VERSION 5.8 ;
BUSBITCHARS "[]" ;
DIVIDERCHAR "/" ;
UNITS
    DATABASE MICRONS 1000 ;
END UNITS

VIA ino_decode_predict_via1_2_1000_440_1_2_410_410
  VIARULE via1Array ;
  CUTSIZE 0.19 0.19 ;
  LAYERS Metal1 Via1 Metal2 ;
  CUTSPACING 0.22 0.22 ;
  ENCLOSURE 0.05 0.125 0.005 0.05 ;
  ROWCOL 1 2 ;
END ino_decode_predict_via1_2_1000_440_1_2_410_410

VIA ino_decode_predict_via2_3_1000_440_1_2_410_410
  VIARULE via2Array ;
  CUTSIZE 0.19 0.19 ;
  LAYERS Metal2 Via2 Metal3 ;
  CUTSPACING 0.22 0.22 ;
  ENCLOSURE 0.005 0.05 0.05 0.005 ;
  ROWCOL 1 2 ;
END ino_decode_predict_via2_3_1000_440_1_2_410_410

VIA ino_decode_predict_via3_4_1000_440_1_2_410_410
  VIARULE via3Array ;
  CUTSIZE 0.19 0.19 ;
  LAYERS Metal3 Via3 Metal4 ;
  CUTSPACING 0.22 0.22 ;
  ENCLOSURE 0.05 0.005 0.2 0.05 ;
  ROWCOL 1 2 ;
END ino_decode_predict_via3_4_1000_440_1_2_410_410

VIA ino_decode_predict_via4_5_1000_2000_1_1_840_840
  VIARULE viaTop1Array ;
  CUTSIZE 0.42 0.42 ;
  LAYERS Metal4 TopVia1 TopMetal1 ;
  CUTSPACING 0.42 0.42 ;
  ENCLOSURE 0.29 0.1 0.42 0.79 ;
END ino_decode_predict_via4_5_1000_2000_1_1_840_840

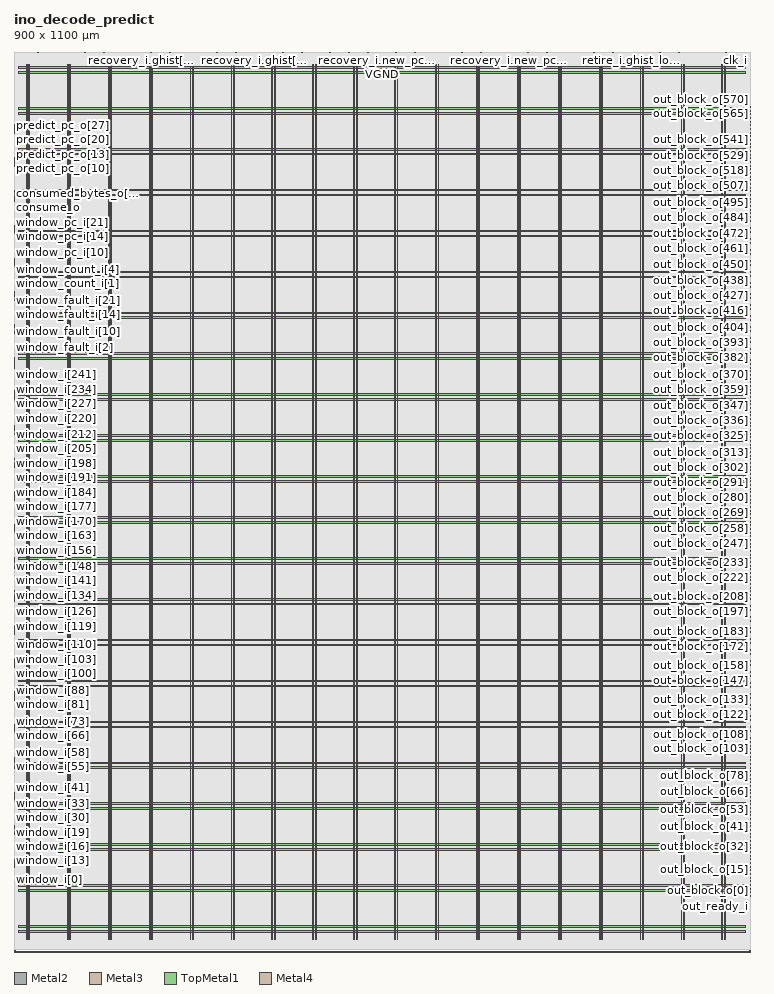
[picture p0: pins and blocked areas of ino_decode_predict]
MACRO ino_decode_predict
  FOREIGN ino_decode_predict 0 0 ;
  CLASS BLOCK ;
  SIZE 900 BY 1100 ;
  PIN clk_i
    DIRECTION INPUT ;
    USE SIGNAL ;
    PORT
      LAYER Metal2 ;
        RECT  881.56 1099.6 881.96 1100 ;
    END
  END clk_i
  PIN consume_o
    DIRECTION OUTPUT ;
    USE SIGNAL ;
    PORT
      LAYER Metal3 ;
        RECT  0 909.94 0.4 910.34 ;
    END
  END consume_o
  PIN consumed_bytes_o[0]
    DIRECTION OUTPUT ;
    USE SIGNAL ;
    PORT
      LAYER Metal3 ;
        RECT  0 912.46 0.4 912.86 ;
    END
  END consumed_bytes_o[0]
  PIN consumed_bytes_o[1]
    DIRECTION OUTPUT ;
    USE SIGNAL ;
    PORT
      LAYER Metal3 ;
        RECT  0 914.98 0.4 915.38 ;
    END
  END consumed_bytes_o[1]
  PIN consumed_bytes_o[2]
    DIRECTION OUTPUT ;
    USE SIGNAL ;
    PORT
      LAYER Metal3 ;
        RECT  0 917.5 0.4 917.9 ;
    END
  END consumed_bytes_o[2]
  PIN consumed_bytes_o[3]
    DIRECTION OUTPUT ;
    USE SIGNAL ;
    PORT
      LAYER Metal3 ;
        RECT  0 920.02 0.4 920.42 ;
    END
  END consumed_bytes_o[3]
  PIN consumed_bytes_o[4]
    DIRECTION OUTPUT ;
    USE SIGNAL ;
    PORT
      LAYER Metal3 ;
        RECT  0 922.54 0.4 922.94 ;
    END
  END consumed_bytes_o[4]
  PIN consumed_bytes_o[5]
    DIRECTION OUTPUT ;
    USE SIGNAL ;
    PORT
      LAYER Metal3 ;
        RECT  0 925.06 0.4 925.46 ;
    END
  END consumed_bytes_o[5]
  PIN out_block_o[0]
    DIRECTION OUTPUT ;
    USE SIGNAL ;
    PORT
      LAYER Metal3 ;
        RECT  899.6 74.98 900 75.38 ;
    END
  END out_block_o[0]
  PIN out_block_o[100]
    DIRECTION OUTPUT ;
    USE SIGNAL ;
    PORT
      LAYER Metal3 ;
        RECT  899.6 242.98 900 243.38 ;
    END
  END out_block_o[100]
  PIN out_block_o[101]
    DIRECTION OUTPUT ;
    USE SIGNAL ;
    PORT
      LAYER Metal3 ;
        RECT  899.6 244.66 900 245.06 ;
    END
  END out_block_o[101]
  PIN out_block_o[102]
    DIRECTION OUTPUT ;
    USE SIGNAL ;
    PORT
      LAYER Metal3 ;
        RECT  899.6 246.34 900 246.74 ;
    END
  END out_block_o[102]
  PIN out_block_o[103]
    DIRECTION OUTPUT ;
    USE SIGNAL ;
    PORT
      LAYER Metal3 ;
        RECT  899.6 248.02 900 248.42 ;
    END
  END out_block_o[103]
  PIN out_block_o[104]
    DIRECTION OUTPUT ;
    USE SIGNAL ;
    PORT
      LAYER Metal3 ;
        RECT  899.6 249.7 900 250.1 ;
    END
  END out_block_o[104]
  PIN out_block_o[105]
    DIRECTION OUTPUT ;
    USE SIGNAL ;
    PORT
      LAYER Metal3 ;
        RECT  899.6 251.38 900 251.78 ;
    END
  END out_block_o[105]
  PIN out_block_o[106]
    DIRECTION OUTPUT ;
    USE SIGNAL ;
    PORT
      LAYER Metal3 ;
        RECT  899.6 253.06 900 253.46 ;
    END
  END out_block_o[106]
  PIN out_block_o[107]
    DIRECTION OUTPUT ;
    USE SIGNAL ;
    PORT
      LAYER Metal3 ;
        RECT  899.6 254.74 900 255.14 ;
    END
  END out_block_o[107]
  PIN out_block_o[108]
    DIRECTION OUTPUT ;
    USE SIGNAL ;
    PORT
      LAYER Metal3 ;
        RECT  899.6 256.42 900 256.82 ;
    END
  END out_block_o[108]
  PIN out_block_o[109]
    DIRECTION OUTPUT ;
    USE SIGNAL ;
    PORT
      LAYER Metal3 ;
        RECT  899.6 258.1 900 258.5 ;
    END
  END out_block_o[109]
  PIN out_block_o[10]
    DIRECTION OUTPUT ;
    USE SIGNAL ;
    PORT
      LAYER Metal3 ;
        RECT  899.6 91.78 900 92.18 ;
    END
  END out_block_o[10]
  PIN out_block_o[110]
    DIRECTION OUTPUT ;
    USE SIGNAL ;
    PORT
      LAYER Metal3 ;
        RECT  899.6 259.78 900 260.18 ;
    END
  END out_block_o[110]
  PIN out_block_o[111]
    DIRECTION OUTPUT ;
    USE SIGNAL ;
    PORT
      LAYER Metal3 ;
        RECT  899.6 261.46 900 261.86 ;
    END
  END out_block_o[111]
  PIN out_block_o[112]
    DIRECTION OUTPUT ;
    USE SIGNAL ;
    PORT
      LAYER Metal3 ;
        RECT  899.6 263.14 900 263.54 ;
    END
  END out_block_o[112]
  PIN out_block_o[113]
    DIRECTION OUTPUT ;
    USE SIGNAL ;
    PORT
      LAYER Metal3 ;
        RECT  899.6 264.82 900 265.22 ;
    END
  END out_block_o[113]
  PIN out_block_o[114]
    DIRECTION OUTPUT ;
    USE SIGNAL ;
    PORT
      LAYER Metal3 ;
        RECT  899.6 266.5 900 266.9 ;
    END
  END out_block_o[114]
  PIN out_block_o[115]
    DIRECTION OUTPUT ;
    USE SIGNAL ;
    PORT
      LAYER Metal3 ;
        RECT  899.6 268.18 900 268.58 ;
    END
  END out_block_o[115]
  PIN out_block_o[116]
    DIRECTION OUTPUT ;
    USE SIGNAL ;
    PORT
      LAYER Metal3 ;
        RECT  899.6 269.86 900 270.26 ;
    END
  END out_block_o[116]
  PIN out_block_o[117]
    DIRECTION OUTPUT ;
    USE SIGNAL ;
    PORT
      LAYER Metal3 ;
        RECT  899.6 271.54 900 271.94 ;
    END
  END out_block_o[117]
  PIN out_block_o[118]
    DIRECTION OUTPUT ;
    USE SIGNAL ;
    PORT
      LAYER Metal3 ;
        RECT  899.6 273.22 900 273.62 ;
    END
  END out_block_o[118]
  PIN out_block_o[119]
    DIRECTION OUTPUT ;
    USE SIGNAL ;
    PORT
      LAYER Metal3 ;
        RECT  899.6 274.9 900 275.3 ;
    END
  END out_block_o[119]
  PIN out_block_o[11]
    DIRECTION OUTPUT ;
    USE SIGNAL ;
    PORT
      LAYER Metal3 ;
        RECT  899.6 93.46 900 93.86 ;
    END
  END out_block_o[11]
  PIN out_block_o[120]
    DIRECTION OUTPUT ;
    USE SIGNAL ;
    PORT
      LAYER Metal3 ;
        RECT  899.6 276.58 900 276.98 ;
    END
  END out_block_o[120]
  PIN out_block_o[121]
    DIRECTION OUTPUT ;
    USE SIGNAL ;
    PORT
      LAYER Metal3 ;
        RECT  899.6 278.26 900 278.66 ;
    END
  END out_block_o[121]
  PIN out_block_o[122]
    DIRECTION OUTPUT ;
    USE SIGNAL ;
    PORT
      LAYER Metal3 ;
        RECT  899.6 279.94 900 280.34 ;
    END
  END out_block_o[122]
  PIN out_block_o[123]
    DIRECTION OUTPUT ;
    USE SIGNAL ;
    PORT
      LAYER Metal3 ;
        RECT  899.6 281.62 900 282.02 ;
    END
  END out_block_o[123]
  PIN out_block_o[124]
    DIRECTION OUTPUT ;
    USE SIGNAL ;
    PORT
      LAYER Metal3 ;
        RECT  899.6 283.3 900 283.7 ;
    END
  END out_block_o[124]
  PIN out_block_o[125]
    DIRECTION OUTPUT ;
    USE SIGNAL ;
    PORT
      LAYER Metal3 ;
        RECT  899.6 284.98 900 285.38 ;
    END
  END out_block_o[125]
  PIN out_block_o[126]
    DIRECTION OUTPUT ;
    USE SIGNAL ;
    PORT
      LAYER Metal3 ;
        RECT  899.6 286.66 900 287.06 ;
    END
  END out_block_o[126]
  PIN out_block_o[127]
    DIRECTION OUTPUT ;
    USE SIGNAL ;
    PORT
      LAYER Metal3 ;
        RECT  899.6 288.34 900 288.74 ;
    END
  END out_block_o[127]
  PIN out_block_o[128]
    DIRECTION OUTPUT ;
    USE SIGNAL ;
    PORT
      LAYER Metal3 ;
        RECT  899.6 290.02 900 290.42 ;
    END
  END out_block_o[128]
  PIN out_block_o[129]
    DIRECTION OUTPUT ;
    USE SIGNAL ;
    PORT
      LAYER Metal3 ;
        RECT  899.6 291.7 900 292.1 ;
    END
  END out_block_o[129]
  PIN out_block_o[12]
    DIRECTION OUTPUT ;
    USE SIGNAL ;
    PORT
      LAYER Metal3 ;
        RECT  899.6 95.14 900 95.54 ;
    END
  END out_block_o[12]
  PIN out_block_o[130]
    DIRECTION OUTPUT ;
    USE SIGNAL ;
    PORT
      LAYER Metal3 ;
        RECT  899.6 293.38 900 293.78 ;
    END
  END out_block_o[130]
  PIN out_block_o[131]
    DIRECTION OUTPUT ;
    USE SIGNAL ;
    PORT
      LAYER Metal3 ;
        RECT  899.6 295.06 900 295.46 ;
    END
  END out_block_o[131]
  PIN out_block_o[132]
    DIRECTION OUTPUT ;
    USE SIGNAL ;
    PORT
      LAYER Metal3 ;
        RECT  899.6 296.74 900 297.14 ;
    END
  END out_block_o[132]
  PIN out_block_o[133]
    DIRECTION OUTPUT ;
    USE SIGNAL ;
    PORT
      LAYER Metal3 ;
        RECT  899.6 298.42 900 298.82 ;
    END
  END out_block_o[133]
  PIN out_block_o[134]
    DIRECTION OUTPUT ;
    USE SIGNAL ;
    PORT
      LAYER Metal3 ;
        RECT  899.6 300.1 900 300.5 ;
    END
  END out_block_o[134]
  PIN out_block_o[135]
    DIRECTION OUTPUT ;
    USE SIGNAL ;
    PORT
      LAYER Metal3 ;
        RECT  899.6 301.78 900 302.18 ;
    END
  END out_block_o[135]
  PIN out_block_o[136]
    DIRECTION OUTPUT ;
    USE SIGNAL ;
    PORT
      LAYER Metal3 ;
        RECT  899.6 303.46 900 303.86 ;
    END
  END out_block_o[136]
  PIN out_block_o[137]
    DIRECTION OUTPUT ;
    USE SIGNAL ;
    PORT
      LAYER Metal3 ;
        RECT  899.6 305.14 900 305.54 ;
    END
  END out_block_o[137]
  PIN out_block_o[138]
    DIRECTION OUTPUT ;
    USE SIGNAL ;
    PORT
      LAYER Metal3 ;
        RECT  899.6 306.82 900 307.22 ;
    END
  END out_block_o[138]
  PIN out_block_o[139]
    DIRECTION OUTPUT ;
    USE SIGNAL ;
    PORT
      LAYER Metal3 ;
        RECT  899.6 308.5 900 308.9 ;
    END
  END out_block_o[139]
  PIN out_block_o[13]
    DIRECTION OUTPUT ;
    USE SIGNAL ;
    PORT
      LAYER Metal3 ;
        RECT  899.6 96.82 900 97.22 ;
    END
  END out_block_o[13]
  PIN out_block_o[140]
    DIRECTION OUTPUT ;
    USE SIGNAL ;
    PORT
      LAYER Metal3 ;
        RECT  899.6 310.18 900 310.58 ;
    END
  END out_block_o[140]
  PIN out_block_o[141]
    DIRECTION OUTPUT ;
    USE SIGNAL ;
    PORT
      LAYER Metal3 ;
        RECT  899.6 311.86 900 312.26 ;
    END
  END out_block_o[141]
  PIN out_block_o[142]
    DIRECTION OUTPUT ;
    USE SIGNAL ;
    PORT
      LAYER Metal3 ;
        RECT  899.6 313.54 900 313.94 ;
    END
  END out_block_o[142]
  PIN out_block_o[143]
    DIRECTION OUTPUT ;
    USE SIGNAL ;
    PORT
      LAYER Metal3 ;
        RECT  899.6 315.22 900 315.62 ;
    END
  END out_block_o[143]
  PIN out_block_o[144]
    DIRECTION OUTPUT ;
    USE SIGNAL ;
    PORT
      LAYER Metal3 ;
        RECT  899.6 316.9 900 317.3 ;
    END
  END out_block_o[144]
  PIN out_block_o[145]
    DIRECTION OUTPUT ;
    USE SIGNAL ;
    PORT
      LAYER Metal3 ;
        RECT  899.6 318.58 900 318.98 ;
    END
  END out_block_o[145]
  PIN out_block_o[146]
    DIRECTION OUTPUT ;
    USE SIGNAL ;
    PORT
      LAYER Metal3 ;
        RECT  899.6 320.26 900 320.66 ;
    END
  END out_block_o[146]
  PIN out_block_o[147]
    DIRECTION OUTPUT ;
    USE SIGNAL ;
    PORT
      LAYER Metal3 ;
        RECT  899.6 321.94 900 322.34 ;
    END
  END out_block_o[147]
  PIN out_block_o[148]
    DIRECTION OUTPUT ;
    USE SIGNAL ;
    PORT
      LAYER Metal3 ;
        RECT  899.6 323.62 900 324.02 ;
    END
  END out_block_o[148]
  PIN out_block_o[149]
    DIRECTION OUTPUT ;
    USE SIGNAL ;
    PORT
      LAYER Metal3 ;
        RECT  899.6 325.3 900 325.7 ;
    END
  END out_block_o[149]
  PIN out_block_o[14]
    DIRECTION OUTPUT ;
    USE SIGNAL ;
    PORT
      LAYER Metal3 ;
        RECT  899.6 98.5 900 98.9 ;
    END
  END out_block_o[14]
  PIN out_block_o[150]
    DIRECTION OUTPUT ;
    USE SIGNAL ;
    PORT
      LAYER Metal3 ;
        RECT  899.6 326.98 900 327.38 ;
    END
  END out_block_o[150]
  PIN out_block_o[151]
    DIRECTION OUTPUT ;
    USE SIGNAL ;
    PORT
      LAYER Metal3 ;
        RECT  899.6 328.66 900 329.06 ;
    END
  END out_block_o[151]
  PIN out_block_o[152]
    DIRECTION OUTPUT ;
    USE SIGNAL ;
    PORT
      LAYER Metal3 ;
        RECT  899.6 330.34 900 330.74 ;
    END
  END out_block_o[152]
  PIN out_block_o[153]
    DIRECTION OUTPUT ;
    USE SIGNAL ;
    PORT
      LAYER Metal3 ;
        RECT  899.6 332.02 900 332.42 ;
    END
  END out_block_o[153]
  PIN out_block_o[154]
    DIRECTION OUTPUT ;
    USE SIGNAL ;
    PORT
      LAYER Metal3 ;
        RECT  899.6 333.7 900 334.1 ;
    END
  END out_block_o[154]
  PIN out_block_o[155]
    DIRECTION OUTPUT ;
    USE SIGNAL ;
    PORT
      LAYER Metal3 ;
        RECT  899.6 335.38 900 335.78 ;
    END
  END out_block_o[155]
  PIN out_block_o[156]
    DIRECTION OUTPUT ;
    USE SIGNAL ;
    PORT
      LAYER Metal3 ;
        RECT  899.6 337.06 900 337.46 ;
    END
  END out_block_o[156]
  PIN out_block_o[157]
    DIRECTION OUTPUT ;
    USE SIGNAL ;
    PORT
      LAYER Metal3 ;
        RECT  899.6 338.74 900 339.14 ;
    END
  END out_block_o[157]
  PIN out_block_o[158]
    DIRECTION OUTPUT ;
    USE SIGNAL ;
    PORT
      LAYER Metal3 ;
        RECT  899.6 340.42 900 340.82 ;
    END
  END out_block_o[158]
  PIN out_block_o[159]
    DIRECTION OUTPUT ;
    USE SIGNAL ;
    PORT
      LAYER Metal3 ;
        RECT  899.6 342.1 900 342.5 ;
    END
  END out_block_o[159]
  PIN out_block_o[15]
    DIRECTION OUTPUT ;
    USE SIGNAL ;
    PORT
      LAYER Metal3 ;
        RECT  899.6 100.18 900 100.58 ;
    END
  END out_block_o[15]
  PIN out_block_o[160]
    DIRECTION OUTPUT ;
    USE SIGNAL ;
    PORT
      LAYER Metal3 ;
        RECT  899.6 343.78 900 344.18 ;
    END
  END out_block_o[160]
  PIN out_block_o[161]
    DIRECTION OUTPUT ;
    USE SIGNAL ;
    PORT
      LAYER Metal3 ;
        RECT  899.6 345.46 900 345.86 ;
    END
  END out_block_o[161]
  PIN out_block_o[162]
    DIRECTION OUTPUT ;
    USE SIGNAL ;
    PORT
      LAYER Metal3 ;
        RECT  899.6 347.14 900 347.54 ;
    END
  END out_block_o[162]
  PIN out_block_o[163]
    DIRECTION OUTPUT ;
    USE SIGNAL ;
    PORT
      LAYER Metal3 ;
        RECT  899.6 348.82 900 349.22 ;
    END
  END out_block_o[163]
  PIN out_block_o[164]
    DIRECTION OUTPUT ;
    USE SIGNAL ;
    PORT
      LAYER Metal3 ;
        RECT  899.6 350.5 900 350.9 ;
    END
  END out_block_o[164]
  PIN out_block_o[165]
    DIRECTION OUTPUT ;
    USE SIGNAL ;
    PORT
      LAYER Metal3 ;
        RECT  899.6 352.18 900 352.58 ;
    END
  END out_block_o[165]
  PIN out_block_o[166]
    DIRECTION OUTPUT ;
    USE SIGNAL ;
    PORT
      LAYER Metal3 ;
        RECT  899.6 353.86 900 354.26 ;
    END
  END out_block_o[166]
  PIN out_block_o[167]
    DIRECTION OUTPUT ;
    USE SIGNAL ;
    PORT
      LAYER Metal3 ;
        RECT  899.6 355.54 900 355.94 ;
    END
  END out_block_o[167]
  PIN out_block_o[168]
    DIRECTION OUTPUT ;
    USE SIGNAL ;
    PORT
      LAYER Metal3 ;
        RECT  899.6 357.22 900 357.62 ;
    END
  END out_block_o[168]
  PIN out_block_o[169]
    DIRECTION OUTPUT ;
    USE SIGNAL ;
    PORT
      LAYER Metal3 ;
        RECT  899.6 358.9 900 359.3 ;
    END
  END out_block_o[169]
  PIN out_block_o[16]
    DIRECTION OUTPUT ;
    USE SIGNAL ;
    PORT
      LAYER Metal3 ;
        RECT  899.6 101.86 900 102.26 ;
    END
  END out_block_o[16]
  PIN out_block_o[170]
    DIRECTION OUTPUT ;
    USE SIGNAL ;
    PORT
      LAYER Metal3 ;
        RECT  899.6 360.58 900 360.98 ;
    END
  END out_block_o[170]
  PIN out_block_o[171]
    DIRECTION OUTPUT ;
    USE SIGNAL ;
    PORT
      LAYER Metal3 ;
        RECT  899.6 362.26 900 362.66 ;
    END
  END out_block_o[171]
  PIN out_block_o[172]
    DIRECTION OUTPUT ;
    USE SIGNAL ;
    PORT
      LAYER Metal3 ;
        RECT  899.6 363.94 900 364.34 ;
    END
  END out_block_o[172]
  PIN out_block_o[173]
    DIRECTION OUTPUT ;
    USE SIGNAL ;
    PORT
      LAYER Metal3 ;
        RECT  899.6 365.62 900 366.02 ;
    END
  END out_block_o[173]
  PIN out_block_o[174]
    DIRECTION OUTPUT ;
    USE SIGNAL ;
    PORT
      LAYER Metal3 ;
        RECT  899.6 367.3 900 367.7 ;
    END
  END out_block_o[174]
  PIN out_block_o[175]
    DIRECTION OUTPUT ;
    USE SIGNAL ;
    PORT
      LAYER Metal3 ;
        RECT  899.6 368.98 900 369.38 ;
    END
  END out_block_o[175]
  PIN out_block_o[176]
    DIRECTION OUTPUT ;
    USE SIGNAL ;
    PORT
      LAYER Metal3 ;
        RECT  899.6 370.66 900 371.06 ;
    END
  END out_block_o[176]
  PIN out_block_o[177]
    DIRECTION OUTPUT ;
    USE SIGNAL ;
    PORT
      LAYER Metal3 ;
        RECT  899.6 372.34 900 372.74 ;
    END
  END out_block_o[177]
  PIN out_block_o[178]
    DIRECTION OUTPUT ;
    USE SIGNAL ;
    PORT
      LAYER Metal3 ;
        RECT  899.6 374.02 900 374.42 ;
    END
  END out_block_o[178]
  PIN out_block_o[179]
    DIRECTION OUTPUT ;
    USE SIGNAL ;
    PORT
      LAYER Metal3 ;
        RECT  899.6 375.7 900 376.1 ;
    END
  END out_block_o[179]
  PIN out_block_o[17]
    DIRECTION OUTPUT ;
    USE SIGNAL ;
    PORT
      LAYER Metal3 ;
        RECT  899.6 103.54 900 103.94 ;
    END
  END out_block_o[17]
  PIN out_block_o[180]
    DIRECTION OUTPUT ;
    USE SIGNAL ;
    PORT
      LAYER Metal3 ;
        RECT  899.6 377.38 900 377.78 ;
    END
  END out_block_o[180]
  PIN out_block_o[181]
    DIRECTION OUTPUT ;
    USE SIGNAL ;
    PORT
      LAYER Metal3 ;
        RECT  899.6 379.06 900 379.46 ;
    END
  END out_block_o[181]
  PIN out_block_o[182]
    DIRECTION OUTPUT ;
    USE SIGNAL ;
    PORT
      LAYER Metal3 ;
        RECT  899.6 380.74 900 381.14 ;
    END
  END out_block_o[182]
  PIN out_block_o[183]
    DIRECTION OUTPUT ;
    USE SIGNAL ;
    PORT
      LAYER Metal3 ;
        RECT  899.6 382.42 900 382.82 ;
    END
  END out_block_o[183]
  PIN out_block_o[184]
    DIRECTION OUTPUT ;
    USE SIGNAL ;
    PORT
      LAYER Metal3 ;
        RECT  899.6 384.1 900 384.5 ;
    END
  END out_block_o[184]
  PIN out_block_o[185]
    DIRECTION OUTPUT ;
    USE SIGNAL ;
    PORT
      LAYER Metal3 ;
        RECT  899.6 385.78 900 386.18 ;
    END
  END out_block_o[185]
  PIN out_block_o[186]
    DIRECTION OUTPUT ;
    USE SIGNAL ;
    PORT
      LAYER Metal3 ;
        RECT  899.6 387.46 900 387.86 ;
    END
  END out_block_o[186]
  PIN out_block_o[187]
    DIRECTION OUTPUT ;
    USE SIGNAL ;
    PORT
      LAYER Metal3 ;
        RECT  899.6 389.14 900 389.54 ;
    END
  END out_block_o[187]
  PIN out_block_o[188]
    DIRECTION OUTPUT ;
    USE SIGNAL ;
    PORT
      LAYER Metal3 ;
        RECT  899.6 390.82 900 391.22 ;
    END
  END out_block_o[188]
  PIN out_block_o[189]
    DIRECTION OUTPUT ;
    USE SIGNAL ;
    PORT
      LAYER Metal3 ;
        RECT  899.6 392.5 900 392.9 ;
    END
  END out_block_o[189]
  PIN out_block_o[18]
    DIRECTION OUTPUT ;
    USE SIGNAL ;
    PORT
      LAYER Metal3 ;
        RECT  899.6 105.22 900 105.62 ;
    END
  END out_block_o[18]
  PIN out_block_o[190]
    DIRECTION OUTPUT ;
    USE SIGNAL ;
    PORT
      LAYER Metal3 ;
        RECT  899.6 394.18 900 394.58 ;
    END
  END out_block_o[190]
  PIN out_block_o[191]
    DIRECTION OUTPUT ;
    USE SIGNAL ;
    PORT
      LAYER Metal3 ;
        RECT  899.6 395.86 900 396.26 ;
    END
  END out_block_o[191]
  PIN out_block_o[192]
    DIRECTION OUTPUT ;
    USE SIGNAL ;
    PORT
      LAYER Metal3 ;
        RECT  899.6 397.54 900 397.94 ;
    END
  END out_block_o[192]
  PIN out_block_o[193]
    DIRECTION OUTPUT ;
    USE SIGNAL ;
    PORT
      LAYER Metal3 ;
        RECT  899.6 399.22 900 399.62 ;
    END
  END out_block_o[193]
  PIN out_block_o[194]
    DIRECTION OUTPUT ;
    USE SIGNAL ;
    PORT
      LAYER Metal3 ;
        RECT  899.6 400.9 900 401.3 ;
    END
  END out_block_o[194]
  PIN out_block_o[195]
    DIRECTION OUTPUT ;
    USE SIGNAL ;
    PORT
      LAYER Metal3 ;
        RECT  899.6 402.58 900 402.98 ;
    END
  END out_block_o[195]
  PIN out_block_o[196]
    DIRECTION OUTPUT ;
    USE SIGNAL ;
    PORT
      LAYER Metal3 ;
        RECT  899.6 404.26 900 404.66 ;
    END
  END out_block_o[196]
  PIN out_block_o[197]
    DIRECTION OUTPUT ;
    USE SIGNAL ;
    PORT
      LAYER Metal3 ;
        RECT  899.6 405.94 900 406.34 ;
    END
  END out_block_o[197]
  PIN out_block_o[198]
    DIRECTION OUTPUT ;
    USE SIGNAL ;
    PORT
      LAYER Metal3 ;
        RECT  899.6 407.62 900 408.02 ;
    END
  END out_block_o[198]
  PIN out_block_o[199]
    DIRECTION OUTPUT ;
    USE SIGNAL ;
    PORT
      LAYER Metal3 ;
        RECT  899.6 409.3 900 409.7 ;
    END
  END out_block_o[199]
  PIN out_block_o[19]
    DIRECTION OUTPUT ;
    USE SIGNAL ;
    PORT
      LAYER Metal3 ;
        RECT  899.6 106.9 900 107.3 ;
    END
  END out_block_o[19]
  PIN out_block_o[1]
    DIRECTION OUTPUT ;
    USE SIGNAL ;
    PORT
      LAYER Metal3 ;
        RECT  899.6 76.66 900 77.06 ;
    END
  END out_block_o[1]
  PIN out_block_o[200]
    DIRECTION OUTPUT ;
    USE SIGNAL ;
    PORT
      LAYER Metal3 ;
        RECT  899.6 410.98 900 411.38 ;
    END
  END out_block_o[200]
  PIN out_block_o[201]
    DIRECTION OUTPUT ;
    USE SIGNAL ;
    PORT
      LAYER Metal3 ;
        RECT  899.6 412.66 900 413.06 ;
    END
  END out_block_o[201]
  PIN out_block_o[202]
    DIRECTION OUTPUT ;
    USE SIGNAL ;
    PORT
      LAYER Metal3 ;
        RECT  899.6 414.34 900 414.74 ;
    END
  END out_block_o[202]
  PIN out_block_o[203]
    DIRECTION OUTPUT ;
    USE SIGNAL ;
    PORT
      LAYER Metal3 ;
        RECT  899.6 416.02 900 416.42 ;
    END
  END out_block_o[203]
  PIN out_block_o[204]
    DIRECTION OUTPUT ;
    USE SIGNAL ;
    PORT
      LAYER Metal3 ;
        RECT  899.6 417.7 900 418.1 ;
    END
  END out_block_o[204]
  PIN out_block_o[205]
    DIRECTION OUTPUT ;
    USE SIGNAL ;
    PORT
      LAYER Metal3 ;
        RECT  899.6 419.38 900 419.78 ;
    END
  END out_block_o[205]
  PIN out_block_o[206]
    DIRECTION OUTPUT ;
    USE SIGNAL ;
    PORT
      LAYER Metal3 ;
        RECT  899.6 421.06 900 421.46 ;
    END
  END out_block_o[206]
  PIN out_block_o[207]
    DIRECTION OUTPUT ;
    USE SIGNAL ;
    PORT
      LAYER Metal3 ;
        RECT  899.6 422.74 900 423.14 ;
    END
  END out_block_o[207]
  PIN out_block_o[208]
    DIRECTION OUTPUT ;
    USE SIGNAL ;
    PORT
      LAYER Metal3 ;
        RECT  899.6 424.42 900 424.82 ;
    END
  END out_block_o[208]
  PIN out_block_o[209]
    DIRECTION OUTPUT ;
    USE SIGNAL ;
    PORT
      LAYER Metal3 ;
        RECT  899.6 426.1 900 426.5 ;
    END
  END out_block_o[209]
  PIN out_block_o[20]
    DIRECTION OUTPUT ;
    USE SIGNAL ;
    PORT
      LAYER Metal3 ;
        RECT  899.6 108.58 900 108.98 ;
    END
  END out_block_o[20]
  PIN out_block_o[210]
    DIRECTION OUTPUT ;
    USE SIGNAL ;
    PORT
      LAYER Metal3 ;
        RECT  899.6 427.78 900 428.18 ;
    END
  END out_block_o[210]
  PIN out_block_o[211]
    DIRECTION OUTPUT ;
    USE SIGNAL ;
    PORT
      LAYER Metal3 ;
        RECT  899.6 429.46 900 429.86 ;
    END
  END out_block_o[211]
  PIN out_block_o[212]
    DIRECTION OUTPUT ;
    USE SIGNAL ;
    PORT
      LAYER Metal3 ;
        RECT  899.6 431.14 900 431.54 ;
    END
  END out_block_o[212]
  PIN out_block_o[213]
    DIRECTION OUTPUT ;
    USE SIGNAL ;
    PORT
      LAYER Metal3 ;
        RECT  899.6 432.82 900 433.22 ;
    END
  END out_block_o[213]
  PIN out_block_o[214]
    DIRECTION OUTPUT ;
    USE SIGNAL ;
    PORT
      LAYER Metal3 ;
        RECT  899.6 434.5 900 434.9 ;
    END
  END out_block_o[214]
  PIN out_block_o[215]
    DIRECTION OUTPUT ;
    USE SIGNAL ;
    PORT
      LAYER Metal3 ;
        RECT  899.6 436.18 900 436.58 ;
    END
  END out_block_o[215]
  PIN out_block_o[216]
    DIRECTION OUTPUT ;
    USE SIGNAL ;
    PORT
      LAYER Metal3 ;
        RECT  899.6 437.86 900 438.26 ;
    END
  END out_block_o[216]
  PIN out_block_o[217]
    DIRECTION OUTPUT ;
    USE SIGNAL ;
    PORT
      LAYER Metal3 ;
        RECT  899.6 439.54 900 439.94 ;
    END
  END out_block_o[217]
  PIN out_block_o[218]
    DIRECTION OUTPUT ;
    USE SIGNAL ;
    PORT
      LAYER Metal3 ;
        RECT  899.6 441.22 900 441.62 ;
    END
  END out_block_o[218]
  PIN out_block_o[219]
    DIRECTION OUTPUT ;
    USE SIGNAL ;
    PORT
      LAYER Metal3 ;
        RECT  899.6 442.9 900 443.3 ;
    END
  END out_block_o[219]
  PIN out_block_o[21]
    DIRECTION OUTPUT ;
    USE SIGNAL ;
    PORT
      LAYER Metal3 ;
        RECT  899.6 110.26 900 110.66 ;
    END
  END out_block_o[21]
  PIN out_block_o[220]
    DIRECTION OUTPUT ;
    USE SIGNAL ;
    PORT
      LAYER Metal3 ;
        RECT  899.6 444.58 900 444.98 ;
    END
  END out_block_o[220]
  PIN out_block_o[221]
    DIRECTION OUTPUT ;
    USE SIGNAL ;
    PORT
      LAYER Metal3 ;
        RECT  899.6 446.26 900 446.66 ;
    END
  END out_block_o[221]
  PIN out_block_o[222]
    DIRECTION OUTPUT ;
    USE SIGNAL ;
    PORT
      LAYER Metal3 ;
        RECT  899.6 447.94 900 448.34 ;
    END
  END out_block_o[222]
  PIN out_block_o[223]
    DIRECTION OUTPUT ;
    USE SIGNAL ;
    PORT
      LAYER Metal3 ;
        RECT  899.6 449.62 900 450.02 ;
    END
  END out_block_o[223]
  PIN out_block_o[224]
    DIRECTION OUTPUT ;
    USE SIGNAL ;
    PORT
      LAYER Metal3 ;
        RECT  899.6 451.3 900 451.7 ;
    END
  END out_block_o[224]
  PIN out_block_o[225]
    DIRECTION OUTPUT ;
    USE SIGNAL ;
    PORT
      LAYER Metal3 ;
        RECT  899.6 452.98 900 453.38 ;
    END
  END out_block_o[225]
  PIN out_block_o[226]
    DIRECTION OUTPUT ;
    USE SIGNAL ;
    PORT
      LAYER Metal3 ;
        RECT  899.6 454.66 900 455.06 ;
    END
  END out_block_o[226]
  PIN out_block_o[227]
    DIRECTION OUTPUT ;
    USE SIGNAL ;
    PORT
      LAYER Metal3 ;
        RECT  899.6 456.34 900 456.74 ;
    END
  END out_block_o[227]
  PIN out_block_o[228]
    DIRECTION OUTPUT ;
    USE SIGNAL ;
    PORT
      LAYER Metal3 ;
        RECT  899.6 458.02 900 458.42 ;
    END
  END out_block_o[228]
  PIN out_block_o[229]
    DIRECTION OUTPUT ;
    USE SIGNAL ;
    PORT
      LAYER Metal3 ;
        RECT  899.6 459.7 900 460.1 ;
    END
  END out_block_o[229]
  PIN out_block_o[22]
    DIRECTION OUTPUT ;
    USE SIGNAL ;
    PORT
      LAYER Metal3 ;
        RECT  899.6 111.94 900 112.34 ;
    END
  END out_block_o[22]
  PIN out_block_o[230]
    DIRECTION OUTPUT ;
    USE SIGNAL ;
    PORT
      LAYER Metal3 ;
        RECT  899.6 461.38 900 461.78 ;
    END
  END out_block_o[230]
  PIN out_block_o[231]
    DIRECTION OUTPUT ;
    USE SIGNAL ;
    PORT
      LAYER Metal3 ;
        RECT  899.6 463.06 900 463.46 ;
    END
  END out_block_o[231]
  PIN out_block_o[232]
    DIRECTION OUTPUT ;
    USE SIGNAL ;
    PORT
      LAYER Metal3 ;
        RECT  899.6 464.74 900 465.14 ;
    END
  END out_block_o[232]
  PIN out_block_o[233]
    DIRECTION OUTPUT ;
    USE SIGNAL ;
    PORT
      LAYER Metal3 ;
        RECT  899.6 466.42 900 466.82 ;
    END
  END out_block_o[233]
  PIN out_block_o[234]
    DIRECTION OUTPUT ;
    USE SIGNAL ;
    PORT
      LAYER Metal3 ;
        RECT  899.6 468.1 900 468.5 ;
    END
  END out_block_o[234]
  PIN out_block_o[235]
    DIRECTION OUTPUT ;
    USE SIGNAL ;
    PORT
      LAYER Metal3 ;
        RECT  899.6 469.78 900 470.18 ;
    END
  END out_block_o[235]
  PIN out_block_o[236]
    DIRECTION OUTPUT ;
    USE SIGNAL ;
    PORT
      LAYER Metal3 ;
        RECT  899.6 471.46 900 471.86 ;
    END
  END out_block_o[236]
  PIN out_block_o[237]
    DIRECTION OUTPUT ;
    USE SIGNAL ;
    PORT
      LAYER Metal3 ;
        RECT  899.6 473.14 900 473.54 ;
    END
  END out_block_o[237]
  PIN out_block_o[238]
    DIRECTION OUTPUT ;
    USE SIGNAL ;
    PORT
      LAYER Metal3 ;
        RECT  899.6 474.82 900 475.22 ;
    END
  END out_block_o[238]
  PIN out_block_o[239]
    DIRECTION OUTPUT ;
    USE SIGNAL ;
    PORT
      LAYER Metal3 ;
        RECT  899.6 476.5 900 476.9 ;
    END
  END out_block_o[239]
  PIN out_block_o[23]
    DIRECTION OUTPUT ;
    USE SIGNAL ;
    PORT
      LAYER Metal3 ;
        RECT  899.6 113.62 900 114.02 ;
    END
  END out_block_o[23]
  PIN out_block_o[240]
    DIRECTION OUTPUT ;
    USE SIGNAL ;
    PORT
      LAYER Metal3 ;
        RECT  899.6 478.18 900 478.58 ;
    END
  END out_block_o[240]
  PIN out_block_o[241]
    DIRECTION OUTPUT ;
    USE SIGNAL ;
    PORT
      LAYER Metal3 ;
        RECT  899.6 479.86 900 480.26 ;
    END
  END out_block_o[241]
  PIN out_block_o[242]
    DIRECTION OUTPUT ;
    USE SIGNAL ;
    PORT
      LAYER Metal3 ;
        RECT  899.6 481.54 900 481.94 ;
    END
  END out_block_o[242]
  PIN out_block_o[243]
    DIRECTION OUTPUT ;
    USE SIGNAL ;
    PORT
      LAYER Metal3 ;
        RECT  899.6 483.22 900 483.62 ;
    END
  END out_block_o[243]
  PIN out_block_o[244]
    DIRECTION OUTPUT ;
    USE SIGNAL ;
    PORT
      LAYER Metal3 ;
        RECT  899.6 484.9 900 485.3 ;
    END
  END out_block_o[244]
  PIN out_block_o[245]
    DIRECTION OUTPUT ;
    USE SIGNAL ;
    PORT
      LAYER Metal3 ;
        RECT  899.6 486.58 900 486.98 ;
    END
  END out_block_o[245]
  PIN out_block_o[246]
    DIRECTION OUTPUT ;
    USE SIGNAL ;
    PORT
      LAYER Metal3 ;
        RECT  899.6 488.26 900 488.66 ;
    END
  END out_block_o[246]
  PIN out_block_o[247]
    DIRECTION OUTPUT ;
    USE SIGNAL ;
    PORT
      LAYER Metal3 ;
        RECT  899.6 489.94 900 490.34 ;
    END
  END out_block_o[247]
  PIN out_block_o[248]
    DIRECTION OUTPUT ;
    USE SIGNAL ;
    PORT
      LAYER Metal3 ;
        RECT  899.6 491.62 900 492.02 ;
    END
  END out_block_o[248]
  PIN out_block_o[249]
    DIRECTION OUTPUT ;
    USE SIGNAL ;
    PORT
      LAYER Metal3 ;
        RECT  899.6 493.3 900 493.7 ;
    END
  END out_block_o[249]
  PIN out_block_o[24]
    DIRECTION OUTPUT ;
    USE SIGNAL ;
    PORT
      LAYER Metal3 ;
        RECT  899.6 115.3 900 115.7 ;
    END
  END out_block_o[24]
  PIN out_block_o[250]
    DIRECTION OUTPUT ;
    USE SIGNAL ;
    PORT
      LAYER Metal3 ;
        RECT  899.6 494.98 900 495.38 ;
    END
  END out_block_o[250]
  PIN out_block_o[251]
    DIRECTION OUTPUT ;
    USE SIGNAL ;
    PORT
      LAYER Metal3 ;
        RECT  899.6 496.66 900 497.06 ;
    END
  END out_block_o[251]
  PIN out_block_o[252]
    DIRECTION OUTPUT ;
    USE SIGNAL ;
    PORT
      LAYER Metal3 ;
        RECT  899.6 498.34 900 498.74 ;
    END
  END out_block_o[252]
  PIN out_block_o[253]
    DIRECTION OUTPUT ;
    USE SIGNAL ;
    PORT
      LAYER Metal3 ;
        RECT  899.6 500.02 900 500.42 ;
    END
  END out_block_o[253]
  PIN out_block_o[254]
    DIRECTION OUTPUT ;
    USE SIGNAL ;
    PORT
      LAYER Metal3 ;
        RECT  899.6 501.7 900 502.1 ;
    END
  END out_block_o[254]
  PIN out_block_o[255]
    DIRECTION OUTPUT ;
    USE SIGNAL ;
    PORT
      LAYER Metal3 ;
        RECT  899.6 503.38 900 503.78 ;
    END
  END out_block_o[255]
  PIN out_block_o[256]
    DIRECTION OUTPUT ;
    USE SIGNAL ;
    PORT
      LAYER Metal3 ;
        RECT  899.6 505.06 900 505.46 ;
    END
  END out_block_o[256]
  PIN out_block_o[257]
    DIRECTION OUTPUT ;
    USE SIGNAL ;
    PORT
      LAYER Metal3 ;
        RECT  899.6 506.74 900 507.14 ;
    END
  END out_block_o[257]
  PIN out_block_o[258]
    DIRECTION OUTPUT ;
    USE SIGNAL ;
    PORT
      LAYER Metal3 ;
        RECT  899.6 508.42 900 508.82 ;
    END
  END out_block_o[258]
  PIN out_block_o[259]
    DIRECTION OUTPUT ;
    USE SIGNAL ;
    PORT
      LAYER Metal3 ;
        RECT  899.6 510.1 900 510.5 ;
    END
  END out_block_o[259]
  PIN out_block_o[25]
    DIRECTION OUTPUT ;
    USE SIGNAL ;
    PORT
      LAYER Metal3 ;
        RECT  899.6 116.98 900 117.38 ;
    END
  END out_block_o[25]
  PIN out_block_o[260]
    DIRECTION OUTPUT ;
    USE SIGNAL ;
    PORT
      LAYER Metal3 ;
        RECT  899.6 511.78 900 512.18 ;
    END
  END out_block_o[260]
  PIN out_block_o[261]
    DIRECTION OUTPUT ;
    USE SIGNAL ;
    PORT
      LAYER Metal3 ;
        RECT  899.6 513.46 900 513.86 ;
    END
  END out_block_o[261]
  PIN out_block_o[262]
    DIRECTION OUTPUT ;
    USE SIGNAL ;
    PORT
      LAYER Metal3 ;
        RECT  899.6 515.14 900 515.54 ;
    END
  END out_block_o[262]
  PIN out_block_o[263]
    DIRECTION OUTPUT ;
    USE SIGNAL ;
    PORT
      LAYER Metal3 ;
        RECT  899.6 516.82 900 517.22 ;
    END
  END out_block_o[263]
  PIN out_block_o[264]
    DIRECTION OUTPUT ;
    USE SIGNAL ;
    PORT
      LAYER Metal3 ;
        RECT  899.6 518.5 900 518.9 ;
    END
  END out_block_o[264]
  PIN out_block_o[265]
    DIRECTION OUTPUT ;
    USE SIGNAL ;
    PORT
      LAYER Metal3 ;
        RECT  899.6 520.18 900 520.58 ;
    END
  END out_block_o[265]
  PIN out_block_o[266]
    DIRECTION OUTPUT ;
    USE SIGNAL ;
    PORT
      LAYER Metal3 ;
        RECT  899.6 521.86 900 522.26 ;
    END
  END out_block_o[266]
  PIN out_block_o[267]
    DIRECTION OUTPUT ;
    USE SIGNAL ;
    PORT
      LAYER Metal3 ;
        RECT  899.6 523.54 900 523.94 ;
    END
  END out_block_o[267]
  PIN out_block_o[268]
    DIRECTION OUTPUT ;
    USE SIGNAL ;
    PORT
      LAYER Metal3 ;
        RECT  899.6 525.22 900 525.62 ;
    END
  END out_block_o[268]
  PIN out_block_o[269]
    DIRECTION OUTPUT ;
    USE SIGNAL ;
    PORT
      LAYER Metal3 ;
        RECT  899.6 526.9 900 527.3 ;
    END
  END out_block_o[269]
  PIN out_block_o[26]
    DIRECTION OUTPUT ;
    USE SIGNAL ;
    PORT
      LAYER Metal3 ;
        RECT  899.6 118.66 900 119.06 ;
    END
  END out_block_o[26]
  PIN out_block_o[270]
    DIRECTION OUTPUT ;
    USE SIGNAL ;
    PORT
      LAYER Metal3 ;
        RECT  899.6 528.58 900 528.98 ;
    END
  END out_block_o[270]
  PIN out_block_o[271]
    DIRECTION OUTPUT ;
    USE SIGNAL ;
    PORT
      LAYER Metal3 ;
        RECT  899.6 530.26 900 530.66 ;
    END
  END out_block_o[271]
  PIN out_block_o[272]
    DIRECTION OUTPUT ;
    USE SIGNAL ;
    PORT
      LAYER Metal3 ;
        RECT  899.6 531.94 900 532.34 ;
    END
  END out_block_o[272]
  PIN out_block_o[273]
    DIRECTION OUTPUT ;
    USE SIGNAL ;
    PORT
      LAYER Metal3 ;
        RECT  899.6 533.62 900 534.02 ;
    END
  END out_block_o[273]
  PIN out_block_o[274]
    DIRECTION OUTPUT ;
    USE SIGNAL ;
    PORT
      LAYER Metal3 ;
        RECT  899.6 535.3 900 535.7 ;
    END
  END out_block_o[274]
  PIN out_block_o[275]
    DIRECTION OUTPUT ;
    USE SIGNAL ;
    PORT
      LAYER Metal3 ;
        RECT  899.6 536.98 900 537.38 ;
    END
  END out_block_o[275]
  PIN out_block_o[276]
    DIRECTION OUTPUT ;
    USE SIGNAL ;
    PORT
      LAYER Metal3 ;
        RECT  899.6 538.66 900 539.06 ;
    END
  END out_block_o[276]
  PIN out_block_o[277]
    DIRECTION OUTPUT ;
    USE SIGNAL ;
    PORT
      LAYER Metal3 ;
        RECT  899.6 540.34 900 540.74 ;
    END
  END out_block_o[277]
  PIN out_block_o[278]
    DIRECTION OUTPUT ;
    USE SIGNAL ;
    PORT
      LAYER Metal3 ;
        RECT  899.6 542.02 900 542.42 ;
    END
  END out_block_o[278]
  PIN out_block_o[279]
    DIRECTION OUTPUT ;
    USE SIGNAL ;
    PORT
      LAYER Metal3 ;
        RECT  899.6 543.7 900 544.1 ;
    END
  END out_block_o[279]
  PIN out_block_o[27]
    DIRECTION OUTPUT ;
    USE SIGNAL ;
    PORT
      LAYER Metal3 ;
        RECT  899.6 120.34 900 120.74 ;
    END
  END out_block_o[27]
  PIN out_block_o[280]
    DIRECTION OUTPUT ;
    USE SIGNAL ;
    PORT
      LAYER Metal3 ;
        RECT  899.6 545.38 900 545.78 ;
    END
  END out_block_o[280]
  PIN out_block_o[281]
    DIRECTION OUTPUT ;
    USE SIGNAL ;
    PORT
      LAYER Metal3 ;
        RECT  899.6 547.06 900 547.46 ;
    END
  END out_block_o[281]
  PIN out_block_o[282]
    DIRECTION OUTPUT ;
    USE SIGNAL ;
    PORT
      LAYER Metal3 ;
        RECT  899.6 548.74 900 549.14 ;
    END
  END out_block_o[282]
  PIN out_block_o[283]
    DIRECTION OUTPUT ;
    USE SIGNAL ;
    PORT
      LAYER Metal3 ;
        RECT  899.6 550.42 900 550.82 ;
    END
  END out_block_o[283]
  PIN out_block_o[284]
    DIRECTION OUTPUT ;
    USE SIGNAL ;
    PORT
      LAYER Metal3 ;
        RECT  899.6 552.1 900 552.5 ;
    END
  END out_block_o[284]
  PIN out_block_o[285]
    DIRECTION OUTPUT ;
    USE SIGNAL ;
    PORT
      LAYER Metal3 ;
        RECT  899.6 553.78 900 554.18 ;
    END
  END out_block_o[285]
  PIN out_block_o[286]
    DIRECTION OUTPUT ;
    USE SIGNAL ;
    PORT
      LAYER Metal3 ;
        RECT  899.6 555.46 900 555.86 ;
    END
  END out_block_o[286]
  PIN out_block_o[287]
    DIRECTION OUTPUT ;
    USE SIGNAL ;
    PORT
      LAYER Metal3 ;
        RECT  899.6 557.14 900 557.54 ;
    END
  END out_block_o[287]
  PIN out_block_o[288]
    DIRECTION OUTPUT ;
    USE SIGNAL ;
    PORT
      LAYER Metal3 ;
        RECT  899.6 558.82 900 559.22 ;
    END
  END out_block_o[288]
  PIN out_block_o[289]
    DIRECTION OUTPUT ;
    USE SIGNAL ;
    PORT
      LAYER Metal3 ;
        RECT  899.6 560.5 900 560.9 ;
    END
  END out_block_o[289]
  PIN out_block_o[28]
    DIRECTION OUTPUT ;
    USE SIGNAL ;
    PORT
      LAYER Metal3 ;
        RECT  899.6 122.02 900 122.42 ;
    END
  END out_block_o[28]
  PIN out_block_o[290]
    DIRECTION OUTPUT ;
    USE SIGNAL ;
    PORT
      LAYER Metal3 ;
        RECT  899.6 562.18 900 562.58 ;
    END
  END out_block_o[290]
  PIN out_block_o[291]
    DIRECTION OUTPUT ;
    USE SIGNAL ;
    PORT
      LAYER Metal3 ;
        RECT  899.6 563.86 900 564.26 ;
    END
  END out_block_o[291]
  PIN out_block_o[292]
    DIRECTION OUTPUT ;
    USE SIGNAL ;
    PORT
      LAYER Metal3 ;
        RECT  899.6 565.54 900 565.94 ;
    END
  END out_block_o[292]
  PIN out_block_o[293]
    DIRECTION OUTPUT ;
    USE SIGNAL ;
    PORT
      LAYER Metal3 ;
        RECT  899.6 567.22 900 567.62 ;
    END
  END out_block_o[293]
  PIN out_block_o[294]
    DIRECTION OUTPUT ;
    USE SIGNAL ;
    PORT
      LAYER Metal3 ;
        RECT  899.6 568.9 900 569.3 ;
    END
  END out_block_o[294]
  PIN out_block_o[295]
    DIRECTION OUTPUT ;
    USE SIGNAL ;
    PORT
      LAYER Metal3 ;
        RECT  899.6 570.58 900 570.98 ;
    END
  END out_block_o[295]
  PIN out_block_o[296]
    DIRECTION OUTPUT ;
    USE SIGNAL ;
    PORT
      LAYER Metal3 ;
        RECT  899.6 572.26 900 572.66 ;
    END
  END out_block_o[296]
  PIN out_block_o[297]
    DIRECTION OUTPUT ;
    USE SIGNAL ;
    PORT
      LAYER Metal3 ;
        RECT  899.6 573.94 900 574.34 ;
    END
  END out_block_o[297]
  PIN out_block_o[298]
    DIRECTION OUTPUT ;
    USE SIGNAL ;
    PORT
      LAYER Metal3 ;
        RECT  899.6 575.62 900 576.02 ;
    END
  END out_block_o[298]
  PIN out_block_o[299]
    DIRECTION OUTPUT ;
    USE SIGNAL ;
    PORT
      LAYER Metal3 ;
        RECT  899.6 577.3 900 577.7 ;
    END
  END out_block_o[299]
  PIN out_block_o[29]
    DIRECTION OUTPUT ;
    USE SIGNAL ;
    PORT
      LAYER Metal3 ;
        RECT  899.6 123.7 900 124.1 ;
    END
  END out_block_o[29]
  PIN out_block_o[2]
    DIRECTION OUTPUT ;
    USE SIGNAL ;
    PORT
      LAYER Metal3 ;
        RECT  899.6 78.34 900 78.74 ;
    END
  END out_block_o[2]
  PIN out_block_o[300]
    DIRECTION OUTPUT ;
    USE SIGNAL ;
    PORT
      LAYER Metal3 ;
        RECT  899.6 578.98 900 579.38 ;
    END
  END out_block_o[300]
  PIN out_block_o[301]
    DIRECTION OUTPUT ;
    USE SIGNAL ;
    PORT
      LAYER Metal3 ;
        RECT  899.6 580.66 900 581.06 ;
    END
  END out_block_o[301]
  PIN out_block_o[302]
    DIRECTION OUTPUT ;
    USE SIGNAL ;
    PORT
      LAYER Metal3 ;
        RECT  899.6 582.34 900 582.74 ;
    END
  END out_block_o[302]
  PIN out_block_o[303]
    DIRECTION OUTPUT ;
    USE SIGNAL ;
    PORT
      LAYER Metal3 ;
        RECT  899.6 584.02 900 584.42 ;
    END
  END out_block_o[303]
  PIN out_block_o[304]
    DIRECTION OUTPUT ;
    USE SIGNAL ;
    PORT
      LAYER Metal3 ;
        RECT  899.6 585.7 900 586.1 ;
    END
  END out_block_o[304]
  PIN out_block_o[305]
    DIRECTION OUTPUT ;
    USE SIGNAL ;
    PORT
      LAYER Metal3 ;
        RECT  899.6 587.38 900 587.78 ;
    END
  END out_block_o[305]
  PIN out_block_o[306]
    DIRECTION OUTPUT ;
    USE SIGNAL ;
    PORT
      LAYER Metal3 ;
        RECT  899.6 589.06 900 589.46 ;
    END
  END out_block_o[306]
  PIN out_block_o[307]
    DIRECTION OUTPUT ;
    USE SIGNAL ;
    PORT
      LAYER Metal3 ;
        RECT  899.6 590.74 900 591.14 ;
    END
  END out_block_o[307]
  PIN out_block_o[308]
    DIRECTION OUTPUT ;
    USE SIGNAL ;
    PORT
      LAYER Metal3 ;
        RECT  899.6 592.42 900 592.82 ;
    END
  END out_block_o[308]
  PIN out_block_o[309]
    DIRECTION OUTPUT ;
    USE SIGNAL ;
    PORT
      LAYER Metal3 ;
        RECT  899.6 594.1 900 594.5 ;
    END
  END out_block_o[309]
  PIN out_block_o[30]
    DIRECTION OUTPUT ;
    USE SIGNAL ;
    PORT
      LAYER Metal3 ;
        RECT  899.6 125.38 900 125.78 ;
    END
  END out_block_o[30]
  PIN out_block_o[310]
    DIRECTION OUTPUT ;
    USE SIGNAL ;
    PORT
      LAYER Metal3 ;
        RECT  899.6 595.78 900 596.18 ;
    END
  END out_block_o[310]
  PIN out_block_o[311]
    DIRECTION OUTPUT ;
    USE SIGNAL ;
    PORT
      LAYER Metal3 ;
        RECT  899.6 597.46 900 597.86 ;
    END
  END out_block_o[311]
  PIN out_block_o[312]
    DIRECTION OUTPUT ;
    USE SIGNAL ;
    PORT
      LAYER Metal3 ;
        RECT  899.6 599.14 900 599.54 ;
    END
  END out_block_o[312]
  PIN out_block_o[313]
    DIRECTION OUTPUT ;
    USE SIGNAL ;
    PORT
      LAYER Metal3 ;
        RECT  899.6 600.82 900 601.22 ;
    END
  END out_block_o[313]
  PIN out_block_o[314]
    DIRECTION OUTPUT ;
    USE SIGNAL ;
    PORT
      LAYER Metal3 ;
        RECT  899.6 602.5 900 602.9 ;
    END
  END out_block_o[314]
  PIN out_block_o[315]
    DIRECTION OUTPUT ;
    USE SIGNAL ;
    PORT
      LAYER Metal3 ;
        RECT  899.6 604.18 900 604.58 ;
    END
  END out_block_o[315]
  PIN out_block_o[316]
    DIRECTION OUTPUT ;
    USE SIGNAL ;
    PORT
      LAYER Metal3 ;
        RECT  899.6 605.86 900 606.26 ;
    END
  END out_block_o[316]
  PIN out_block_o[317]
    DIRECTION OUTPUT ;
    USE SIGNAL ;
    PORT
      LAYER Metal3 ;
        RECT  899.6 607.54 900 607.94 ;
    END
  END out_block_o[317]
  PIN out_block_o[318]
    DIRECTION OUTPUT ;
    USE SIGNAL ;
    PORT
      LAYER Metal3 ;
        RECT  899.6 609.22 900 609.62 ;
    END
  END out_block_o[318]
  PIN out_block_o[319]
    DIRECTION OUTPUT ;
    USE SIGNAL ;
    PORT
      LAYER Metal3 ;
        RECT  899.6 610.9 900 611.3 ;
    END
  END out_block_o[319]
  PIN out_block_o[31]
    DIRECTION OUTPUT ;
    USE SIGNAL ;
    PORT
      LAYER Metal3 ;
        RECT  899.6 127.06 900 127.46 ;
    END
  END out_block_o[31]
  PIN out_block_o[320]
    DIRECTION OUTPUT ;
    USE SIGNAL ;
    PORT
      LAYER Metal3 ;
        RECT  899.6 612.58 900 612.98 ;
    END
  END out_block_o[320]
  PIN out_block_o[321]
    DIRECTION OUTPUT ;
    USE SIGNAL ;
    PORT
      LAYER Metal3 ;
        RECT  899.6 614.26 900 614.66 ;
    END
  END out_block_o[321]
  PIN out_block_o[322]
    DIRECTION OUTPUT ;
    USE SIGNAL ;
    PORT
      LAYER Metal3 ;
        RECT  899.6 615.94 900 616.34 ;
    END
  END out_block_o[322]
  PIN out_block_o[323]
    DIRECTION OUTPUT ;
    USE SIGNAL ;
    PORT
      LAYER Metal3 ;
        RECT  899.6 617.62 900 618.02 ;
    END
  END out_block_o[323]
  PIN out_block_o[324]
    DIRECTION OUTPUT ;
    USE SIGNAL ;
    PORT
      LAYER Metal3 ;
        RECT  899.6 619.3 900 619.7 ;
    END
  END out_block_o[324]
  PIN out_block_o[325]
    DIRECTION OUTPUT ;
    USE SIGNAL ;
    PORT
      LAYER Metal3 ;
        RECT  899.6 620.98 900 621.38 ;
    END
  END out_block_o[325]
  PIN out_block_o[326]
    DIRECTION OUTPUT ;
    USE SIGNAL ;
    PORT
      LAYER Metal3 ;
        RECT  899.6 622.66 900 623.06 ;
    END
  END out_block_o[326]
  PIN out_block_o[327]
    DIRECTION OUTPUT ;
    USE SIGNAL ;
    PORT
      LAYER Metal3 ;
        RECT  899.6 624.34 900 624.74 ;
    END
  END out_block_o[327]
  PIN out_block_o[328]
    DIRECTION OUTPUT ;
    USE SIGNAL ;
    PORT
      LAYER Metal3 ;
        RECT  899.6 626.02 900 626.42 ;
    END
  END out_block_o[328]
  PIN out_block_o[329]
    DIRECTION OUTPUT ;
    USE SIGNAL ;
    PORT
      LAYER Metal3 ;
        RECT  899.6 627.7 900 628.1 ;
    END
  END out_block_o[329]
  PIN out_block_o[32]
    DIRECTION OUTPUT ;
    USE SIGNAL ;
    PORT
      LAYER Metal3 ;
        RECT  899.6 128.74 900 129.14 ;
    END
  END out_block_o[32]
  PIN out_block_o[330]
    DIRECTION OUTPUT ;
    USE SIGNAL ;
    PORT
      LAYER Metal3 ;
        RECT  899.6 629.38 900 629.78 ;
    END
  END out_block_o[330]
  PIN out_block_o[331]
    DIRECTION OUTPUT ;
    USE SIGNAL ;
    PORT
      LAYER Metal3 ;
        RECT  899.6 631.06 900 631.46 ;
    END
  END out_block_o[331]
  PIN out_block_o[332]
    DIRECTION OUTPUT ;
    USE SIGNAL ;
    PORT
      LAYER Metal3 ;
        RECT  899.6 632.74 900 633.14 ;
    END
  END out_block_o[332]
  PIN out_block_o[333]
    DIRECTION OUTPUT ;
    USE SIGNAL ;
    PORT
      LAYER Metal3 ;
        RECT  899.6 634.42 900 634.82 ;
    END
  END out_block_o[333]
  PIN out_block_o[334]
    DIRECTION OUTPUT ;
    USE SIGNAL ;
    PORT
      LAYER Metal3 ;
        RECT  899.6 636.1 900 636.5 ;
    END
  END out_block_o[334]
  PIN out_block_o[335]
    DIRECTION OUTPUT ;
    USE SIGNAL ;
    PORT
      LAYER Metal3 ;
        RECT  899.6 637.78 900 638.18 ;
    END
  END out_block_o[335]
  PIN out_block_o[336]
    DIRECTION OUTPUT ;
    USE SIGNAL ;
    PORT
      LAYER Metal3 ;
        RECT  899.6 639.46 900 639.86 ;
    END
  END out_block_o[336]
  PIN out_block_o[337]
    DIRECTION OUTPUT ;
    USE SIGNAL ;
    PORT
      LAYER Metal3 ;
        RECT  899.6 641.14 900 641.54 ;
    END
  END out_block_o[337]
  PIN out_block_o[338]
    DIRECTION OUTPUT ;
    USE SIGNAL ;
    PORT
      LAYER Metal3 ;
        RECT  899.6 642.82 900 643.22 ;
    END
  END out_block_o[338]
  PIN out_block_o[339]
    DIRECTION OUTPUT ;
    USE SIGNAL ;
    PORT
      LAYER Metal3 ;
        RECT  899.6 644.5 900 644.9 ;
    END
  END out_block_o[339]
  PIN out_block_o[33]
    DIRECTION OUTPUT ;
    USE SIGNAL ;
    PORT
      LAYER Metal3 ;
        RECT  899.6 130.42 900 130.82 ;
    END
  END out_block_o[33]
  PIN out_block_o[340]
    DIRECTION OUTPUT ;
    USE SIGNAL ;
    PORT
      LAYER Metal3 ;
        RECT  899.6 646.18 900 646.58 ;
    END
  END out_block_o[340]
  PIN out_block_o[341]
    DIRECTION OUTPUT ;
    USE SIGNAL ;
    PORT
      LAYER Metal3 ;
        RECT  899.6 647.86 900 648.26 ;
    END
  END out_block_o[341]
  PIN out_block_o[342]
    DIRECTION OUTPUT ;
    USE SIGNAL ;
    PORT
      LAYER Metal3 ;
        RECT  899.6 649.54 900 649.94 ;
    END
  END out_block_o[342]
  PIN out_block_o[343]
    DIRECTION OUTPUT ;
    USE SIGNAL ;
    PORT
      LAYER Metal3 ;
        RECT  899.6 651.22 900 651.62 ;
    END
  END out_block_o[343]
  PIN out_block_o[344]
    DIRECTION OUTPUT ;
    USE SIGNAL ;
    PORT
      LAYER Metal3 ;
        RECT  899.6 652.9 900 653.3 ;
    END
  END out_block_o[344]
  PIN out_block_o[345]
    DIRECTION OUTPUT ;
    USE SIGNAL ;
    PORT
      LAYER Metal3 ;
        RECT  899.6 654.58 900 654.98 ;
    END
  END out_block_o[345]
  PIN out_block_o[346]
    DIRECTION OUTPUT ;
    USE SIGNAL ;
    PORT
      LAYER Metal3 ;
        RECT  899.6 656.26 900 656.66 ;
    END
  END out_block_o[346]
  PIN out_block_o[347]
    DIRECTION OUTPUT ;
    USE SIGNAL ;
    PORT
      LAYER Metal3 ;
        RECT  899.6 657.94 900 658.34 ;
    END
  END out_block_o[347]
  PIN out_block_o[348]
    DIRECTION OUTPUT ;
    USE SIGNAL ;
    PORT
      LAYER Metal3 ;
        RECT  899.6 659.62 900 660.02 ;
    END
  END out_block_o[348]
  PIN out_block_o[349]
    DIRECTION OUTPUT ;
    USE SIGNAL ;
    PORT
      LAYER Metal3 ;
        RECT  899.6 661.3 900 661.7 ;
    END
  END out_block_o[349]
  PIN out_block_o[34]
    DIRECTION OUTPUT ;
    USE SIGNAL ;
    PORT
      LAYER Metal3 ;
        RECT  899.6 132.1 900 132.5 ;
    END
  END out_block_o[34]
  PIN out_block_o[350]
    DIRECTION OUTPUT ;
    USE SIGNAL ;
    PORT
      LAYER Metal3 ;
        RECT  899.6 662.98 900 663.38 ;
    END
  END out_block_o[350]
  PIN out_block_o[351]
    DIRECTION OUTPUT ;
    USE SIGNAL ;
    PORT
      LAYER Metal3 ;
        RECT  899.6 664.66 900 665.06 ;
    END
  END out_block_o[351]
  PIN out_block_o[352]
    DIRECTION OUTPUT ;
    USE SIGNAL ;
    PORT
      LAYER Metal3 ;
        RECT  899.6 666.34 900 666.74 ;
    END
  END out_block_o[352]
  PIN out_block_o[353]
    DIRECTION OUTPUT ;
    USE SIGNAL ;
    PORT
      LAYER Metal3 ;
        RECT  899.6 668.02 900 668.42 ;
    END
  END out_block_o[353]
  PIN out_block_o[354]
    DIRECTION OUTPUT ;
    USE SIGNAL ;
    PORT
      LAYER Metal3 ;
        RECT  899.6 669.7 900 670.1 ;
    END
  END out_block_o[354]
  PIN out_block_o[355]
    DIRECTION OUTPUT ;
    USE SIGNAL ;
    PORT
      LAYER Metal3 ;
        RECT  899.6 671.38 900 671.78 ;
    END
  END out_block_o[355]
  PIN out_block_o[356]
    DIRECTION OUTPUT ;
    USE SIGNAL ;
    PORT
      LAYER Metal3 ;
        RECT  899.6 673.06 900 673.46 ;
    END
  END out_block_o[356]
  PIN out_block_o[357]
    DIRECTION OUTPUT ;
    USE SIGNAL ;
    PORT
      LAYER Metal3 ;
        RECT  899.6 674.74 900 675.14 ;
    END
  END out_block_o[357]
  PIN out_block_o[358]
    DIRECTION OUTPUT ;
    USE SIGNAL ;
    PORT
      LAYER Metal3 ;
        RECT  899.6 676.42 900 676.82 ;
    END
  END out_block_o[358]
  PIN out_block_o[359]
    DIRECTION OUTPUT ;
    USE SIGNAL ;
    PORT
      LAYER Metal3 ;
        RECT  899.6 678.1 900 678.5 ;
    END
  END out_block_o[359]
  PIN out_block_o[35]
    DIRECTION OUTPUT ;
    USE SIGNAL ;
    PORT
      LAYER Metal3 ;
        RECT  899.6 133.78 900 134.18 ;
    END
  END out_block_o[35]
  PIN out_block_o[360]
    DIRECTION OUTPUT ;
    USE SIGNAL ;
    PORT
      LAYER Metal3 ;
        RECT  899.6 679.78 900 680.18 ;
    END
  END out_block_o[360]
  PIN out_block_o[361]
    DIRECTION OUTPUT ;
    USE SIGNAL ;
    PORT
      LAYER Metal3 ;
        RECT  899.6 681.46 900 681.86 ;
    END
  END out_block_o[361]
  PIN out_block_o[362]
    DIRECTION OUTPUT ;
    USE SIGNAL ;
    PORT
      LAYER Metal3 ;
        RECT  899.6 683.14 900 683.54 ;
    END
  END out_block_o[362]
  PIN out_block_o[363]
    DIRECTION OUTPUT ;
    USE SIGNAL ;
    PORT
      LAYER Metal3 ;
        RECT  899.6 684.82 900 685.22 ;
    END
  END out_block_o[363]
  PIN out_block_o[364]
    DIRECTION OUTPUT ;
    USE SIGNAL ;
    PORT
      LAYER Metal3 ;
        RECT  899.6 686.5 900 686.9 ;
    END
  END out_block_o[364]
  PIN out_block_o[365]
    DIRECTION OUTPUT ;
    USE SIGNAL ;
    PORT
      LAYER Metal3 ;
        RECT  899.6 688.18 900 688.58 ;
    END
  END out_block_o[365]
  PIN out_block_o[366]
    DIRECTION OUTPUT ;
    USE SIGNAL ;
    PORT
      LAYER Metal3 ;
        RECT  899.6 689.86 900 690.26 ;
    END
  END out_block_o[366]
  PIN out_block_o[367]
    DIRECTION OUTPUT ;
    USE SIGNAL ;
    PORT
      LAYER Metal3 ;
        RECT  899.6 691.54 900 691.94 ;
    END
  END out_block_o[367]
  PIN out_block_o[368]
    DIRECTION OUTPUT ;
    USE SIGNAL ;
    PORT
      LAYER Metal3 ;
        RECT  899.6 693.22 900 693.62 ;
    END
  END out_block_o[368]
  PIN out_block_o[369]
    DIRECTION OUTPUT ;
    USE SIGNAL ;
    PORT
      LAYER Metal3 ;
        RECT  899.6 694.9 900 695.3 ;
    END
  END out_block_o[369]
  PIN out_block_o[36]
    DIRECTION OUTPUT ;
    USE SIGNAL ;
    PORT
      LAYER Metal3 ;
        RECT  899.6 135.46 900 135.86 ;
    END
  END out_block_o[36]
  PIN out_block_o[370]
    DIRECTION OUTPUT ;
    USE SIGNAL ;
    PORT
      LAYER Metal3 ;
        RECT  899.6 696.58 900 696.98 ;
    END
  END out_block_o[370]
  PIN out_block_o[371]
    DIRECTION OUTPUT ;
    USE SIGNAL ;
    PORT
      LAYER Metal3 ;
        RECT  899.6 698.26 900 698.66 ;
    END
  END out_block_o[371]
  PIN out_block_o[372]
    DIRECTION OUTPUT ;
    USE SIGNAL ;
    PORT
      LAYER Metal3 ;
        RECT  899.6 699.94 900 700.34 ;
    END
  END out_block_o[372]
  PIN out_block_o[373]
    DIRECTION OUTPUT ;
    USE SIGNAL ;
    PORT
      LAYER Metal3 ;
        RECT  899.6 701.62 900 702.02 ;
    END
  END out_block_o[373]
  PIN out_block_o[374]
    DIRECTION OUTPUT ;
    USE SIGNAL ;
    PORT
      LAYER Metal3 ;
        RECT  899.6 703.3 900 703.7 ;
    END
  END out_block_o[374]
  PIN out_block_o[375]
    DIRECTION OUTPUT ;
    USE SIGNAL ;
    PORT
      LAYER Metal3 ;
        RECT  899.6 704.98 900 705.38 ;
    END
  END out_block_o[375]
  PIN out_block_o[376]
    DIRECTION OUTPUT ;
    USE SIGNAL ;
    PORT
      LAYER Metal3 ;
        RECT  899.6 706.66 900 707.06 ;
    END
  END out_block_o[376]
  PIN out_block_o[377]
    DIRECTION OUTPUT ;
    USE SIGNAL ;
    PORT
      LAYER Metal3 ;
        RECT  899.6 708.34 900 708.74 ;
    END
  END out_block_o[377]
  PIN out_block_o[378]
    DIRECTION OUTPUT ;
    USE SIGNAL ;
    PORT
      LAYER Metal3 ;
        RECT  899.6 710.02 900 710.42 ;
    END
  END out_block_o[378]
  PIN out_block_o[379]
    DIRECTION OUTPUT ;
    USE SIGNAL ;
    PORT
      LAYER Metal3 ;
        RECT  899.6 711.7 900 712.1 ;
    END
  END out_block_o[379]
  PIN out_block_o[37]
    DIRECTION OUTPUT ;
    USE SIGNAL ;
    PORT
      LAYER Metal3 ;
        RECT  899.6 137.14 900 137.54 ;
    END
  END out_block_o[37]
  PIN out_block_o[380]
    DIRECTION OUTPUT ;
    USE SIGNAL ;
    PORT
      LAYER Metal3 ;
        RECT  899.6 713.38 900 713.78 ;
    END
  END out_block_o[380]
  PIN out_block_o[381]
    DIRECTION OUTPUT ;
    USE SIGNAL ;
    PORT
      LAYER Metal3 ;
        RECT  899.6 715.06 900 715.46 ;
    END
  END out_block_o[381]
  PIN out_block_o[382]
    DIRECTION OUTPUT ;
    USE SIGNAL ;
    PORT
      LAYER Metal3 ;
        RECT  899.6 716.74 900 717.14 ;
    END
  END out_block_o[382]
  PIN out_block_o[383]
    DIRECTION OUTPUT ;
    USE SIGNAL ;
    PORT
      LAYER Metal3 ;
        RECT  899.6 718.42 900 718.82 ;
    END
  END out_block_o[383]
  PIN out_block_o[384]
    DIRECTION OUTPUT ;
    USE SIGNAL ;
    PORT
      LAYER Metal3 ;
        RECT  899.6 720.1 900 720.5 ;
    END
  END out_block_o[384]
  PIN out_block_o[385]
    DIRECTION OUTPUT ;
    USE SIGNAL ;
    PORT
      LAYER Metal3 ;
        RECT  899.6 721.78 900 722.18 ;
    END
  END out_block_o[385]
  PIN out_block_o[386]
    DIRECTION OUTPUT ;
    USE SIGNAL ;
    PORT
      LAYER Metal3 ;
        RECT  899.6 723.46 900 723.86 ;
    END
  END out_block_o[386]
  PIN out_block_o[387]
    DIRECTION OUTPUT ;
    USE SIGNAL ;
    PORT
      LAYER Metal3 ;
        RECT  899.6 725.14 900 725.54 ;
    END
  END out_block_o[387]
  PIN out_block_o[388]
    DIRECTION OUTPUT ;
    USE SIGNAL ;
    PORT
      LAYER Metal3 ;
        RECT  899.6 726.82 900 727.22 ;
    END
  END out_block_o[388]
  PIN out_block_o[389]
    DIRECTION OUTPUT ;
    USE SIGNAL ;
    PORT
      LAYER Metal3 ;
        RECT  899.6 728.5 900 728.9 ;
    END
  END out_block_o[389]
  PIN out_block_o[38]
    DIRECTION OUTPUT ;
    USE SIGNAL ;
    PORT
      LAYER Metal3 ;
        RECT  899.6 138.82 900 139.22 ;
    END
  END out_block_o[38]
  PIN out_block_o[390]
    DIRECTION OUTPUT ;
    USE SIGNAL ;
    PORT
      LAYER Metal3 ;
        RECT  899.6 730.18 900 730.58 ;
    END
  END out_block_o[390]
  PIN out_block_o[391]
    DIRECTION OUTPUT ;
    USE SIGNAL ;
    PORT
      LAYER Metal3 ;
        RECT  899.6 731.86 900 732.26 ;
    END
  END out_block_o[391]
  PIN out_block_o[392]
    DIRECTION OUTPUT ;
    USE SIGNAL ;
    PORT
      LAYER Metal3 ;
        RECT  899.6 733.54 900 733.94 ;
    END
  END out_block_o[392]
  PIN out_block_o[393]
    DIRECTION OUTPUT ;
    USE SIGNAL ;
    PORT
      LAYER Metal3 ;
        RECT  899.6 735.22 900 735.62 ;
    END
  END out_block_o[393]
  PIN out_block_o[394]
    DIRECTION OUTPUT ;
    USE SIGNAL ;
    PORT
      LAYER Metal3 ;
        RECT  899.6 736.9 900 737.3 ;
    END
  END out_block_o[394]
  PIN out_block_o[395]
    DIRECTION OUTPUT ;
    USE SIGNAL ;
    PORT
      LAYER Metal3 ;
        RECT  899.6 738.58 900 738.98 ;
    END
  END out_block_o[395]
  PIN out_block_o[396]
    DIRECTION OUTPUT ;
    USE SIGNAL ;
    PORT
      LAYER Metal3 ;
        RECT  899.6 740.26 900 740.66 ;
    END
  END out_block_o[396]
  PIN out_block_o[397]
    DIRECTION OUTPUT ;
    USE SIGNAL ;
    PORT
      LAYER Metal3 ;
        RECT  899.6 741.94 900 742.34 ;
    END
  END out_block_o[397]
  PIN out_block_o[398]
    DIRECTION OUTPUT ;
    USE SIGNAL ;
    PORT
      LAYER Metal3 ;
        RECT  899.6 743.62 900 744.02 ;
    END
  END out_block_o[398]
  PIN out_block_o[399]
    DIRECTION OUTPUT ;
    USE SIGNAL ;
    PORT
      LAYER Metal3 ;
        RECT  899.6 745.3 900 745.7 ;
    END
  END out_block_o[399]
  PIN out_block_o[39]
    DIRECTION OUTPUT ;
    USE SIGNAL ;
    PORT
      LAYER Metal3 ;
        RECT  899.6 140.5 900 140.9 ;
    END
  END out_block_o[39]
  PIN out_block_o[3]
    DIRECTION OUTPUT ;
    USE SIGNAL ;
    PORT
      LAYER Metal3 ;
        RECT  899.6 80.02 900 80.42 ;
    END
  END out_block_o[3]
  PIN out_block_o[400]
    DIRECTION OUTPUT ;
    USE SIGNAL ;
    PORT
      LAYER Metal3 ;
        RECT  899.6 746.98 900 747.38 ;
    END
  END out_block_o[400]
  PIN out_block_o[401]
    DIRECTION OUTPUT ;
    USE SIGNAL ;
    PORT
      LAYER Metal3 ;
        RECT  899.6 748.66 900 749.06 ;
    END
  END out_block_o[401]
  PIN out_block_o[402]
    DIRECTION OUTPUT ;
    USE SIGNAL ;
    PORT
      LAYER Metal3 ;
        RECT  899.6 750.34 900 750.74 ;
    END
  END out_block_o[402]
  PIN out_block_o[403]
    DIRECTION OUTPUT ;
    USE SIGNAL ;
    PORT
      LAYER Metal3 ;
        RECT  899.6 752.02 900 752.42 ;
    END
  END out_block_o[403]
  PIN out_block_o[404]
    DIRECTION OUTPUT ;
    USE SIGNAL ;
    PORT
      LAYER Metal3 ;
        RECT  899.6 753.7 900 754.1 ;
    END
  END out_block_o[404]
  PIN out_block_o[405]
    DIRECTION OUTPUT ;
    USE SIGNAL ;
    PORT
      LAYER Metal3 ;
        RECT  899.6 755.38 900 755.78 ;
    END
  END out_block_o[405]
  PIN out_block_o[406]
    DIRECTION OUTPUT ;
    USE SIGNAL ;
    PORT
      LAYER Metal3 ;
        RECT  899.6 757.06 900 757.46 ;
    END
  END out_block_o[406]
  PIN out_block_o[407]
    DIRECTION OUTPUT ;
    USE SIGNAL ;
    PORT
      LAYER Metal3 ;
        RECT  899.6 758.74 900 759.14 ;
    END
  END out_block_o[407]
  PIN out_block_o[408]
    DIRECTION OUTPUT ;
    USE SIGNAL ;
    PORT
      LAYER Metal3 ;
        RECT  899.6 760.42 900 760.82 ;
    END
  END out_block_o[408]
  PIN out_block_o[409]
    DIRECTION OUTPUT ;
    USE SIGNAL ;
    PORT
      LAYER Metal3 ;
        RECT  899.6 762.1 900 762.5 ;
    END
  END out_block_o[409]
  PIN out_block_o[40]
    DIRECTION OUTPUT ;
    USE SIGNAL ;
    PORT
      LAYER Metal3 ;
        RECT  899.6 142.18 900 142.58 ;
    END
  END out_block_o[40]
  PIN out_block_o[410]
    DIRECTION OUTPUT ;
    USE SIGNAL ;
    PORT
      LAYER Metal3 ;
        RECT  899.6 763.78 900 764.18 ;
    END
  END out_block_o[410]
  PIN out_block_o[411]
    DIRECTION OUTPUT ;
    USE SIGNAL ;
    PORT
      LAYER Metal3 ;
        RECT  899.6 765.46 900 765.86 ;
    END
  END out_block_o[411]
  PIN out_block_o[412]
    DIRECTION OUTPUT ;
    USE SIGNAL ;
    PORT
      LAYER Metal3 ;
        RECT  899.6 767.14 900 767.54 ;
    END
  END out_block_o[412]
  PIN out_block_o[413]
    DIRECTION OUTPUT ;
    USE SIGNAL ;
    PORT
      LAYER Metal3 ;
        RECT  899.6 768.82 900 769.22 ;
    END
  END out_block_o[413]
  PIN out_block_o[414]
    DIRECTION OUTPUT ;
    USE SIGNAL ;
    PORT
      LAYER Metal3 ;
        RECT  899.6 770.5 900 770.9 ;
    END
  END out_block_o[414]
  PIN out_block_o[415]
    DIRECTION OUTPUT ;
    USE SIGNAL ;
    PORT
      LAYER Metal3 ;
        RECT  899.6 772.18 900 772.58 ;
    END
  END out_block_o[415]
  PIN out_block_o[416]
    DIRECTION OUTPUT ;
    USE SIGNAL ;
    PORT
      LAYER Metal3 ;
        RECT  899.6 773.86 900 774.26 ;
    END
  END out_block_o[416]
  PIN out_block_o[417]
    DIRECTION OUTPUT ;
    USE SIGNAL ;
    PORT
      LAYER Metal3 ;
        RECT  899.6 775.54 900 775.94 ;
    END
  END out_block_o[417]
  PIN out_block_o[418]
    DIRECTION OUTPUT ;
    USE SIGNAL ;
    PORT
      LAYER Metal3 ;
        RECT  899.6 777.22 900 777.62 ;
    END
  END out_block_o[418]
  PIN out_block_o[419]
    DIRECTION OUTPUT ;
    USE SIGNAL ;
    PORT
      LAYER Metal3 ;
        RECT  899.6 778.9 900 779.3 ;
    END
  END out_block_o[419]
  PIN out_block_o[41]
    DIRECTION OUTPUT ;
    USE SIGNAL ;
    PORT
      LAYER Metal3 ;
        RECT  899.6 143.86 900 144.26 ;
    END
  END out_block_o[41]
  PIN out_block_o[420]
    DIRECTION OUTPUT ;
    USE SIGNAL ;
    PORT
      LAYER Metal3 ;
        RECT  899.6 780.58 900 780.98 ;
    END
  END out_block_o[420]
  PIN out_block_o[421]
    DIRECTION OUTPUT ;
    USE SIGNAL ;
    PORT
      LAYER Metal3 ;
        RECT  899.6 782.26 900 782.66 ;
    END
  END out_block_o[421]
  PIN out_block_o[422]
    DIRECTION OUTPUT ;
    USE SIGNAL ;
    PORT
      LAYER Metal3 ;
        RECT  899.6 783.94 900 784.34 ;
    END
  END out_block_o[422]
  PIN out_block_o[423]
    DIRECTION OUTPUT ;
    USE SIGNAL ;
    PORT
      LAYER Metal3 ;
        RECT  899.6 785.62 900 786.02 ;
    END
  END out_block_o[423]
  PIN out_block_o[424]
    DIRECTION OUTPUT ;
    USE SIGNAL ;
    PORT
      LAYER Metal3 ;
        RECT  899.6 787.3 900 787.7 ;
    END
  END out_block_o[424]
  PIN out_block_o[425]
    DIRECTION OUTPUT ;
    USE SIGNAL ;
    PORT
      LAYER Metal3 ;
        RECT  899.6 788.98 900 789.38 ;
    END
  END out_block_o[425]
  PIN out_block_o[426]
    DIRECTION OUTPUT ;
    USE SIGNAL ;
    PORT
      LAYER Metal3 ;
        RECT  899.6 790.66 900 791.06 ;
    END
  END out_block_o[426]
  PIN out_block_o[427]
    DIRECTION OUTPUT ;
    USE SIGNAL ;
    PORT
      LAYER Metal3 ;
        RECT  899.6 792.34 900 792.74 ;
    END
  END out_block_o[427]
  PIN out_block_o[428]
    DIRECTION OUTPUT ;
    USE SIGNAL ;
    PORT
      LAYER Metal3 ;
        RECT  899.6 794.02 900 794.42 ;
    END
  END out_block_o[428]
  PIN out_block_o[429]
    DIRECTION OUTPUT ;
    USE SIGNAL ;
    PORT
      LAYER Metal3 ;
        RECT  899.6 795.7 900 796.1 ;
    END
  END out_block_o[429]
  PIN out_block_o[42]
    DIRECTION OUTPUT ;
    USE SIGNAL ;
    PORT
      LAYER Metal3 ;
        RECT  899.6 145.54 900 145.94 ;
    END
  END out_block_o[42]
  PIN out_block_o[430]
    DIRECTION OUTPUT ;
    USE SIGNAL ;
    PORT
      LAYER Metal3 ;
        RECT  899.6 797.38 900 797.78 ;
    END
  END out_block_o[430]
  PIN out_block_o[431]
    DIRECTION OUTPUT ;
    USE SIGNAL ;
    PORT
      LAYER Metal3 ;
        RECT  899.6 799.06 900 799.46 ;
    END
  END out_block_o[431]
  PIN out_block_o[432]
    DIRECTION OUTPUT ;
    USE SIGNAL ;
    PORT
      LAYER Metal3 ;
        RECT  899.6 800.74 900 801.14 ;
    END
  END out_block_o[432]
  PIN out_block_o[433]
    DIRECTION OUTPUT ;
    USE SIGNAL ;
    PORT
      LAYER Metal3 ;
        RECT  899.6 802.42 900 802.82 ;
    END
  END out_block_o[433]
  PIN out_block_o[434]
    DIRECTION OUTPUT ;
    USE SIGNAL ;
    PORT
      LAYER Metal3 ;
        RECT  899.6 804.1 900 804.5 ;
    END
  END out_block_o[434]
  PIN out_block_o[435]
    DIRECTION OUTPUT ;
    USE SIGNAL ;
    PORT
      LAYER Metal3 ;
        RECT  899.6 805.78 900 806.18 ;
    END
  END out_block_o[435]
  PIN out_block_o[436]
    DIRECTION OUTPUT ;
    USE SIGNAL ;
    PORT
      LAYER Metal3 ;
        RECT  899.6 807.46 900 807.86 ;
    END
  END out_block_o[436]
  PIN out_block_o[437]
    DIRECTION OUTPUT ;
    USE SIGNAL ;
    PORT
      LAYER Metal3 ;
        RECT  899.6 809.14 900 809.54 ;
    END
  END out_block_o[437]
  PIN out_block_o[438]
    DIRECTION OUTPUT ;
    USE SIGNAL ;
    PORT
      LAYER Metal3 ;
        RECT  899.6 810.82 900 811.22 ;
    END
  END out_block_o[438]
  PIN out_block_o[439]
    DIRECTION OUTPUT ;
    USE SIGNAL ;
    PORT
      LAYER Metal3 ;
        RECT  899.6 812.5 900 812.9 ;
    END
  END out_block_o[439]
  PIN out_block_o[43]
    DIRECTION OUTPUT ;
    USE SIGNAL ;
    PORT
      LAYER Metal3 ;
        RECT  899.6 147.22 900 147.62 ;
    END
  END out_block_o[43]
  PIN out_block_o[440]
    DIRECTION OUTPUT ;
    USE SIGNAL ;
    PORT
      LAYER Metal3 ;
        RECT  899.6 814.18 900 814.58 ;
    END
  END out_block_o[440]
  PIN out_block_o[441]
    DIRECTION OUTPUT ;
    USE SIGNAL ;
    PORT
      LAYER Metal3 ;
        RECT  899.6 815.86 900 816.26 ;
    END
  END out_block_o[441]
  PIN out_block_o[442]
    DIRECTION OUTPUT ;
    USE SIGNAL ;
    PORT
      LAYER Metal3 ;
        RECT  899.6 817.54 900 817.94 ;
    END
  END out_block_o[442]
  PIN out_block_o[443]
    DIRECTION OUTPUT ;
    USE SIGNAL ;
    PORT
      LAYER Metal3 ;
        RECT  899.6 819.22 900 819.62 ;
    END
  END out_block_o[443]
  PIN out_block_o[444]
    DIRECTION OUTPUT ;
    USE SIGNAL ;
    PORT
      LAYER Metal3 ;
        RECT  899.6 820.9 900 821.3 ;
    END
  END out_block_o[444]
  PIN out_block_o[445]
    DIRECTION OUTPUT ;
    USE SIGNAL ;
    PORT
      LAYER Metal3 ;
        RECT  899.6 822.58 900 822.98 ;
    END
  END out_block_o[445]
  PIN out_block_o[446]
    DIRECTION OUTPUT ;
    USE SIGNAL ;
    PORT
      LAYER Metal3 ;
        RECT  899.6 824.26 900 824.66 ;
    END
  END out_block_o[446]
  PIN out_block_o[447]
    DIRECTION OUTPUT ;
    USE SIGNAL ;
    PORT
      LAYER Metal3 ;
        RECT  899.6 825.94 900 826.34 ;
    END
  END out_block_o[447]
  PIN out_block_o[448]
    DIRECTION OUTPUT ;
    USE SIGNAL ;
    PORT
      LAYER Metal3 ;
        RECT  899.6 827.62 900 828.02 ;
    END
  END out_block_o[448]
  PIN out_block_o[449]
    DIRECTION OUTPUT ;
    USE SIGNAL ;
    PORT
      LAYER Metal3 ;
        RECT  899.6 829.3 900 829.7 ;
    END
  END out_block_o[449]
  PIN out_block_o[44]
    DIRECTION OUTPUT ;
    USE SIGNAL ;
    PORT
      LAYER Metal3 ;
        RECT  899.6 148.9 900 149.3 ;
    END
  END out_block_o[44]
  PIN out_block_o[450]
    DIRECTION OUTPUT ;
    USE SIGNAL ;
    PORT
      LAYER Metal3 ;
        RECT  899.6 830.98 900 831.38 ;
    END
  END out_block_o[450]
  PIN out_block_o[451]
    DIRECTION OUTPUT ;
    USE SIGNAL ;
    PORT
      LAYER Metal3 ;
        RECT  899.6 832.66 900 833.06 ;
    END
  END out_block_o[451]
  PIN out_block_o[452]
    DIRECTION OUTPUT ;
    USE SIGNAL ;
    PORT
      LAYER Metal3 ;
        RECT  899.6 834.34 900 834.74 ;
    END
  END out_block_o[452]
  PIN out_block_o[453]
    DIRECTION OUTPUT ;
    USE SIGNAL ;
    PORT
      LAYER Metal3 ;
        RECT  899.6 836.02 900 836.42 ;
    END
  END out_block_o[453]
  PIN out_block_o[454]
    DIRECTION OUTPUT ;
    USE SIGNAL ;
    PORT
      LAYER Metal3 ;
        RECT  899.6 837.7 900 838.1 ;
    END
  END out_block_o[454]
  PIN out_block_o[455]
    DIRECTION OUTPUT ;
    USE SIGNAL ;
    PORT
      LAYER Metal3 ;
        RECT  899.6 839.38 900 839.78 ;
    END
  END out_block_o[455]
  PIN out_block_o[456]
    DIRECTION OUTPUT ;
    USE SIGNAL ;
    PORT
      LAYER Metal3 ;
        RECT  899.6 841.06 900 841.46 ;
    END
  END out_block_o[456]
  PIN out_block_o[457]
    DIRECTION OUTPUT ;
    USE SIGNAL ;
    PORT
      LAYER Metal3 ;
        RECT  899.6 842.74 900 843.14 ;
    END
  END out_block_o[457]
  PIN out_block_o[458]
    DIRECTION OUTPUT ;
    USE SIGNAL ;
    PORT
      LAYER Metal3 ;
        RECT  899.6 844.42 900 844.82 ;
    END
  END out_block_o[458]
  PIN out_block_o[459]
    DIRECTION OUTPUT ;
    USE SIGNAL ;
    PORT
      LAYER Metal3 ;
        RECT  899.6 846.1 900 846.5 ;
    END
  END out_block_o[459]
  PIN out_block_o[45]
    DIRECTION OUTPUT ;
    USE SIGNAL ;
    PORT
      LAYER Metal3 ;
        RECT  899.6 150.58 900 150.98 ;
    END
  END out_block_o[45]
  PIN out_block_o[460]
    DIRECTION OUTPUT ;
    USE SIGNAL ;
    PORT
      LAYER Metal3 ;
        RECT  899.6 847.78 900 848.18 ;
    END
  END out_block_o[460]
  PIN out_block_o[461]
    DIRECTION OUTPUT ;
    USE SIGNAL ;
    PORT
      LAYER Metal3 ;
        RECT  899.6 849.46 900 849.86 ;
    END
  END out_block_o[461]
  PIN out_block_o[462]
    DIRECTION OUTPUT ;
    USE SIGNAL ;
    PORT
      LAYER Metal3 ;
        RECT  899.6 851.14 900 851.54 ;
    END
  END out_block_o[462]
  PIN out_block_o[463]
    DIRECTION OUTPUT ;
    USE SIGNAL ;
    PORT
      LAYER Metal3 ;
        RECT  899.6 852.82 900 853.22 ;
    END
  END out_block_o[463]
  PIN out_block_o[464]
    DIRECTION OUTPUT ;
    USE SIGNAL ;
    PORT
      LAYER Metal3 ;
        RECT  899.6 854.5 900 854.9 ;
    END
  END out_block_o[464]
  PIN out_block_o[465]
    DIRECTION OUTPUT ;
    USE SIGNAL ;
    PORT
      LAYER Metal3 ;
        RECT  899.6 856.18 900 856.58 ;
    END
  END out_block_o[465]
  PIN out_block_o[466]
    DIRECTION OUTPUT ;
    USE SIGNAL ;
    PORT
      LAYER Metal3 ;
        RECT  899.6 857.86 900 858.26 ;
    END
  END out_block_o[466]
  PIN out_block_o[467]
    DIRECTION OUTPUT ;
    USE SIGNAL ;
    PORT
      LAYER Metal3 ;
        RECT  899.6 859.54 900 859.94 ;
    END
  END out_block_o[467]
  PIN out_block_o[468]
    DIRECTION OUTPUT ;
    USE SIGNAL ;
    PORT
      LAYER Metal3 ;
        RECT  899.6 861.22 900 861.62 ;
    END
  END out_block_o[468]
  PIN out_block_o[469]
    DIRECTION OUTPUT ;
    USE SIGNAL ;
    PORT
      LAYER Metal3 ;
        RECT  899.6 862.9 900 863.3 ;
    END
  END out_block_o[469]
  PIN out_block_o[46]
    DIRECTION OUTPUT ;
    USE SIGNAL ;
    PORT
      LAYER Metal3 ;
        RECT  899.6 152.26 900 152.66 ;
    END
  END out_block_o[46]
  PIN out_block_o[470]
    DIRECTION OUTPUT ;
    USE SIGNAL ;
    PORT
      LAYER Metal3 ;
        RECT  899.6 864.58 900 864.98 ;
    END
  END out_block_o[470]
  PIN out_block_o[471]
    DIRECTION OUTPUT ;
    USE SIGNAL ;
    PORT
      LAYER Metal3 ;
        RECT  899.6 866.26 900 866.66 ;
    END
  END out_block_o[471]
  PIN out_block_o[472]
    DIRECTION OUTPUT ;
    USE SIGNAL ;
    PORT
      LAYER Metal3 ;
        RECT  899.6 867.94 900 868.34 ;
    END
  END out_block_o[472]
  PIN out_block_o[473]
    DIRECTION OUTPUT ;
    USE SIGNAL ;
    PORT
      LAYER Metal3 ;
        RECT  899.6 869.62 900 870.02 ;
    END
  END out_block_o[473]
  PIN out_block_o[474]
    DIRECTION OUTPUT ;
    USE SIGNAL ;
    PORT
      LAYER Metal3 ;
        RECT  899.6 871.3 900 871.7 ;
    END
  END out_block_o[474]
  PIN out_block_o[475]
    DIRECTION OUTPUT ;
    USE SIGNAL ;
    PORT
      LAYER Metal3 ;
        RECT  899.6 872.98 900 873.38 ;
    END
  END out_block_o[475]
  PIN out_block_o[476]
    DIRECTION OUTPUT ;
    USE SIGNAL ;
    PORT
      LAYER Metal3 ;
        RECT  899.6 874.66 900 875.06 ;
    END
  END out_block_o[476]
  PIN out_block_o[477]
    DIRECTION OUTPUT ;
    USE SIGNAL ;
    PORT
      LAYER Metal3 ;
        RECT  899.6 876.34 900 876.74 ;
    END
  END out_block_o[477]
  PIN out_block_o[478]
    DIRECTION OUTPUT ;
    USE SIGNAL ;
    PORT
      LAYER Metal3 ;
        RECT  899.6 878.02 900 878.42 ;
    END
  END out_block_o[478]
  PIN out_block_o[479]
    DIRECTION OUTPUT ;
    USE SIGNAL ;
    PORT
      LAYER Metal3 ;
        RECT  899.6 879.7 900 880.1 ;
    END
  END out_block_o[479]
  PIN out_block_o[47]
    DIRECTION OUTPUT ;
    USE SIGNAL ;
    PORT
      LAYER Metal3 ;
        RECT  899.6 153.94 900 154.34 ;
    END
  END out_block_o[47]
  PIN out_block_o[480]
    DIRECTION OUTPUT ;
    USE SIGNAL ;
    PORT
      LAYER Metal3 ;
        RECT  899.6 881.38 900 881.78 ;
    END
  END out_block_o[480]
  PIN out_block_o[481]
    DIRECTION OUTPUT ;
    USE SIGNAL ;
    PORT
      LAYER Metal3 ;
        RECT  899.6 883.06 900 883.46 ;
    END
  END out_block_o[481]
  PIN out_block_o[482]
    DIRECTION OUTPUT ;
    USE SIGNAL ;
    PORT
      LAYER Metal3 ;
        RECT  899.6 884.74 900 885.14 ;
    END
  END out_block_o[482]
  PIN out_block_o[483]
    DIRECTION OUTPUT ;
    USE SIGNAL ;
    PORT
      LAYER Metal3 ;
        RECT  899.6 886.42 900 886.82 ;
    END
  END out_block_o[483]
  PIN out_block_o[484]
    DIRECTION OUTPUT ;
    USE SIGNAL ;
    PORT
      LAYER Metal3 ;
        RECT  899.6 888.1 900 888.5 ;
    END
  END out_block_o[484]
  PIN out_block_o[485]
    DIRECTION OUTPUT ;
    USE SIGNAL ;
    PORT
      LAYER Metal3 ;
        RECT  899.6 889.78 900 890.18 ;
    END
  END out_block_o[485]
  PIN out_block_o[486]
    DIRECTION OUTPUT ;
    USE SIGNAL ;
    PORT
      LAYER Metal3 ;
        RECT  899.6 891.46 900 891.86 ;
    END
  END out_block_o[486]
  PIN out_block_o[487]
    DIRECTION OUTPUT ;
    USE SIGNAL ;
    PORT
      LAYER Metal3 ;
        RECT  899.6 893.14 900 893.54 ;
    END
  END out_block_o[487]
  PIN out_block_o[488]
    DIRECTION OUTPUT ;
    USE SIGNAL ;
    PORT
      LAYER Metal3 ;
        RECT  899.6 894.82 900 895.22 ;
    END
  END out_block_o[488]
  PIN out_block_o[489]
    DIRECTION OUTPUT ;
    USE SIGNAL ;
    PORT
      LAYER Metal3 ;
        RECT  899.6 896.5 900 896.9 ;
    END
  END out_block_o[489]
  PIN out_block_o[48]
    DIRECTION OUTPUT ;
    USE SIGNAL ;
    PORT
      LAYER Metal3 ;
        RECT  899.6 155.62 900 156.02 ;
    END
  END out_block_o[48]
  PIN out_block_o[490]
    DIRECTION OUTPUT ;
    USE SIGNAL ;
    PORT
      LAYER Metal3 ;
        RECT  899.6 898.18 900 898.58 ;
    END
  END out_block_o[490]
  PIN out_block_o[491]
    DIRECTION OUTPUT ;
    USE SIGNAL ;
    PORT
      LAYER Metal3 ;
        RECT  899.6 899.86 900 900.26 ;
    END
  END out_block_o[491]
  PIN out_block_o[492]
    DIRECTION OUTPUT ;
    USE SIGNAL ;
    PORT
      LAYER Metal3 ;
        RECT  899.6 901.54 900 901.94 ;
    END
  END out_block_o[492]
  PIN out_block_o[493]
    DIRECTION OUTPUT ;
    USE SIGNAL ;
    PORT
      LAYER Metal3 ;
        RECT  899.6 903.22 900 903.62 ;
    END
  END out_block_o[493]
  PIN out_block_o[494]
    DIRECTION OUTPUT ;
    USE SIGNAL ;
    PORT
      LAYER Metal3 ;
        RECT  899.6 904.9 900 905.3 ;
    END
  END out_block_o[494]
  PIN out_block_o[495]
    DIRECTION OUTPUT ;
    USE SIGNAL ;
    PORT
      LAYER Metal3 ;
        RECT  899.6 906.58 900 906.98 ;
    END
  END out_block_o[495]
  PIN out_block_o[496]
    DIRECTION OUTPUT ;
    USE SIGNAL ;
    PORT
      LAYER Metal3 ;
        RECT  899.6 908.26 900 908.66 ;
    END
  END out_block_o[496]
  PIN out_block_o[497]
    DIRECTION OUTPUT ;
    USE SIGNAL ;
    PORT
      LAYER Metal3 ;
        RECT  899.6 909.94 900 910.34 ;
    END
  END out_block_o[497]
  PIN out_block_o[498]
    DIRECTION OUTPUT ;
    USE SIGNAL ;
    PORT
      LAYER Metal3 ;
        RECT  899.6 911.62 900 912.02 ;
    END
  END out_block_o[498]
  PIN out_block_o[499]
    DIRECTION OUTPUT ;
    USE SIGNAL ;
    PORT
      LAYER Metal3 ;
        RECT  899.6 913.3 900 913.7 ;
    END
  END out_block_o[499]
  PIN out_block_o[49]
    DIRECTION OUTPUT ;
    USE SIGNAL ;
    PORT
      LAYER Metal3 ;
        RECT  899.6 157.3 900 157.7 ;
    END
  END out_block_o[49]
  PIN out_block_o[4]
    DIRECTION OUTPUT ;
    USE SIGNAL ;
    PORT
      LAYER Metal3 ;
        RECT  899.6 81.7 900 82.1 ;
    END
  END out_block_o[4]
  PIN out_block_o[500]
    DIRECTION OUTPUT ;
    USE SIGNAL ;
    PORT
      LAYER Metal3 ;
        RECT  899.6 914.98 900 915.38 ;
    END
  END out_block_o[500]
  PIN out_block_o[501]
    DIRECTION OUTPUT ;
    USE SIGNAL ;
    PORT
      LAYER Metal3 ;
        RECT  899.6 916.66 900 917.06 ;
    END
  END out_block_o[501]
  PIN out_block_o[502]
    DIRECTION OUTPUT ;
    USE SIGNAL ;
    PORT
      LAYER Metal3 ;
        RECT  899.6 918.34 900 918.74 ;
    END
  END out_block_o[502]
  PIN out_block_o[503]
    DIRECTION OUTPUT ;
    USE SIGNAL ;
    PORT
      LAYER Metal3 ;
        RECT  899.6 920.02 900 920.42 ;
    END
  END out_block_o[503]
  PIN out_block_o[504]
    DIRECTION OUTPUT ;
    USE SIGNAL ;
    PORT
      LAYER Metal3 ;
        RECT  899.6 921.7 900 922.1 ;
    END
  END out_block_o[504]
  PIN out_block_o[505]
    DIRECTION OUTPUT ;
    USE SIGNAL ;
    PORT
      LAYER Metal3 ;
        RECT  899.6 923.38 900 923.78 ;
    END
  END out_block_o[505]
  PIN out_block_o[506]
    DIRECTION OUTPUT ;
    USE SIGNAL ;
    PORT
      LAYER Metal3 ;
        RECT  899.6 925.06 900 925.46 ;
    END
  END out_block_o[506]
  PIN out_block_o[507]
    DIRECTION OUTPUT ;
    USE SIGNAL ;
    PORT
      LAYER Metal3 ;
        RECT  899.6 926.74 900 927.14 ;
    END
  END out_block_o[507]
  PIN out_block_o[508]
    DIRECTION OUTPUT ;
    USE SIGNAL ;
    PORT
      LAYER Metal3 ;
        RECT  899.6 928.42 900 928.82 ;
    END
  END out_block_o[508]
  PIN out_block_o[509]
    DIRECTION OUTPUT ;
    USE SIGNAL ;
    PORT
      LAYER Metal3 ;
        RECT  899.6 930.1 900 930.5 ;
    END
  END out_block_o[509]
  PIN out_block_o[50]
    DIRECTION OUTPUT ;
    USE SIGNAL ;
    PORT
      LAYER Metal3 ;
        RECT  899.6 158.98 900 159.38 ;
    END
  END out_block_o[50]
  PIN out_block_o[510]
    DIRECTION OUTPUT ;
    USE SIGNAL ;
    PORT
      LAYER Metal3 ;
        RECT  899.6 931.78 900 932.18 ;
    END
  END out_block_o[510]
  PIN out_block_o[511]
    DIRECTION OUTPUT ;
    USE SIGNAL ;
    PORT
      LAYER Metal3 ;
        RECT  899.6 933.46 900 933.86 ;
    END
  END out_block_o[511]
  PIN out_block_o[512]
    DIRECTION OUTPUT ;
    USE SIGNAL ;
    PORT
      LAYER Metal3 ;
        RECT  899.6 935.14 900 935.54 ;
    END
  END out_block_o[512]
  PIN out_block_o[513]
    DIRECTION OUTPUT ;
    USE SIGNAL ;
    PORT
      LAYER Metal3 ;
        RECT  899.6 936.82 900 937.22 ;
    END
  END out_block_o[513]
  PIN out_block_o[514]
    DIRECTION OUTPUT ;
    USE SIGNAL ;
    PORT
      LAYER Metal3 ;
        RECT  899.6 938.5 900 938.9 ;
    END
  END out_block_o[514]
  PIN out_block_o[515]
    DIRECTION OUTPUT ;
    USE SIGNAL ;
    PORT
      LAYER Metal3 ;
        RECT  899.6 940.18 900 940.58 ;
    END
  END out_block_o[515]
  PIN out_block_o[516]
    DIRECTION OUTPUT ;
    USE SIGNAL ;
    PORT
      LAYER Metal3 ;
        RECT  899.6 941.86 900 942.26 ;
    END
  END out_block_o[516]
  PIN out_block_o[517]
    DIRECTION OUTPUT ;
    USE SIGNAL ;
    PORT
      LAYER Metal3 ;
        RECT  899.6 943.54 900 943.94 ;
    END
  END out_block_o[517]
  PIN out_block_o[518]
    DIRECTION OUTPUT ;
    USE SIGNAL ;
    PORT
      LAYER Metal3 ;
        RECT  899.6 945.22 900 945.62 ;
    END
  END out_block_o[518]
  PIN out_block_o[519]
    DIRECTION OUTPUT ;
    USE SIGNAL ;
    PORT
      LAYER Metal3 ;
        RECT  899.6 946.9 900 947.3 ;
    END
  END out_block_o[519]
  PIN out_block_o[51]
    DIRECTION OUTPUT ;
    USE SIGNAL ;
    PORT
      LAYER Metal3 ;
        RECT  899.6 160.66 900 161.06 ;
    END
  END out_block_o[51]
  PIN out_block_o[520]
    DIRECTION OUTPUT ;
    USE SIGNAL ;
    PORT
      LAYER Metal3 ;
        RECT  899.6 948.58 900 948.98 ;
    END
  END out_block_o[520]
  PIN out_block_o[521]
    DIRECTION OUTPUT ;
    USE SIGNAL ;
    PORT
      LAYER Metal3 ;
        RECT  899.6 950.26 900 950.66 ;
    END
  END out_block_o[521]
  PIN out_block_o[522]
    DIRECTION OUTPUT ;
    USE SIGNAL ;
    PORT
      LAYER Metal3 ;
        RECT  899.6 951.94 900 952.34 ;
    END
  END out_block_o[522]
  PIN out_block_o[523]
    DIRECTION OUTPUT ;
    USE SIGNAL ;
    PORT
      LAYER Metal3 ;
        RECT  899.6 953.62 900 954.02 ;
    END
  END out_block_o[523]
  PIN out_block_o[524]
    DIRECTION OUTPUT ;
    USE SIGNAL ;
    PORT
      LAYER Metal3 ;
        RECT  899.6 955.3 900 955.7 ;
    END
  END out_block_o[524]
  PIN out_block_o[525]
    DIRECTION OUTPUT ;
    USE SIGNAL ;
    PORT
      LAYER Metal3 ;
        RECT  899.6 956.98 900 957.38 ;
    END
  END out_block_o[525]
  PIN out_block_o[526]
    DIRECTION OUTPUT ;
    USE SIGNAL ;
    PORT
      LAYER Metal3 ;
        RECT  899.6 958.66 900 959.06 ;
    END
  END out_block_o[526]
  PIN out_block_o[527]
    DIRECTION OUTPUT ;
    USE SIGNAL ;
    PORT
      LAYER Metal3 ;
        RECT  899.6 960.34 900 960.74 ;
    END
  END out_block_o[527]
  PIN out_block_o[528]
    DIRECTION OUTPUT ;
    USE SIGNAL ;
    PORT
      LAYER Metal3 ;
        RECT  899.6 962.02 900 962.42 ;
    END
  END out_block_o[528]
  PIN out_block_o[529]
    DIRECTION OUTPUT ;
    USE SIGNAL ;
    PORT
      LAYER Metal3 ;
        RECT  899.6 963.7 900 964.1 ;
    END
  END out_block_o[529]
  PIN out_block_o[52]
    DIRECTION OUTPUT ;
    USE SIGNAL ;
    PORT
      LAYER Metal3 ;
        RECT  899.6 162.34 900 162.74 ;
    END
  END out_block_o[52]
  PIN out_block_o[530]
    DIRECTION OUTPUT ;
    USE SIGNAL ;
    PORT
      LAYER Metal3 ;
        RECT  899.6 965.38 900 965.78 ;
    END
  END out_block_o[530]
  PIN out_block_o[531]
    DIRECTION OUTPUT ;
    USE SIGNAL ;
    PORT
      LAYER Metal3 ;
        RECT  899.6 967.06 900 967.46 ;
    END
  END out_block_o[531]
  PIN out_block_o[532]
    DIRECTION OUTPUT ;
    USE SIGNAL ;
    PORT
      LAYER Metal3 ;
        RECT  899.6 968.74 900 969.14 ;
    END
  END out_block_o[532]
  PIN out_block_o[533]
    DIRECTION OUTPUT ;
    USE SIGNAL ;
    PORT
      LAYER Metal3 ;
        RECT  899.6 970.42 900 970.82 ;
    END
  END out_block_o[533]
  PIN out_block_o[534]
    DIRECTION OUTPUT ;
    USE SIGNAL ;
    PORT
      LAYER Metal3 ;
        RECT  899.6 972.1 900 972.5 ;
    END
  END out_block_o[534]
  PIN out_block_o[535]
    DIRECTION OUTPUT ;
    USE SIGNAL ;
    PORT
      LAYER Metal3 ;
        RECT  899.6 973.78 900 974.18 ;
    END
  END out_block_o[535]
  PIN out_block_o[536]
    DIRECTION OUTPUT ;
    USE SIGNAL ;
    PORT
      LAYER Metal3 ;
        RECT  899.6 975.46 900 975.86 ;
    END
  END out_block_o[536]
  PIN out_block_o[537]
    DIRECTION OUTPUT ;
    USE SIGNAL ;
    PORT
      LAYER Metal3 ;
        RECT  899.6 977.14 900 977.54 ;
    END
  END out_block_o[537]
  PIN out_block_o[538]
    DIRECTION OUTPUT ;
    USE SIGNAL ;
    PORT
      LAYER Metal3 ;
        RECT  899.6 978.82 900 979.22 ;
    END
  END out_block_o[538]
  PIN out_block_o[539]
    DIRECTION OUTPUT ;
    USE SIGNAL ;
    PORT
      LAYER Metal3 ;
        RECT  899.6 980.5 900 980.9 ;
    END
  END out_block_o[539]
  PIN out_block_o[53]
    DIRECTION OUTPUT ;
    USE SIGNAL ;
    PORT
      LAYER Metal3 ;
        RECT  899.6 164.02 900 164.42 ;
    END
  END out_block_o[53]
  PIN out_block_o[540]
    DIRECTION OUTPUT ;
    USE SIGNAL ;
    PORT
      LAYER Metal3 ;
        RECT  899.6 982.18 900 982.58 ;
    END
  END out_block_o[540]
  PIN out_block_o[541]
    DIRECTION OUTPUT ;
    USE SIGNAL ;
    PORT
      LAYER Metal3 ;
        RECT  899.6 983.86 900 984.26 ;
    END
  END out_block_o[541]
  PIN out_block_o[542]
    DIRECTION OUTPUT ;
    USE SIGNAL ;
    PORT
      LAYER Metal3 ;
        RECT  899.6 985.54 900 985.94 ;
    END
  END out_block_o[542]
  PIN out_block_o[543]
    DIRECTION OUTPUT ;
    USE SIGNAL ;
    PORT
      LAYER Metal3 ;
        RECT  899.6 987.22 900 987.62 ;
    END
  END out_block_o[543]
  PIN out_block_o[544]
    DIRECTION OUTPUT ;
    USE SIGNAL ;
    PORT
      LAYER Metal3 ;
        RECT  899.6 988.9 900 989.3 ;
    END
  END out_block_o[544]
  PIN out_block_o[545]
    DIRECTION OUTPUT ;
    USE SIGNAL ;
    PORT
      LAYER Metal3 ;
        RECT  899.6 990.58 900 990.98 ;
    END
  END out_block_o[545]
  PIN out_block_o[546]
    DIRECTION OUTPUT ;
    USE SIGNAL ;
    PORT
      LAYER Metal3 ;
        RECT  899.6 992.26 900 992.66 ;
    END
  END out_block_o[546]
  PIN out_block_o[547]
    DIRECTION OUTPUT ;
    USE SIGNAL ;
    PORT
      LAYER Metal3 ;
        RECT  899.6 993.94 900 994.34 ;
    END
  END out_block_o[547]
  PIN out_block_o[548]
    DIRECTION OUTPUT ;
    USE SIGNAL ;
    PORT
      LAYER Metal3 ;
        RECT  899.6 995.62 900 996.02 ;
    END
  END out_block_o[548]
  PIN out_block_o[549]
    DIRECTION OUTPUT ;
    USE SIGNAL ;
    PORT
      LAYER Metal3 ;
        RECT  899.6 997.3 900 997.7 ;
    END
  END out_block_o[549]
  PIN out_block_o[54]
    DIRECTION OUTPUT ;
    USE SIGNAL ;
    PORT
      LAYER Metal3 ;
        RECT  899.6 165.7 900 166.1 ;
    END
  END out_block_o[54]
  PIN out_block_o[550]
    DIRECTION OUTPUT ;
    USE SIGNAL ;
    PORT
      LAYER Metal3 ;
        RECT  899.6 998.98 900 999.38 ;
    END
  END out_block_o[550]
  PIN out_block_o[551]
    DIRECTION OUTPUT ;
    USE SIGNAL ;
    PORT
      LAYER Metal3 ;
        RECT  899.6 1000.66 900 1001.06 ;
    END
  END out_block_o[551]
  PIN out_block_o[552]
    DIRECTION OUTPUT ;
    USE SIGNAL ;
    PORT
      LAYER Metal3 ;
        RECT  899.6 1002.34 900 1002.74 ;
    END
  END out_block_o[552]
  PIN out_block_o[553]
    DIRECTION OUTPUT ;
    USE SIGNAL ;
    PORT
      LAYER Metal3 ;
        RECT  899.6 1004.02 900 1004.42 ;
    END
  END out_block_o[553]
  PIN out_block_o[554]
    DIRECTION OUTPUT ;
    USE SIGNAL ;
    PORT
      LAYER Metal3 ;
        RECT  899.6 1005.7 900 1006.1 ;
    END
  END out_block_o[554]
  PIN out_block_o[555]
    DIRECTION OUTPUT ;
    USE SIGNAL ;
    PORT
      LAYER Metal3 ;
        RECT  899.6 1007.38 900 1007.78 ;
    END
  END out_block_o[555]
  PIN out_block_o[556]
    DIRECTION OUTPUT ;
    USE SIGNAL ;
    PORT
      LAYER Metal3 ;
        RECT  899.6 1009.06 900 1009.46 ;
    END
  END out_block_o[556]
  PIN out_block_o[557]
    DIRECTION OUTPUT ;
    USE SIGNAL ;
    PORT
      LAYER Metal3 ;
        RECT  899.6 1010.74 900 1011.14 ;
    END
  END out_block_o[557]
  PIN out_block_o[558]
    DIRECTION OUTPUT ;
    USE SIGNAL ;
    PORT
      LAYER Metal3 ;
        RECT  899.6 1012.42 900 1012.82 ;
    END
  END out_block_o[558]
  PIN out_block_o[559]
    DIRECTION OUTPUT ;
    USE SIGNAL ;
    PORT
      LAYER Metal3 ;
        RECT  899.6 1014.1 900 1014.5 ;
    END
  END out_block_o[559]
  PIN out_block_o[55]
    DIRECTION OUTPUT ;
    USE SIGNAL ;
    PORT
      LAYER Metal3 ;
        RECT  899.6 167.38 900 167.78 ;
    END
  END out_block_o[55]
  PIN out_block_o[560]
    DIRECTION OUTPUT ;
    USE SIGNAL ;
    PORT
      LAYER Metal3 ;
        RECT  899.6 1015.78 900 1016.18 ;
    END
  END out_block_o[560]
  PIN out_block_o[561]
    DIRECTION OUTPUT ;
    USE SIGNAL ;
    PORT
      LAYER Metal3 ;
        RECT  899.6 1017.46 900 1017.86 ;
    END
  END out_block_o[561]
  PIN out_block_o[562]
    DIRECTION OUTPUT ;
    USE SIGNAL ;
    PORT
      LAYER Metal3 ;
        RECT  899.6 1019.14 900 1019.54 ;
    END
  END out_block_o[562]
  PIN out_block_o[563]
    DIRECTION OUTPUT ;
    USE SIGNAL ;
    PORT
      LAYER Metal3 ;
        RECT  899.6 1020.82 900 1021.22 ;
    END
  END out_block_o[563]
  PIN out_block_o[564]
    DIRECTION OUTPUT ;
    USE SIGNAL ;
    PORT
      LAYER Metal3 ;
        RECT  899.6 1022.5 900 1022.9 ;
    END
  END out_block_o[564]
  PIN out_block_o[565]
    DIRECTION OUTPUT ;
    USE SIGNAL ;
    PORT
      LAYER Metal3 ;
        RECT  899.6 1024.18 900 1024.58 ;
    END
  END out_block_o[565]
  PIN out_block_o[566]
    DIRECTION OUTPUT ;
    USE SIGNAL ;
    PORT
      LAYER Metal3 ;
        RECT  899.6 1025.86 900 1026.26 ;
    END
  END out_block_o[566]
  PIN out_block_o[567]
    DIRECTION OUTPUT ;
    USE SIGNAL ;
    PORT
      LAYER Metal3 ;
        RECT  899.6 1027.54 900 1027.94 ;
    END
  END out_block_o[567]
  PIN out_block_o[568]
    DIRECTION OUTPUT ;
    USE SIGNAL ;
    PORT
      LAYER Metal3 ;
        RECT  899.6 1029.22 900 1029.62 ;
    END
  END out_block_o[568]
  PIN out_block_o[569]
    DIRECTION OUTPUT ;
    USE SIGNAL ;
    PORT
      LAYER Metal3 ;
        RECT  899.6 1030.9 900 1031.3 ;
    END
  END out_block_o[569]
  PIN out_block_o[56]
    DIRECTION OUTPUT ;
    USE SIGNAL ;
    PORT
      LAYER Metal3 ;
        RECT  899.6 169.06 900 169.46 ;
    END
  END out_block_o[56]
  PIN out_block_o[570]
    DIRECTION OUTPUT ;
    USE SIGNAL ;
    PORT
      LAYER Metal3 ;
        RECT  899.6 1032.58 900 1032.98 ;
    END
  END out_block_o[570]
  PIN out_block_o[571]
    DIRECTION OUTPUT ;
    USE SIGNAL ;
    PORT
      LAYER Metal3 ;
        RECT  899.6 1034.26 900 1034.66 ;
    END
  END out_block_o[571]
  PIN out_block_o[57]
    DIRECTION OUTPUT ;
    USE SIGNAL ;
    PORT
      LAYER Metal3 ;
        RECT  899.6 170.74 900 171.14 ;
    END
  END out_block_o[57]
  PIN out_block_o[58]
    DIRECTION OUTPUT ;
    USE SIGNAL ;
    PORT
      LAYER Metal3 ;
        RECT  899.6 172.42 900 172.82 ;
    END
  END out_block_o[58]
  PIN out_block_o[59]
    DIRECTION OUTPUT ;
    USE SIGNAL ;
    PORT
      LAYER Metal3 ;
        RECT  899.6 174.1 900 174.5 ;
    END
  END out_block_o[59]
  PIN out_block_o[5]
    DIRECTION OUTPUT ;
    USE SIGNAL ;
    PORT
      LAYER Metal3 ;
        RECT  899.6 83.38 900 83.78 ;
    END
  END out_block_o[5]
  PIN out_block_o[60]
    DIRECTION OUTPUT ;
    USE SIGNAL ;
    PORT
      LAYER Metal3 ;
        RECT  899.6 175.78 900 176.18 ;
    END
  END out_block_o[60]
  PIN out_block_o[61]
    DIRECTION OUTPUT ;
    USE SIGNAL ;
    PORT
      LAYER Metal3 ;
        RECT  899.6 177.46 900 177.86 ;
    END
  END out_block_o[61]
  PIN out_block_o[62]
    DIRECTION OUTPUT ;
    USE SIGNAL ;
    PORT
      LAYER Metal3 ;
        RECT  899.6 179.14 900 179.54 ;
    END
  END out_block_o[62]
  PIN out_block_o[63]
    DIRECTION OUTPUT ;
    USE SIGNAL ;
    PORT
      LAYER Metal3 ;
        RECT  899.6 180.82 900 181.22 ;
    END
  END out_block_o[63]
  PIN out_block_o[64]
    DIRECTION OUTPUT ;
    USE SIGNAL ;
    PORT
      LAYER Metal3 ;
        RECT  899.6 182.5 900 182.9 ;
    END
  END out_block_o[64]
  PIN out_block_o[65]
    DIRECTION OUTPUT ;
    USE SIGNAL ;
    PORT
      LAYER Metal3 ;
        RECT  899.6 184.18 900 184.58 ;
    END
  END out_block_o[65]
  PIN out_block_o[66]
    DIRECTION OUTPUT ;
    USE SIGNAL ;
    PORT
      LAYER Metal3 ;
        RECT  899.6 185.86 900 186.26 ;
    END
  END out_block_o[66]
  PIN out_block_o[67]
    DIRECTION OUTPUT ;
    USE SIGNAL ;
    PORT
      LAYER Metal3 ;
        RECT  899.6 187.54 900 187.94 ;
    END
  END out_block_o[67]
  PIN out_block_o[68]
    DIRECTION OUTPUT ;
    USE SIGNAL ;
    PORT
      LAYER Metal3 ;
        RECT  899.6 189.22 900 189.62 ;
    END
  END out_block_o[68]
  PIN out_block_o[69]
    DIRECTION OUTPUT ;
    USE SIGNAL ;
    PORT
      LAYER Metal3 ;
        RECT  899.6 190.9 900 191.3 ;
    END
  END out_block_o[69]
  PIN out_block_o[6]
    DIRECTION OUTPUT ;
    USE SIGNAL ;
    PORT
      LAYER Metal3 ;
        RECT  899.6 85.06 900 85.46 ;
    END
  END out_block_o[6]
  PIN out_block_o[70]
    DIRECTION OUTPUT ;
    USE SIGNAL ;
    PORT
      LAYER Metal3 ;
        RECT  899.6 192.58 900 192.98 ;
    END
  END out_block_o[70]
  PIN out_block_o[71]
    DIRECTION OUTPUT ;
    USE SIGNAL ;
    PORT
      LAYER Metal3 ;
        RECT  899.6 194.26 900 194.66 ;
    END
  END out_block_o[71]
  PIN out_block_o[72]
    DIRECTION OUTPUT ;
    USE SIGNAL ;
    PORT
      LAYER Metal3 ;
        RECT  899.6 195.94 900 196.34 ;
    END
  END out_block_o[72]
  PIN out_block_o[73]
    DIRECTION OUTPUT ;
    USE SIGNAL ;
    PORT
      LAYER Metal3 ;
        RECT  899.6 197.62 900 198.02 ;
    END
  END out_block_o[73]
  PIN out_block_o[74]
    DIRECTION OUTPUT ;
    USE SIGNAL ;
    PORT
      LAYER Metal3 ;
        RECT  899.6 199.3 900 199.7 ;
    END
  END out_block_o[74]
  PIN out_block_o[75]
    DIRECTION OUTPUT ;
    USE SIGNAL ;
    PORT
      LAYER Metal3 ;
        RECT  899.6 200.98 900 201.38 ;
    END
  END out_block_o[75]
  PIN out_block_o[76]
    DIRECTION OUTPUT ;
    USE SIGNAL ;
    PORT
      LAYER Metal3 ;
        RECT  899.6 202.66 900 203.06 ;
    END
  END out_block_o[76]
  PIN out_block_o[77]
    DIRECTION OUTPUT ;
    USE SIGNAL ;
    PORT
      LAYER Metal3 ;
        RECT  899.6 204.34 900 204.74 ;
    END
  END out_block_o[77]
  PIN out_block_o[78]
    DIRECTION OUTPUT ;
    USE SIGNAL ;
    PORT
      LAYER Metal3 ;
        RECT  899.6 206.02 900 206.42 ;
    END
  END out_block_o[78]
  PIN out_block_o[79]
    DIRECTION OUTPUT ;
    USE SIGNAL ;
    PORT
      LAYER Metal3 ;
        RECT  899.6 207.7 900 208.1 ;
    END
  END out_block_o[79]
  PIN out_block_o[7]
    DIRECTION OUTPUT ;
    USE SIGNAL ;
    PORT
      LAYER Metal3 ;
        RECT  899.6 86.74 900 87.14 ;
    END
  END out_block_o[7]
  PIN out_block_o[80]
    DIRECTION OUTPUT ;
    USE SIGNAL ;
    PORT
      LAYER Metal3 ;
        RECT  899.6 209.38 900 209.78 ;
    END
  END out_block_o[80]
  PIN out_block_o[81]
    DIRECTION OUTPUT ;
    USE SIGNAL ;
    PORT
      LAYER Metal3 ;
        RECT  899.6 211.06 900 211.46 ;
    END
  END out_block_o[81]
  PIN out_block_o[82]
    DIRECTION OUTPUT ;
    USE SIGNAL ;
    PORT
      LAYER Metal3 ;
        RECT  899.6 212.74 900 213.14 ;
    END
  END out_block_o[82]
  PIN out_block_o[83]
    DIRECTION OUTPUT ;
    USE SIGNAL ;
    PORT
      LAYER Metal3 ;
        RECT  899.6 214.42 900 214.82 ;
    END
  END out_block_o[83]
  PIN out_block_o[84]
    DIRECTION OUTPUT ;
    USE SIGNAL ;
    PORT
      LAYER Metal3 ;
        RECT  899.6 216.1 900 216.5 ;
    END
  END out_block_o[84]
  PIN out_block_o[85]
    DIRECTION OUTPUT ;
    USE SIGNAL ;
    PORT
      LAYER Metal3 ;
        RECT  899.6 217.78 900 218.18 ;
    END
  END out_block_o[85]
  PIN out_block_o[86]
    DIRECTION OUTPUT ;
    USE SIGNAL ;
    PORT
      LAYER Metal3 ;
        RECT  899.6 219.46 900 219.86 ;
    END
  END out_block_o[86]
  PIN out_block_o[87]
    DIRECTION OUTPUT ;
    USE SIGNAL ;
    PORT
      LAYER Metal3 ;
        RECT  899.6 221.14 900 221.54 ;
    END
  END out_block_o[87]
  PIN out_block_o[88]
    DIRECTION OUTPUT ;
    USE SIGNAL ;
    PORT
      LAYER Metal3 ;
        RECT  899.6 222.82 900 223.22 ;
    END
  END out_block_o[88]
  PIN out_block_o[89]
    DIRECTION OUTPUT ;
    USE SIGNAL ;
    PORT
      LAYER Metal3 ;
        RECT  899.6 224.5 900 224.9 ;
    END
  END out_block_o[89]
  PIN out_block_o[8]
    DIRECTION OUTPUT ;
    USE SIGNAL ;
    PORT
      LAYER Metal3 ;
        RECT  899.6 88.42 900 88.82 ;
    END
  END out_block_o[8]
  PIN out_block_o[90]
    DIRECTION OUTPUT ;
    USE SIGNAL ;
    PORT
      LAYER Metal3 ;
        RECT  899.6 226.18 900 226.58 ;
    END
  END out_block_o[90]
  PIN out_block_o[91]
    DIRECTION OUTPUT ;
    USE SIGNAL ;
    PORT
      LAYER Metal3 ;
        RECT  899.6 227.86 900 228.26 ;
    END
  END out_block_o[91]
  PIN out_block_o[92]
    DIRECTION OUTPUT ;
    USE SIGNAL ;
    PORT
      LAYER Metal3 ;
        RECT  899.6 229.54 900 229.94 ;
    END
  END out_block_o[92]
  PIN out_block_o[93]
    DIRECTION OUTPUT ;
    USE SIGNAL ;
    PORT
      LAYER Metal3 ;
        RECT  899.6 231.22 900 231.62 ;
    END
  END out_block_o[93]
  PIN out_block_o[94]
    DIRECTION OUTPUT ;
    USE SIGNAL ;
    PORT
      LAYER Metal3 ;
        RECT  899.6 232.9 900 233.3 ;
    END
  END out_block_o[94]
  PIN out_block_o[95]
    DIRECTION OUTPUT ;
    USE SIGNAL ;
    PORT
      LAYER Metal3 ;
        RECT  899.6 234.58 900 234.98 ;
    END
  END out_block_o[95]
  PIN out_block_o[96]
    DIRECTION OUTPUT ;
    USE SIGNAL ;
    PORT
      LAYER Metal3 ;
        RECT  899.6 236.26 900 236.66 ;
    END
  END out_block_o[96]
  PIN out_block_o[97]
    DIRECTION OUTPUT ;
    USE SIGNAL ;
    PORT
      LAYER Metal3 ;
        RECT  899.6 237.94 900 238.34 ;
    END
  END out_block_o[97]
  PIN out_block_o[98]
    DIRECTION OUTPUT ;
    USE SIGNAL ;
    PORT
      LAYER Metal3 ;
        RECT  899.6 239.62 900 240.02 ;
    END
  END out_block_o[98]
  PIN out_block_o[99]
    DIRECTION OUTPUT ;
    USE SIGNAL ;
    PORT
      LAYER Metal3 ;
        RECT  899.6 241.3 900 241.7 ;
    END
  END out_block_o[99]
  PIN out_block_o[9]
    DIRECTION OUTPUT ;
    USE SIGNAL ;
    PORT
      LAYER Metal3 ;
        RECT  899.6 90.1 900 90.5 ;
    END
  END out_block_o[9]
  PIN out_count_o[0]
    DIRECTION OUTPUT ;
    USE SIGNAL ;
    PORT
      LAYER Metal3 ;
        RECT  899.6 68.26 900 68.66 ;
    END
  END out_count_o[0]
  PIN out_count_o[1]
    DIRECTION OUTPUT ;
    USE SIGNAL ;
    PORT
      LAYER Metal3 ;
        RECT  899.6 69.94 900 70.34 ;
    END
  END out_count_o[1]
  PIN out_count_o[2]
    DIRECTION OUTPUT ;
    USE SIGNAL ;
    PORT
      LAYER Metal3 ;
        RECT  899.6 71.62 900 72.02 ;
    END
  END out_count_o[2]
  PIN out_count_o[3]
    DIRECTION OUTPUT ;
    USE SIGNAL ;
    PORT
      LAYER Metal3 ;
        RECT  899.6 73.3 900 73.7 ;
    END
  END out_count_o[3]
  PIN out_ready_i
    DIRECTION INPUT ;
    USE SIGNAL ;
    PORT
      LAYER Metal3 ;
        RECT  899.6 64.9 900 65.3 ;
    END
  END out_ready_i
  PIN out_valid_o
    DIRECTION OUTPUT ;
    USE SIGNAL ;
    PORT
      LAYER Metal3 ;
        RECT  899.6 66.58 900 66.98 ;
    END
  END out_valid_o
  PIN predict_pc_o[0]
    DIRECTION OUTPUT ;
    USE SIGNAL ;
    PORT
      LAYER Metal3 ;
        RECT  0 932.62 0.4 933.02 ;
    END
  END predict_pc_o[0]
  PIN predict_pc_o[10]
    DIRECTION OUTPUT ;
    USE SIGNAL ;
    PORT
      LAYER Metal3 ;
        RECT  0 957.82 0.4 958.22 ;
    END
  END predict_pc_o[10]
  PIN predict_pc_o[11]
    DIRECTION OUTPUT ;
    USE SIGNAL ;
    PORT
      LAYER Metal3 ;
        RECT  0 960.34 0.4 960.74 ;
    END
  END predict_pc_o[11]
  PIN predict_pc_o[12]
    DIRECTION OUTPUT ;
    USE SIGNAL ;
    PORT
      LAYER Metal3 ;
        RECT  0 962.86 0.4 963.26 ;
    END
  END predict_pc_o[12]
  PIN predict_pc_o[13]
    DIRECTION OUTPUT ;
    USE SIGNAL ;
    PORT
      LAYER Metal3 ;
        RECT  0 965.38 0.4 965.78 ;
    END
  END predict_pc_o[13]
  PIN predict_pc_o[14]
    DIRECTION OUTPUT ;
    USE SIGNAL ;
    PORT
      LAYER Metal3 ;
        RECT  0 967.9 0.4 968.3 ;
    END
  END predict_pc_o[14]
  PIN predict_pc_o[15]
    DIRECTION OUTPUT ;
    USE SIGNAL ;
    PORT
      LAYER Metal3 ;
        RECT  0 970.42 0.4 970.82 ;
    END
  END predict_pc_o[15]
  PIN predict_pc_o[16]
    DIRECTION OUTPUT ;
    USE SIGNAL ;
    PORT
      LAYER Metal3 ;
        RECT  0 972.94 0.4 973.34 ;
    END
  END predict_pc_o[16]
  PIN predict_pc_o[17]
    DIRECTION OUTPUT ;
    USE SIGNAL ;
    PORT
      LAYER Metal3 ;
        RECT  0 975.46 0.4 975.86 ;
    END
  END predict_pc_o[17]
  PIN predict_pc_o[18]
    DIRECTION OUTPUT ;
    USE SIGNAL ;
    PORT
      LAYER Metal3 ;
        RECT  0 977.98 0.4 978.38 ;
    END
  END predict_pc_o[18]
  PIN predict_pc_o[19]
    DIRECTION OUTPUT ;
    USE SIGNAL ;
    PORT
      LAYER Metal3 ;
        RECT  0 980.5 0.4 980.9 ;
    END
  END predict_pc_o[19]
  PIN predict_pc_o[1]
    DIRECTION OUTPUT ;
    USE SIGNAL ;
    PORT
      LAYER Metal3 ;
        RECT  0 935.14 0.4 935.54 ;
    END
  END predict_pc_o[1]
  PIN predict_pc_o[20]
    DIRECTION OUTPUT ;
    USE SIGNAL ;
    PORT
      LAYER Metal3 ;
        RECT  0 983.02 0.4 983.42 ;
    END
  END predict_pc_o[20]
  PIN predict_pc_o[21]
    DIRECTION OUTPUT ;
    USE SIGNAL ;
    PORT
      LAYER Metal3 ;
        RECT  0 985.54 0.4 985.94 ;
    END
  END predict_pc_o[21]
  PIN predict_pc_o[22]
    DIRECTION OUTPUT ;
    USE SIGNAL ;
    PORT
      LAYER Metal3 ;
        RECT  0 988.06 0.4 988.46 ;
    END
  END predict_pc_o[22]
  PIN predict_pc_o[23]
    DIRECTION OUTPUT ;
    USE SIGNAL ;
    PORT
      LAYER Metal3 ;
        RECT  0 990.58 0.4 990.98 ;
    END
  END predict_pc_o[23]
  PIN predict_pc_o[24]
    DIRECTION OUTPUT ;
    USE SIGNAL ;
    PORT
      LAYER Metal3 ;
        RECT  0 993.1 0.4 993.5 ;
    END
  END predict_pc_o[24]
  PIN predict_pc_o[25]
    DIRECTION OUTPUT ;
    USE SIGNAL ;
    PORT
      LAYER Metal3 ;
        RECT  0 995.62 0.4 996.02 ;
    END
  END predict_pc_o[25]
  PIN predict_pc_o[26]
    DIRECTION OUTPUT ;
    USE SIGNAL ;
    PORT
      LAYER Metal3 ;
        RECT  0 998.14 0.4 998.54 ;
    END
  END predict_pc_o[26]
  PIN predict_pc_o[27]
    DIRECTION OUTPUT ;
    USE SIGNAL ;
    PORT
      LAYER Metal3 ;
        RECT  0 1000.66 0.4 1001.06 ;
    END
  END predict_pc_o[27]
  PIN predict_pc_o[28]
    DIRECTION OUTPUT ;
    USE SIGNAL ;
    PORT
      LAYER Metal3 ;
        RECT  0 1003.18 0.4 1003.58 ;
    END
  END predict_pc_o[28]
  PIN predict_pc_o[29]
    DIRECTION OUTPUT ;
    USE SIGNAL ;
    PORT
      LAYER Metal3 ;
        RECT  0 1005.7 0.4 1006.1 ;
    END
  END predict_pc_o[29]
  PIN predict_pc_o[2]
    DIRECTION OUTPUT ;
    USE SIGNAL ;
    PORT
      LAYER Metal3 ;
        RECT  0 937.66 0.4 938.06 ;
    END
  END predict_pc_o[2]
  PIN predict_pc_o[30]
    DIRECTION OUTPUT ;
    USE SIGNAL ;
    PORT
      LAYER Metal3 ;
        RECT  0 1008.22 0.4 1008.62 ;
    END
  END predict_pc_o[30]
  PIN predict_pc_o[31]
    DIRECTION OUTPUT ;
    USE SIGNAL ;
    PORT
      LAYER Metal3 ;
        RECT  0 1010.74 0.4 1011.14 ;
    END
  END predict_pc_o[31]
  PIN predict_pc_o[3]
    DIRECTION OUTPUT ;
    USE SIGNAL ;
    PORT
      LAYER Metal3 ;
        RECT  0 940.18 0.4 940.58 ;
    END
  END predict_pc_o[3]
  PIN predict_pc_o[4]
    DIRECTION OUTPUT ;
    USE SIGNAL ;
    PORT
      LAYER Metal3 ;
        RECT  0 942.7 0.4 943.1 ;
    END
  END predict_pc_o[4]
  PIN predict_pc_o[5]
    DIRECTION OUTPUT ;
    USE SIGNAL ;
    PORT
      LAYER Metal3 ;
        RECT  0 945.22 0.4 945.62 ;
    END
  END predict_pc_o[5]
  PIN predict_pc_o[6]
    DIRECTION OUTPUT ;
    USE SIGNAL ;
    PORT
      LAYER Metal3 ;
        RECT  0 947.74 0.4 948.14 ;
    END
  END predict_pc_o[6]
  PIN predict_pc_o[7]
    DIRECTION OUTPUT ;
    USE SIGNAL ;
    PORT
      LAYER Metal3 ;
        RECT  0 950.26 0.4 950.66 ;
    END
  END predict_pc_o[7]
  PIN predict_pc_o[8]
    DIRECTION OUTPUT ;
    USE SIGNAL ;
    PORT
      LAYER Metal3 ;
        RECT  0 952.78 0.4 953.18 ;
    END
  END predict_pc_o[8]
  PIN predict_pc_o[9]
    DIRECTION OUTPUT ;
    USE SIGNAL ;
    PORT
      LAYER Metal3 ;
        RECT  0 955.3 0.4 955.7 ;
    END
  END predict_pc_o[9]
  PIN predict_valid_o
    DIRECTION OUTPUT ;
    USE SIGNAL ;
    PORT
      LAYER Metal3 ;
        RECT  0 930.1 0.4 930.5 ;
    END
  END predict_valid_o
  PIN recovery_i.ghist[0]
    DIRECTION INPUT ;
    USE SIGNAL ;
    PORT
      LAYER Metal2 ;
        RECT  29.08 1099.6 29.48 1100 ;
    END
  END recovery_i.ghist[0]
  PIN recovery_i.ghist[10]
    DIRECTION INPUT ;
    USE SIGNAL ;
    PORT
      LAYER Metal2 ;
        RECT  294.04 1099.6 294.44 1100 ;
    END
  END recovery_i.ghist[10]
  PIN recovery_i.ghist[11]
    DIRECTION INPUT ;
    USE SIGNAL ;
    PORT
      LAYER Metal2 ;
        RECT  317.08 1099.6 317.48 1100 ;
    END
  END recovery_i.ghist[11]
  PIN recovery_i.ghist[12]
    DIRECTION INPUT ;
    USE SIGNAL ;
    PORT
      LAYER Metal2 ;
        RECT  340.12 1099.6 340.52 1100 ;
    END
  END recovery_i.ghist[12]
  PIN recovery_i.ghist[13]
    DIRECTION INPUT ;
    USE SIGNAL ;
    PORT
      LAYER Metal2 ;
        RECT  363.16 1099.6 363.56 1100 ;
    END
  END recovery_i.ghist[13]
  PIN recovery_i.ghist[14]
    DIRECTION INPUT ;
    USE SIGNAL ;
    PORT
      LAYER Metal2 ;
        RECT  386.2 1099.6 386.6 1100 ;
    END
  END recovery_i.ghist[14]
  PIN recovery_i.ghist[15]
    DIRECTION INPUT ;
    USE SIGNAL ;
    PORT
      LAYER Metal2 ;
        RECT  409.24 1099.6 409.64 1100 ;
    END
  END recovery_i.ghist[15]
  PIN recovery_i.ghist[1]
    DIRECTION INPUT ;
    USE SIGNAL ;
    PORT
      LAYER Metal2 ;
        RECT  63.64 1099.6 64.04 1100 ;
    END
  END recovery_i.ghist[1]
  PIN recovery_i.ghist[2]
    DIRECTION INPUT ;
    USE SIGNAL ;
    PORT
      LAYER Metal2 ;
        RECT  98.2 1099.6 98.6 1100 ;
    END
  END recovery_i.ghist[2]
  PIN recovery_i.ghist[3]
    DIRECTION INPUT ;
    USE SIGNAL ;
    PORT
      LAYER Metal2 ;
        RECT  132.76 1099.6 133.16 1100 ;
    END
  END recovery_i.ghist[3]
  PIN recovery_i.ghist[4]
    DIRECTION INPUT ;
    USE SIGNAL ;
    PORT
      LAYER Metal2 ;
        RECT  155.8 1099.6 156.2 1100 ;
    END
  END recovery_i.ghist[4]
  PIN recovery_i.ghist[5]
    DIRECTION INPUT ;
    USE SIGNAL ;
    PORT
      LAYER Metal2 ;
        RECT  178.84 1099.6 179.24 1100 ;
    END
  END recovery_i.ghist[5]
  PIN recovery_i.ghist[6]
    DIRECTION INPUT ;
    USE SIGNAL ;
    PORT
      LAYER Metal2 ;
        RECT  201.88 1099.6 202.28 1100 ;
    END
  END recovery_i.ghist[6]
  PIN recovery_i.ghist[7]
    DIRECTION INPUT ;
    USE SIGNAL ;
    PORT
      LAYER Metal2 ;
        RECT  224.92 1099.6 225.32 1100 ;
    END
  END recovery_i.ghist[7]
  PIN recovery_i.ghist[8]
    DIRECTION INPUT ;
    USE SIGNAL ;
    PORT
      LAYER Metal2 ;
        RECT  247.96 1099.6 248.36 1100 ;
    END
  END recovery_i.ghist[8]
  PIN recovery_i.ghist[9]
    DIRECTION INPUT ;
    USE SIGNAL ;
    PORT
      LAYER Metal2 ;
        RECT  271 1099.6 271.4 1100 ;
    END
  END recovery_i.ghist[9]
  PIN recovery_i.new_pc[0]
    DIRECTION INPUT ;
    USE SIGNAL ;
    PORT
      LAYER Metal2 ;
        RECT  40.6 1099.6 41 1100 ;
    END
  END recovery_i.new_pc[0]
  PIN recovery_i.new_pc[10]
    DIRECTION INPUT ;
    USE SIGNAL ;
    PORT
      LAYER Metal2 ;
        RECT  305.56 1099.6 305.96 1100 ;
    END
  END recovery_i.new_pc[10]
  PIN recovery_i.new_pc[11]
    DIRECTION INPUT ;
    USE SIGNAL ;
    PORT
      LAYER Metal2 ;
        RECT  328.6 1099.6 329 1100 ;
    END
  END recovery_i.new_pc[11]
  PIN recovery_i.new_pc[12]
    DIRECTION INPUT ;
    USE SIGNAL ;
    PORT
      LAYER Metal2 ;
        RECT  351.64 1099.6 352.04 1100 ;
    END
  END recovery_i.new_pc[12]
  PIN recovery_i.new_pc[13]
    DIRECTION INPUT ;
    USE SIGNAL ;
    PORT
      LAYER Metal2 ;
        RECT  374.68 1099.6 375.08 1100 ;
    END
  END recovery_i.new_pc[13]
  PIN recovery_i.new_pc[14]
    DIRECTION INPUT ;
    USE SIGNAL ;
    PORT
      LAYER Metal2 ;
        RECT  397.72 1099.6 398.12 1100 ;
    END
  END recovery_i.new_pc[14]
  PIN recovery_i.new_pc[15]
    DIRECTION INPUT ;
    USE SIGNAL ;
    PORT
      LAYER Metal2 ;
        RECT  420.76 1099.6 421.16 1100 ;
    END
  END recovery_i.new_pc[15]
  PIN recovery_i.new_pc[16]
    DIRECTION INPUT ;
    USE SIGNAL ;
    PORT
      LAYER Metal2 ;
        RECT  432.28 1099.6 432.68 1100 ;
    END
  END recovery_i.new_pc[16]
  PIN recovery_i.new_pc[17]
    DIRECTION INPUT ;
    USE SIGNAL ;
    PORT
      LAYER Metal2 ;
        RECT  443.8 1099.6 444.2 1100 ;
    END
  END recovery_i.new_pc[17]
  PIN recovery_i.new_pc[18]
    DIRECTION INPUT ;
    USE SIGNAL ;
    PORT
      LAYER Metal2 ;
        RECT  455.32 1099.6 455.72 1100 ;
    END
  END recovery_i.new_pc[18]
  PIN recovery_i.new_pc[19]
    DIRECTION INPUT ;
    USE SIGNAL ;
    PORT
      LAYER Metal2 ;
        RECT  466.84 1099.6 467.24 1100 ;
    END
  END recovery_i.new_pc[19]
  PIN recovery_i.new_pc[1]
    DIRECTION INPUT ;
    USE SIGNAL ;
    PORT
      LAYER Metal2 ;
        RECT  75.16 1099.6 75.56 1100 ;
    END
  END recovery_i.new_pc[1]
  PIN recovery_i.new_pc[20]
    DIRECTION INPUT ;
    USE SIGNAL ;
    PORT
      LAYER Metal2 ;
        RECT  478.36 1099.6 478.76 1100 ;
    END
  END recovery_i.new_pc[20]
  PIN recovery_i.new_pc[21]
    DIRECTION INPUT ;
    USE SIGNAL ;
    PORT
      LAYER Metal2 ;
        RECT  489.88 1099.6 490.28 1100 ;
    END
  END recovery_i.new_pc[21]
  PIN recovery_i.new_pc[22]
    DIRECTION INPUT ;
    USE SIGNAL ;
    PORT
      LAYER Metal2 ;
        RECT  501.4 1099.6 501.8 1100 ;
    END
  END recovery_i.new_pc[22]
  PIN recovery_i.new_pc[23]
    DIRECTION INPUT ;
    USE SIGNAL ;
    PORT
      LAYER Metal2 ;
        RECT  512.92 1099.6 513.32 1100 ;
    END
  END recovery_i.new_pc[23]
  PIN recovery_i.new_pc[24]
    DIRECTION INPUT ;
    USE SIGNAL ;
    PORT
      LAYER Metal2 ;
        RECT  524.44 1099.6 524.84 1100 ;
    END
  END recovery_i.new_pc[24]
  PIN recovery_i.new_pc[25]
    DIRECTION INPUT ;
    USE SIGNAL ;
    PORT
      LAYER Metal2 ;
        RECT  535.96 1099.6 536.36 1100 ;
    END
  END recovery_i.new_pc[25]
  PIN recovery_i.new_pc[26]
    DIRECTION INPUT ;
    USE SIGNAL ;
    PORT
      LAYER Metal2 ;
        RECT  547.48 1099.6 547.88 1100 ;
    END
  END recovery_i.new_pc[26]
  PIN recovery_i.new_pc[27]
    DIRECTION INPUT ;
    USE SIGNAL ;
    PORT
      LAYER Metal2 ;
        RECT  559 1099.6 559.4 1100 ;
    END
  END recovery_i.new_pc[27]
  PIN recovery_i.new_pc[28]
    DIRECTION INPUT ;
    USE SIGNAL ;
    PORT
      LAYER Metal2 ;
        RECT  570.52 1099.6 570.92 1100 ;
    END
  END recovery_i.new_pc[28]
  PIN recovery_i.new_pc[29]
    DIRECTION INPUT ;
    USE SIGNAL ;
    PORT
      LAYER Metal2 ;
        RECT  582.04 1099.6 582.44 1100 ;
    END
  END recovery_i.new_pc[29]
  PIN recovery_i.new_pc[2]
    DIRECTION INPUT ;
    USE SIGNAL ;
    PORT
      LAYER Metal2 ;
        RECT  109.72 1099.6 110.12 1100 ;
    END
  END recovery_i.new_pc[2]
  PIN recovery_i.new_pc[30]
    DIRECTION INPUT ;
    USE SIGNAL ;
    PORT
      LAYER Metal2 ;
        RECT  593.56 1099.6 593.96 1100 ;
    END
  END recovery_i.new_pc[30]
  PIN recovery_i.new_pc[31]
    DIRECTION INPUT ;
    USE SIGNAL ;
    PORT
      LAYER Metal2 ;
        RECT  605.08 1099.6 605.48 1100 ;
    END
  END recovery_i.new_pc[31]
  PIN recovery_i.new_pc[3]
    DIRECTION INPUT ;
    USE SIGNAL ;
    PORT
      LAYER Metal2 ;
        RECT  144.28 1099.6 144.68 1100 ;
    END
  END recovery_i.new_pc[3]
  PIN recovery_i.new_pc[4]
    DIRECTION INPUT ;
    USE SIGNAL ;
    PORT
      LAYER Metal2 ;
        RECT  167.32 1099.6 167.72 1100 ;
    END
  END recovery_i.new_pc[4]
  PIN recovery_i.new_pc[5]
    DIRECTION INPUT ;
    USE SIGNAL ;
    PORT
      LAYER Metal2 ;
        RECT  190.36 1099.6 190.76 1100 ;
    END
  END recovery_i.new_pc[5]
  PIN recovery_i.new_pc[6]
    DIRECTION INPUT ;
    USE SIGNAL ;
    PORT
      LAYER Metal2 ;
        RECT  213.4 1099.6 213.8 1100 ;
    END
  END recovery_i.new_pc[6]
  PIN recovery_i.new_pc[7]
    DIRECTION INPUT ;
    USE SIGNAL ;
    PORT
      LAYER Metal2 ;
        RECT  236.44 1099.6 236.84 1100 ;
    END
  END recovery_i.new_pc[7]
  PIN recovery_i.new_pc[8]
    DIRECTION INPUT ;
    USE SIGNAL ;
    PORT
      LAYER Metal2 ;
        RECT  259.48 1099.6 259.88 1100 ;
    END
  END recovery_i.new_pc[8]
  PIN recovery_i.new_pc[9]
    DIRECTION INPUT ;
    USE SIGNAL ;
    PORT
      LAYER Metal2 ;
        RECT  282.52 1099.6 282.92 1100 ;
    END
  END recovery_i.new_pc[9]
  PIN recovery_i.ras_ptr[0]
    DIRECTION INPUT ;
    USE SIGNAL ;
    PORT
      LAYER Metal2 ;
        RECT  52.12 1099.6 52.52 1100 ;
    END
  END recovery_i.ras_ptr[0]
  PIN recovery_i.ras_ptr[1]
    DIRECTION INPUT ;
    USE SIGNAL ;
    PORT
      LAYER Metal2 ;
        RECT  86.68 1099.6 87.08 1100 ;
    END
  END recovery_i.ras_ptr[1]
  PIN recovery_i.ras_ptr[2]
    DIRECTION INPUT ;
    USE SIGNAL ;
    PORT
      LAYER Metal2 ;
        RECT  121.24 1099.6 121.64 1100 ;
    END
  END recovery_i.ras_ptr[2]
  PIN recovery_i.valid
    DIRECTION INPUT ;
    USE SIGNAL ;
    PORT
      LAYER Metal2 ;
        RECT  17.56 1099.6 17.96 1100 ;
    END
  END recovery_i.valid
  PIN reset_i
    DIRECTION INPUT ;
    USE SIGNAL ;
    PORT
      LAYER Metal2 ;
        RECT  870.04 1099.6 870.44 1100 ;
    END
  END reset_i
  PIN retire_i.conditional
    DIRECTION INPUT ;
    USE SIGNAL ;
    PORT
      LAYER Metal2 ;
        RECT  616.6 1099.6 617 1100 ;
    END
  END retire_i.conditional
  PIN retire_i.ghist_low[0]
    DIRECTION INPUT ;
    USE SIGNAL ;
    PORT
      LAYER Metal2 ;
        RECT  662.68 1099.6 663.08 1100 ;
    END
  END retire_i.ghist_low[0]
  PIN retire_i.ghist_low[1]
    DIRECTION INPUT ;
    USE SIGNAL ;
    PORT
      LAYER Metal2 ;
        RECT  685.72 1099.6 686.12 1100 ;
    END
  END retire_i.ghist_low[1]
  PIN retire_i.ghist_low[2]
    DIRECTION INPUT ;
    USE SIGNAL ;
    PORT
      LAYER Metal2 ;
        RECT  708.76 1099.6 709.16 1100 ;
    END
  END retire_i.ghist_low[2]
  PIN retire_i.ghist_low[3]
    DIRECTION INPUT ;
    USE SIGNAL ;
    PORT
      LAYER Metal2 ;
        RECT  731.8 1099.6 732.2 1100 ;
    END
  END retire_i.ghist_low[3]
  PIN retire_i.ghist_low[4]
    DIRECTION INPUT ;
    USE SIGNAL ;
    PORT
      LAYER Metal2 ;
        RECT  754.84 1099.6 755.24 1100 ;
    END
  END retire_i.ghist_low[4]
  PIN retire_i.ghist_low[5]
    DIRECTION INPUT ;
    USE SIGNAL ;
    PORT
      LAYER Metal2 ;
        RECT  777.88 1099.6 778.28 1100 ;
    END
  END retire_i.ghist_low[5]
  PIN retire_i.ghist_low[6]
    DIRECTION INPUT ;
    USE SIGNAL ;
    PORT
      LAYER Metal2 ;
        RECT  800.92 1099.6 801.32 1100 ;
    END
  END retire_i.ghist_low[6]
  PIN retire_i.ghist_low[7]
    DIRECTION INPUT ;
    USE SIGNAL ;
    PORT
      LAYER Metal2 ;
        RECT  823.96 1099.6 824.36 1100 ;
    END
  END retire_i.ghist_low[7]
  PIN retire_i.ghist_low[8]
    DIRECTION INPUT ;
    USE SIGNAL ;
    PORT
      LAYER Metal2 ;
        RECT  847 1099.6 847.4 1100 ;
    END
  END retire_i.ghist_low[8]
  PIN retire_i.is_control
    DIRECTION INPUT ;
    USE SIGNAL ;
    PORT
      LAYER Metal2 ;
        RECT  628.12 1099.6 628.52 1100 ;
    END
  END retire_i.is_control
  PIN retire_i.pc_low[0]
    DIRECTION INPUT ;
    USE SIGNAL ;
    PORT
      LAYER Metal2 ;
        RECT  674.2 1099.6 674.6 1100 ;
    END
  END retire_i.pc_low[0]
  PIN retire_i.pc_low[1]
    DIRECTION INPUT ;
    USE SIGNAL ;
    PORT
      LAYER Metal2 ;
        RECT  697.24 1099.6 697.64 1100 ;
    END
  END retire_i.pc_low[1]
  PIN retire_i.pc_low[2]
    DIRECTION INPUT ;
    USE SIGNAL ;
    PORT
      LAYER Metal2 ;
        RECT  720.28 1099.6 720.68 1100 ;
    END
  END retire_i.pc_low[2]
  PIN retire_i.pc_low[3]
    DIRECTION INPUT ;
    USE SIGNAL ;
    PORT
      LAYER Metal2 ;
        RECT  743.32 1099.6 743.72 1100 ;
    END
  END retire_i.pc_low[3]
  PIN retire_i.pc_low[4]
    DIRECTION INPUT ;
    USE SIGNAL ;
    PORT
      LAYER Metal2 ;
        RECT  766.36 1099.6 766.76 1100 ;
    END
  END retire_i.pc_low[4]
  PIN retire_i.pc_low[5]
    DIRECTION INPUT ;
    USE SIGNAL ;
    PORT
      LAYER Metal2 ;
        RECT  789.4 1099.6 789.8 1100 ;
    END
  END retire_i.pc_low[5]
  PIN retire_i.pc_low[6]
    DIRECTION INPUT ;
    USE SIGNAL ;
    PORT
      LAYER Metal2 ;
        RECT  812.44 1099.6 812.84 1100 ;
    END
  END retire_i.pc_low[6]
  PIN retire_i.pc_low[7]
    DIRECTION INPUT ;
    USE SIGNAL ;
    PORT
      LAYER Metal2 ;
        RECT  835.48 1099.6 835.88 1100 ;
    END
  END retire_i.pc_low[7]
  PIN retire_i.pc_low[8]
    DIRECTION INPUT ;
    USE SIGNAL ;
    PORT
      LAYER Metal2 ;
        RECT  858.52 1099.6 858.92 1100 ;
    END
  END retire_i.pc_low[8]
  PIN retire_i.taken
    DIRECTION INPUT ;
    USE SIGNAL ;
    PORT
      LAYER Metal2 ;
        RECT  639.64 1099.6 640.04 1100 ;
    END
  END retire_i.taken
  PIN retire_i.valid
    DIRECTION INPUT ;
    USE SIGNAL ;
    PORT
      LAYER Metal2 ;
        RECT  651.16 1099.6 651.56 1100 ;
    END
  END retire_i.valid
  PIN stop_o
    DIRECTION OUTPUT ;
    USE SIGNAL ;
    PORT
      LAYER Metal3 ;
        RECT  0 927.58 0.4 927.98 ;
    END
  END stop_o
  PIN window_count_i[0]
    DIRECTION INPUT ;
    USE SIGNAL ;
    PORT
      LAYER Metal3 ;
        RECT  0 814.18 0.4 814.58 ;
    END
  END window_count_i[0]
  PIN window_count_i[1]
    DIRECTION INPUT ;
    USE SIGNAL ;
    PORT
      LAYER Metal3 ;
        RECT  0 816.7 0.4 817.1 ;
    END
  END window_count_i[1]
  PIN window_count_i[2]
    DIRECTION INPUT ;
    USE SIGNAL ;
    PORT
      LAYER Metal3 ;
        RECT  0 819.22 0.4 819.62 ;
    END
  END window_count_i[2]
  PIN window_count_i[3]
    DIRECTION INPUT ;
    USE SIGNAL ;
    PORT
      LAYER Metal3 ;
        RECT  0 821.74 0.4 822.14 ;
    END
  END window_count_i[3]
  PIN window_count_i[4]
    DIRECTION INPUT ;
    USE SIGNAL ;
    PORT
      LAYER Metal3 ;
        RECT  0 824.26 0.4 824.66 ;
    END
  END window_count_i[4]
  PIN window_count_i[5]
    DIRECTION INPUT ;
    USE SIGNAL ;
    PORT
      LAYER Metal3 ;
        RECT  0 826.78 0.4 827.18 ;
    END
  END window_count_i[5]
  PIN window_fault_i[0]
    DIRECTION INPUT ;
    USE SIGNAL ;
    PORT
      LAYER Metal3 ;
        RECT  0 733.54 0.4 733.94 ;
    END
  END window_fault_i[0]
  PIN window_fault_i[10]
    DIRECTION INPUT ;
    USE SIGNAL ;
    PORT
      LAYER Metal3 ;
        RECT  0 758.74 0.4 759.14 ;
    END
  END window_fault_i[10]
  PIN window_fault_i[11]
    DIRECTION INPUT ;
    USE SIGNAL ;
    PORT
      LAYER Metal3 ;
        RECT  0 761.26 0.4 761.66 ;
    END
  END window_fault_i[11]
  PIN window_fault_i[12]
    DIRECTION INPUT ;
    USE SIGNAL ;
    PORT
      LAYER Metal3 ;
        RECT  0 763.78 0.4 764.18 ;
    END
  END window_fault_i[12]
  PIN window_fault_i[13]
    DIRECTION INPUT ;
    USE SIGNAL ;
    PORT
      LAYER Metal3 ;
        RECT  0 766.3 0.4 766.7 ;
    END
  END window_fault_i[13]
  PIN window_fault_i[14]
    DIRECTION INPUT ;
    USE SIGNAL ;
    PORT
      LAYER Metal3 ;
        RECT  0 768.82 0.4 769.22 ;
    END
  END window_fault_i[14]
  PIN window_fault_i[15]
    DIRECTION INPUT ;
    USE SIGNAL ;
    PORT
      LAYER Metal3 ;
        RECT  0 771.34 0.4 771.74 ;
    END
  END window_fault_i[15]
  PIN window_fault_i[16]
    DIRECTION INPUT ;
    USE SIGNAL ;
    PORT
      LAYER Metal3 ;
        RECT  0 773.86 0.4 774.26 ;
    END
  END window_fault_i[16]
  PIN window_fault_i[17]
    DIRECTION INPUT ;
    USE SIGNAL ;
    PORT
      LAYER Metal3 ;
        RECT  0 776.38 0.4 776.78 ;
    END
  END window_fault_i[17]
  PIN window_fault_i[18]
    DIRECTION INPUT ;
    USE SIGNAL ;
    PORT
      LAYER Metal3 ;
        RECT  0 778.9 0.4 779.3 ;
    END
  END window_fault_i[18]
  PIN window_fault_i[19]
    DIRECTION INPUT ;
    USE SIGNAL ;
    PORT
      LAYER Metal3 ;
        RECT  0 781.42 0.4 781.82 ;
    END
  END window_fault_i[19]
  PIN window_fault_i[1]
    DIRECTION INPUT ;
    USE SIGNAL ;
    PORT
      LAYER Metal3 ;
        RECT  0 736.06 0.4 736.46 ;
    END
  END window_fault_i[1]
  PIN window_fault_i[20]
    DIRECTION INPUT ;
    USE SIGNAL ;
    PORT
      LAYER Metal3 ;
        RECT  0 783.94 0.4 784.34 ;
    END
  END window_fault_i[20]
  PIN window_fault_i[21]
    DIRECTION INPUT ;
    USE SIGNAL ;
    PORT
      LAYER Metal3 ;
        RECT  0 786.46 0.4 786.86 ;
    END
  END window_fault_i[21]
  PIN window_fault_i[22]
    DIRECTION INPUT ;
    USE SIGNAL ;
    PORT
      LAYER Metal3 ;
        RECT  0 788.98 0.4 789.38 ;
    END
  END window_fault_i[22]
  PIN window_fault_i[23]
    DIRECTION INPUT ;
    USE SIGNAL ;
    PORT
      LAYER Metal3 ;
        RECT  0 791.5 0.4 791.9 ;
    END
  END window_fault_i[23]
  PIN window_fault_i[24]
    DIRECTION INPUT ;
    USE SIGNAL ;
    PORT
      LAYER Metal3 ;
        RECT  0 794.02 0.4 794.42 ;
    END
  END window_fault_i[24]
  PIN window_fault_i[25]
    DIRECTION INPUT ;
    USE SIGNAL ;
    PORT
      LAYER Metal3 ;
        RECT  0 796.54 0.4 796.94 ;
    END
  END window_fault_i[25]
  PIN window_fault_i[26]
    DIRECTION INPUT ;
    USE SIGNAL ;
    PORT
      LAYER Metal3 ;
        RECT  0 799.06 0.4 799.46 ;
    END
  END window_fault_i[26]
  PIN window_fault_i[27]
    DIRECTION INPUT ;
    USE SIGNAL ;
    PORT
      LAYER Metal3 ;
        RECT  0 801.58 0.4 801.98 ;
    END
  END window_fault_i[27]
  PIN window_fault_i[28]
    DIRECTION INPUT ;
    USE SIGNAL ;
    PORT
      LAYER Metal3 ;
        RECT  0 804.1 0.4 804.5 ;
    END
  END window_fault_i[28]
  PIN window_fault_i[29]
    DIRECTION INPUT ;
    USE SIGNAL ;
    PORT
      LAYER Metal3 ;
        RECT  0 806.62 0.4 807.02 ;
    END
  END window_fault_i[29]
  PIN window_fault_i[2]
    DIRECTION INPUT ;
    USE SIGNAL ;
    PORT
      LAYER Metal3 ;
        RECT  0 738.58 0.4 738.98 ;
    END
  END window_fault_i[2]
  PIN window_fault_i[30]
    DIRECTION INPUT ;
    USE SIGNAL ;
    PORT
      LAYER Metal3 ;
        RECT  0 809.14 0.4 809.54 ;
    END
  END window_fault_i[30]
  PIN window_fault_i[31]
    DIRECTION INPUT ;
    USE SIGNAL ;
    PORT
      LAYER Metal3 ;
        RECT  0 811.66 0.4 812.06 ;
    END
  END window_fault_i[31]
  PIN window_fault_i[3]
    DIRECTION INPUT ;
    USE SIGNAL ;
    PORT
      LAYER Metal3 ;
        RECT  0 741.1 0.4 741.5 ;
    END
  END window_fault_i[3]
  PIN window_fault_i[4]
    DIRECTION INPUT ;
    USE SIGNAL ;
    PORT
      LAYER Metal3 ;
        RECT  0 743.62 0.4 744.02 ;
    END
  END window_fault_i[4]
  PIN window_fault_i[5]
    DIRECTION INPUT ;
    USE SIGNAL ;
    PORT
      LAYER Metal3 ;
        RECT  0 746.14 0.4 746.54 ;
    END
  END window_fault_i[5]
  PIN window_fault_i[6]
    DIRECTION INPUT ;
    USE SIGNAL ;
    PORT
      LAYER Metal3 ;
        RECT  0 748.66 0.4 749.06 ;
    END
  END window_fault_i[6]
  PIN window_fault_i[7]
    DIRECTION INPUT ;
    USE SIGNAL ;
    PORT
      LAYER Metal3 ;
        RECT  0 751.18 0.4 751.58 ;
    END
  END window_fault_i[7]
  PIN window_fault_i[8]
    DIRECTION INPUT ;
    USE SIGNAL ;
    PORT
      LAYER Metal3 ;
        RECT  0 753.7 0.4 754.1 ;
    END
  END window_fault_i[8]
  PIN window_fault_i[9]
    DIRECTION INPUT ;
    USE SIGNAL ;
    PORT
      LAYER Metal3 ;
        RECT  0 756.22 0.4 756.62 ;
    END
  END window_fault_i[9]
  PIN window_i[0]
    DIRECTION INPUT ;
    USE SIGNAL ;
    PORT
      LAYER Metal3 ;
        RECT  0 88.42 0.4 88.82 ;
    END
  END window_i[0]
  PIN window_i[100]
    DIRECTION INPUT ;
    USE SIGNAL ;
    PORT
      LAYER Metal3 ;
        RECT  0 340.42 0.4 340.82 ;
    END
  END window_i[100]
  PIN window_i[101]
    DIRECTION INPUT ;
    USE SIGNAL ;
    PORT
      LAYER Metal3 ;
        RECT  0 342.94 0.4 343.34 ;
    END
  END window_i[101]
  PIN window_i[102]
    DIRECTION INPUT ;
    USE SIGNAL ;
    PORT
      LAYER Metal3 ;
        RECT  0 345.46 0.4 345.86 ;
    END
  END window_i[102]
  PIN window_i[103]
    DIRECTION INPUT ;
    USE SIGNAL ;
    PORT
      LAYER Metal3 ;
        RECT  0 347.98 0.4 348.38 ;
    END
  END window_i[103]
  PIN window_i[104]
    DIRECTION INPUT ;
    USE SIGNAL ;
    PORT
      LAYER Metal3 ;
        RECT  0 350.5 0.4 350.9 ;
    END
  END window_i[104]
  PIN window_i[105]
    DIRECTION INPUT ;
    USE SIGNAL ;
    PORT
      LAYER Metal3 ;
        RECT  0 353.02 0.4 353.42 ;
    END
  END window_i[105]
  PIN window_i[106]
    DIRECTION INPUT ;
    USE SIGNAL ;
    PORT
      LAYER Metal3 ;
        RECT  0 355.54 0.4 355.94 ;
    END
  END window_i[106]
  PIN window_i[107]
    DIRECTION INPUT ;
    USE SIGNAL ;
    PORT
      LAYER Metal3 ;
        RECT  0 358.06 0.4 358.46 ;
    END
  END window_i[107]
  PIN window_i[108]
    DIRECTION INPUT ;
    USE SIGNAL ;
    PORT
      LAYER Metal3 ;
        RECT  0 360.58 0.4 360.98 ;
    END
  END window_i[108]
  PIN window_i[109]
    DIRECTION INPUT ;
    USE SIGNAL ;
    PORT
      LAYER Metal3 ;
        RECT  0 363.1 0.4 363.5 ;
    END
  END window_i[109]
  PIN window_i[10]
    DIRECTION INPUT ;
    USE SIGNAL ;
    PORT
      LAYER Metal3 ;
        RECT  0 113.62 0.4 114.02 ;
    END
  END window_i[10]
  PIN window_i[110]
    DIRECTION INPUT ;
    USE SIGNAL ;
    PORT
      LAYER Metal3 ;
        RECT  0 365.62 0.4 366.02 ;
    END
  END window_i[110]
  PIN window_i[111]
    DIRECTION INPUT ;
    USE SIGNAL ;
    PORT
      LAYER Metal3 ;
        RECT  0 368.14 0.4 368.54 ;
    END
  END window_i[111]
  PIN window_i[112]
    DIRECTION INPUT ;
    USE SIGNAL ;
    PORT
      LAYER Metal3 ;
        RECT  0 370.66 0.4 371.06 ;
    END
  END window_i[112]
  PIN window_i[113]
    DIRECTION INPUT ;
    USE SIGNAL ;
    PORT
      LAYER Metal3 ;
        RECT  0 373.18 0.4 373.58 ;
    END
  END window_i[113]
  PIN window_i[114]
    DIRECTION INPUT ;
    USE SIGNAL ;
    PORT
      LAYER Metal3 ;
        RECT  0 375.7 0.4 376.1 ;
    END
  END window_i[114]
  PIN window_i[115]
    DIRECTION INPUT ;
    USE SIGNAL ;
    PORT
      LAYER Metal3 ;
        RECT  0 378.22 0.4 378.62 ;
    END
  END window_i[115]
  PIN window_i[116]
    DIRECTION INPUT ;
    USE SIGNAL ;
    PORT
      LAYER Metal3 ;
        RECT  0 380.74 0.4 381.14 ;
    END
  END window_i[116]
  PIN window_i[117]
    DIRECTION INPUT ;
    USE SIGNAL ;
    PORT
      LAYER Metal3 ;
        RECT  0 383.26 0.4 383.66 ;
    END
  END window_i[117]
  PIN window_i[118]
    DIRECTION INPUT ;
    USE SIGNAL ;
    PORT
      LAYER Metal3 ;
        RECT  0 385.78 0.4 386.18 ;
    END
  END window_i[118]
  PIN window_i[119]
    DIRECTION INPUT ;
    USE SIGNAL ;
    PORT
      LAYER Metal3 ;
        RECT  0 388.3 0.4 388.7 ;
    END
  END window_i[119]
  PIN window_i[11]
    DIRECTION INPUT ;
    USE SIGNAL ;
    PORT
      LAYER Metal3 ;
        RECT  0 116.14 0.4 116.54 ;
    END
  END window_i[11]
  PIN window_i[120]
    DIRECTION INPUT ;
    USE SIGNAL ;
    PORT
      LAYER Metal3 ;
        RECT  0 390.82 0.4 391.22 ;
    END
  END window_i[120]
  PIN window_i[121]
    DIRECTION INPUT ;
    USE SIGNAL ;
    PORT
      LAYER Metal3 ;
        RECT  0 393.34 0.4 393.74 ;
    END
  END window_i[121]
  PIN window_i[122]
    DIRECTION INPUT ;
    USE SIGNAL ;
    PORT
      LAYER Metal3 ;
        RECT  0 395.86 0.4 396.26 ;
    END
  END window_i[122]
  PIN window_i[123]
    DIRECTION INPUT ;
    USE SIGNAL ;
    PORT
      LAYER Metal3 ;
        RECT  0 398.38 0.4 398.78 ;
    END
  END window_i[123]
  PIN window_i[124]
    DIRECTION INPUT ;
    USE SIGNAL ;
    PORT
      LAYER Metal3 ;
        RECT  0 400.9 0.4 401.3 ;
    END
  END window_i[124]
  PIN window_i[125]
    DIRECTION INPUT ;
    USE SIGNAL ;
    PORT
      LAYER Metal3 ;
        RECT  0 403.42 0.4 403.82 ;
    END
  END window_i[125]
  PIN window_i[126]
    DIRECTION INPUT ;
    USE SIGNAL ;
    PORT
      LAYER Metal3 ;
        RECT  0 405.94 0.4 406.34 ;
    END
  END window_i[126]
  PIN window_i[127]
    DIRECTION INPUT ;
    USE SIGNAL ;
    PORT
      LAYER Metal3 ;
        RECT  0 408.46 0.4 408.86 ;
    END
  END window_i[127]
  PIN window_i[128]
    DIRECTION INPUT ;
    USE SIGNAL ;
    PORT
      LAYER Metal3 ;
        RECT  0 410.98 0.4 411.38 ;
    END
  END window_i[128]
  PIN window_i[129]
    DIRECTION INPUT ;
    USE SIGNAL ;
    PORT
      LAYER Metal3 ;
        RECT  0 413.5 0.4 413.9 ;
    END
  END window_i[129]
  PIN window_i[12]
    DIRECTION INPUT ;
    USE SIGNAL ;
    PORT
      LAYER Metal3 ;
        RECT  0 118.66 0.4 119.06 ;
    END
  END window_i[12]
  PIN window_i[130]
    DIRECTION INPUT ;
    USE SIGNAL ;
    PORT
      LAYER Metal3 ;
        RECT  0 416.02 0.4 416.42 ;
    END
  END window_i[130]
  PIN window_i[131]
    DIRECTION INPUT ;
    USE SIGNAL ;
    PORT
      LAYER Metal3 ;
        RECT  0 418.54 0.4 418.94 ;
    END
  END window_i[131]
  PIN window_i[132]
    DIRECTION INPUT ;
    USE SIGNAL ;
    PORT
      LAYER Metal3 ;
        RECT  0 421.06 0.4 421.46 ;
    END
  END window_i[132]
  PIN window_i[133]
    DIRECTION INPUT ;
    USE SIGNAL ;
    PORT
      LAYER Metal3 ;
        RECT  0 423.58 0.4 423.98 ;
    END
  END window_i[133]
  PIN window_i[134]
    DIRECTION INPUT ;
    USE SIGNAL ;
    PORT
      LAYER Metal3 ;
        RECT  0 426.1 0.4 426.5 ;
    END
  END window_i[134]
  PIN window_i[135]
    DIRECTION INPUT ;
    USE SIGNAL ;
    PORT
      LAYER Metal3 ;
        RECT  0 428.62 0.4 429.02 ;
    END
  END window_i[135]
  PIN window_i[136]
    DIRECTION INPUT ;
    USE SIGNAL ;
    PORT
      LAYER Metal3 ;
        RECT  0 431.14 0.4 431.54 ;
    END
  END window_i[136]
  PIN window_i[137]
    DIRECTION INPUT ;
    USE SIGNAL ;
    PORT
      LAYER Metal3 ;
        RECT  0 433.66 0.4 434.06 ;
    END
  END window_i[137]
  PIN window_i[138]
    DIRECTION INPUT ;
    USE SIGNAL ;
    PORT
      LAYER Metal3 ;
        RECT  0 436.18 0.4 436.58 ;
    END
  END window_i[138]
  PIN window_i[139]
    DIRECTION INPUT ;
    USE SIGNAL ;
    PORT
      LAYER Metal3 ;
        RECT  0 438.7 0.4 439.1 ;
    END
  END window_i[139]
  PIN window_i[13]
    DIRECTION INPUT ;
    USE SIGNAL ;
    PORT
      LAYER Metal3 ;
        RECT  0 121.18 0.4 121.58 ;
    END
  END window_i[13]
  PIN window_i[140]
    DIRECTION INPUT ;
    USE SIGNAL ;
    PORT
      LAYER Metal3 ;
        RECT  0 441.22 0.4 441.62 ;
    END
  END window_i[140]
  PIN window_i[141]
    DIRECTION INPUT ;
    USE SIGNAL ;
    PORT
      LAYER Metal3 ;
        RECT  0 443.74 0.4 444.14 ;
    END
  END window_i[141]
  PIN window_i[142]
    DIRECTION INPUT ;
    USE SIGNAL ;
    PORT
      LAYER Metal3 ;
        RECT  0 446.26 0.4 446.66 ;
    END
  END window_i[142]
  PIN window_i[143]
    DIRECTION INPUT ;
    USE SIGNAL ;
    PORT
      LAYER Metal3 ;
        RECT  0 448.78 0.4 449.18 ;
    END
  END window_i[143]
  PIN window_i[144]
    DIRECTION INPUT ;
    USE SIGNAL ;
    PORT
      LAYER Metal3 ;
        RECT  0 451.3 0.4 451.7 ;
    END
  END window_i[144]
  PIN window_i[145]
    DIRECTION INPUT ;
    USE SIGNAL ;
    PORT
      LAYER Metal3 ;
        RECT  0 453.82 0.4 454.22 ;
    END
  END window_i[145]
  PIN window_i[146]
    DIRECTION INPUT ;
    USE SIGNAL ;
    PORT
      LAYER Metal3 ;
        RECT  0 456.34 0.4 456.74 ;
    END
  END window_i[146]
  PIN window_i[147]
    DIRECTION INPUT ;
    USE SIGNAL ;
    PORT
      LAYER Metal3 ;
        RECT  0 458.86 0.4 459.26 ;
    END
  END window_i[147]
  PIN window_i[148]
    DIRECTION INPUT ;
    USE SIGNAL ;
    PORT
      LAYER Metal3 ;
        RECT  0 461.38 0.4 461.78 ;
    END
  END window_i[148]
  PIN window_i[149]
    DIRECTION INPUT ;
    USE SIGNAL ;
    PORT
      LAYER Metal3 ;
        RECT  0 463.9 0.4 464.3 ;
    END
  END window_i[149]
  PIN window_i[14]
    DIRECTION INPUT ;
    USE SIGNAL ;
    PORT
      LAYER Metal3 ;
        RECT  0 123.7 0.4 124.1 ;
    END
  END window_i[14]
  PIN window_i[150]
    DIRECTION INPUT ;
    USE SIGNAL ;
    PORT
      LAYER Metal3 ;
        RECT  0 466.42 0.4 466.82 ;
    END
  END window_i[150]
  PIN window_i[151]
    DIRECTION INPUT ;
    USE SIGNAL ;
    PORT
      LAYER Metal3 ;
        RECT  0 468.94 0.4 469.34 ;
    END
  END window_i[151]
  PIN window_i[152]
    DIRECTION INPUT ;
    USE SIGNAL ;
    PORT
      LAYER Metal3 ;
        RECT  0 471.46 0.4 471.86 ;
    END
  END window_i[152]
  PIN window_i[153]
    DIRECTION INPUT ;
    USE SIGNAL ;
    PORT
      LAYER Metal3 ;
        RECT  0 473.98 0.4 474.38 ;
    END
  END window_i[153]
  PIN window_i[154]
    DIRECTION INPUT ;
    USE SIGNAL ;
    PORT
      LAYER Metal3 ;
        RECT  0 476.5 0.4 476.9 ;
    END
  END window_i[154]
  PIN window_i[155]
    DIRECTION INPUT ;
    USE SIGNAL ;
    PORT
      LAYER Metal3 ;
        RECT  0 479.02 0.4 479.42 ;
    END
  END window_i[155]
  PIN window_i[156]
    DIRECTION INPUT ;
    USE SIGNAL ;
    PORT
      LAYER Metal3 ;
        RECT  0 481.54 0.4 481.94 ;
    END
  END window_i[156]
  PIN window_i[157]
    DIRECTION INPUT ;
    USE SIGNAL ;
    PORT
      LAYER Metal3 ;
        RECT  0 484.06 0.4 484.46 ;
    END
  END window_i[157]
  PIN window_i[158]
    DIRECTION INPUT ;
    USE SIGNAL ;
    PORT
      LAYER Metal3 ;
        RECT  0 486.58 0.4 486.98 ;
    END
  END window_i[158]
  PIN window_i[159]
    DIRECTION INPUT ;
    USE SIGNAL ;
    PORT
      LAYER Metal3 ;
        RECT  0 489.1 0.4 489.5 ;
    END
  END window_i[159]
  PIN window_i[15]
    DIRECTION INPUT ;
    USE SIGNAL ;
    PORT
      LAYER Metal3 ;
        RECT  0 126.22 0.4 126.62 ;
    END
  END window_i[15]
  PIN window_i[160]
    DIRECTION INPUT ;
    USE SIGNAL ;
    PORT
      LAYER Metal3 ;
        RECT  0 491.62 0.4 492.02 ;
    END
  END window_i[160]
  PIN window_i[161]
    DIRECTION INPUT ;
    USE SIGNAL ;
    PORT
      LAYER Metal3 ;
        RECT  0 494.14 0.4 494.54 ;
    END
  END window_i[161]
  PIN window_i[162]
    DIRECTION INPUT ;
    USE SIGNAL ;
    PORT
      LAYER Metal3 ;
        RECT  0 496.66 0.4 497.06 ;
    END
  END window_i[162]
  PIN window_i[163]
    DIRECTION INPUT ;
    USE SIGNAL ;
    PORT
      LAYER Metal3 ;
        RECT  0 499.18 0.4 499.58 ;
    END
  END window_i[163]
  PIN window_i[164]
    DIRECTION INPUT ;
    USE SIGNAL ;
    PORT
      LAYER Metal3 ;
        RECT  0 501.7 0.4 502.1 ;
    END
  END window_i[164]
  PIN window_i[165]
    DIRECTION INPUT ;
    USE SIGNAL ;
    PORT
      LAYER Metal3 ;
        RECT  0 504.22 0.4 504.62 ;
    END
  END window_i[165]
  PIN window_i[166]
    DIRECTION INPUT ;
    USE SIGNAL ;
    PORT
      LAYER Metal3 ;
        RECT  0 506.74 0.4 507.14 ;
    END
  END window_i[166]
  PIN window_i[167]
    DIRECTION INPUT ;
    USE SIGNAL ;
    PORT
      LAYER Metal3 ;
        RECT  0 509.26 0.4 509.66 ;
    END
  END window_i[167]
  PIN window_i[168]
    DIRECTION INPUT ;
    USE SIGNAL ;
    PORT
      LAYER Metal3 ;
        RECT  0 511.78 0.4 512.18 ;
    END
  END window_i[168]
  PIN window_i[169]
    DIRECTION INPUT ;
    USE SIGNAL ;
    PORT
      LAYER Metal3 ;
        RECT  0 514.3 0.4 514.7 ;
    END
  END window_i[169]
  PIN window_i[16]
    DIRECTION INPUT ;
    USE SIGNAL ;
    PORT
      LAYER Metal3 ;
        RECT  0 128.74 0.4 129.14 ;
    END
  END window_i[16]
  PIN window_i[170]
    DIRECTION INPUT ;
    USE SIGNAL ;
    PORT
      LAYER Metal3 ;
        RECT  0 516.82 0.4 517.22 ;
    END
  END window_i[170]
  PIN window_i[171]
    DIRECTION INPUT ;
    USE SIGNAL ;
    PORT
      LAYER Metal3 ;
        RECT  0 519.34 0.4 519.74 ;
    END
  END window_i[171]
  PIN window_i[172]
    DIRECTION INPUT ;
    USE SIGNAL ;
    PORT
      LAYER Metal3 ;
        RECT  0 521.86 0.4 522.26 ;
    END
  END window_i[172]
  PIN window_i[173]
    DIRECTION INPUT ;
    USE SIGNAL ;
    PORT
      LAYER Metal3 ;
        RECT  0 524.38 0.4 524.78 ;
    END
  END window_i[173]
  PIN window_i[174]
    DIRECTION INPUT ;
    USE SIGNAL ;
    PORT
      LAYER Metal3 ;
        RECT  0 526.9 0.4 527.3 ;
    END
  END window_i[174]
  PIN window_i[175]
    DIRECTION INPUT ;
    USE SIGNAL ;
    PORT
      LAYER Metal3 ;
        RECT  0 529.42 0.4 529.82 ;
    END
  END window_i[175]
  PIN window_i[176]
    DIRECTION INPUT ;
    USE SIGNAL ;
    PORT
      LAYER Metal3 ;
        RECT  0 531.94 0.4 532.34 ;
    END
  END window_i[176]
  PIN window_i[177]
    DIRECTION INPUT ;
    USE SIGNAL ;
    PORT
      LAYER Metal3 ;
        RECT  0 534.46 0.4 534.86 ;
    END
  END window_i[177]
  PIN window_i[178]
    DIRECTION INPUT ;
    USE SIGNAL ;
    PORT
      LAYER Metal3 ;
        RECT  0 536.98 0.4 537.38 ;
    END
  END window_i[178]
  PIN window_i[179]
    DIRECTION INPUT ;
    USE SIGNAL ;
    PORT
      LAYER Metal3 ;
        RECT  0 539.5 0.4 539.9 ;
    END
  END window_i[179]
  PIN window_i[17]
    DIRECTION INPUT ;
    USE SIGNAL ;
    PORT
      LAYER Metal3 ;
        RECT  0 131.26 0.4 131.66 ;
    END
  END window_i[17]
  PIN window_i[180]
    DIRECTION INPUT ;
    USE SIGNAL ;
    PORT
      LAYER Metal3 ;
        RECT  0 542.02 0.4 542.42 ;
    END
  END window_i[180]
  PIN window_i[181]
    DIRECTION INPUT ;
    USE SIGNAL ;
    PORT
      LAYER Metal3 ;
        RECT  0 544.54 0.4 544.94 ;
    END
  END window_i[181]
  PIN window_i[182]
    DIRECTION INPUT ;
    USE SIGNAL ;
    PORT
      LAYER Metal3 ;
        RECT  0 547.06 0.4 547.46 ;
    END
  END window_i[182]
  PIN window_i[183]
    DIRECTION INPUT ;
    USE SIGNAL ;
    PORT
      LAYER Metal3 ;
        RECT  0 549.58 0.4 549.98 ;
    END
  END window_i[183]
  PIN window_i[184]
    DIRECTION INPUT ;
    USE SIGNAL ;
    PORT
      LAYER Metal3 ;
        RECT  0 552.1 0.4 552.5 ;
    END
  END window_i[184]
  PIN window_i[185]
    DIRECTION INPUT ;
    USE SIGNAL ;
    PORT
      LAYER Metal3 ;
        RECT  0 554.62 0.4 555.02 ;
    END
  END window_i[185]
  PIN window_i[186]
    DIRECTION INPUT ;
    USE SIGNAL ;
    PORT
      LAYER Metal3 ;
        RECT  0 557.14 0.4 557.54 ;
    END
  END window_i[186]
  PIN window_i[187]
    DIRECTION INPUT ;
    USE SIGNAL ;
    PORT
      LAYER Metal3 ;
        RECT  0 559.66 0.4 560.06 ;
    END
  END window_i[187]
  PIN window_i[188]
    DIRECTION INPUT ;
    USE SIGNAL ;
    PORT
      LAYER Metal3 ;
        RECT  0 562.18 0.4 562.58 ;
    END
  END window_i[188]
  PIN window_i[189]
    DIRECTION INPUT ;
    USE SIGNAL ;
    PORT
      LAYER Metal3 ;
        RECT  0 564.7 0.4 565.1 ;
    END
  END window_i[189]
  PIN window_i[18]
    DIRECTION INPUT ;
    USE SIGNAL ;
    PORT
      LAYER Metal3 ;
        RECT  0 133.78 0.4 134.18 ;
    END
  END window_i[18]
  PIN window_i[190]
    DIRECTION INPUT ;
    USE SIGNAL ;
    PORT
      LAYER Metal3 ;
        RECT  0 567.22 0.4 567.62 ;
    END
  END window_i[190]
  PIN window_i[191]
    DIRECTION INPUT ;
    USE SIGNAL ;
    PORT
      LAYER Metal3 ;
        RECT  0 569.74 0.4 570.14 ;
    END
  END window_i[191]
  PIN window_i[192]
    DIRECTION INPUT ;
    USE SIGNAL ;
    PORT
      LAYER Metal3 ;
        RECT  0 572.26 0.4 572.66 ;
    END
  END window_i[192]
  PIN window_i[193]
    DIRECTION INPUT ;
    USE SIGNAL ;
    PORT
      LAYER Metal3 ;
        RECT  0 574.78 0.4 575.18 ;
    END
  END window_i[193]
  PIN window_i[194]
    DIRECTION INPUT ;
    USE SIGNAL ;
    PORT
      LAYER Metal3 ;
        RECT  0 577.3 0.4 577.7 ;
    END
  END window_i[194]
  PIN window_i[195]
    DIRECTION INPUT ;
    USE SIGNAL ;
    PORT
      LAYER Metal3 ;
        RECT  0 579.82 0.4 580.22 ;
    END
  END window_i[195]
  PIN window_i[196]
    DIRECTION INPUT ;
    USE SIGNAL ;
    PORT
      LAYER Metal3 ;
        RECT  0 582.34 0.4 582.74 ;
    END
  END window_i[196]
  PIN window_i[197]
    DIRECTION INPUT ;
    USE SIGNAL ;
    PORT
      LAYER Metal3 ;
        RECT  0 584.86 0.4 585.26 ;
    END
  END window_i[197]
  PIN window_i[198]
    DIRECTION INPUT ;
    USE SIGNAL ;
    PORT
      LAYER Metal3 ;
        RECT  0 587.38 0.4 587.78 ;
    END
  END window_i[198]
  PIN window_i[199]
    DIRECTION INPUT ;
    USE SIGNAL ;
    PORT
      LAYER Metal3 ;
        RECT  0 589.9 0.4 590.3 ;
    END
  END window_i[199]
  PIN window_i[19]
    DIRECTION INPUT ;
    USE SIGNAL ;
    PORT
      LAYER Metal3 ;
        RECT  0 136.3 0.4 136.7 ;
    END
  END window_i[19]
  PIN window_i[1]
    DIRECTION INPUT ;
    USE SIGNAL ;
    PORT
      LAYER Metal3 ;
        RECT  0 90.94 0.4 91.34 ;
    END
  END window_i[1]
  PIN window_i[200]
    DIRECTION INPUT ;
    USE SIGNAL ;
    PORT
      LAYER Metal3 ;
        RECT  0 592.42 0.4 592.82 ;
    END
  END window_i[200]
  PIN window_i[201]
    DIRECTION INPUT ;
    USE SIGNAL ;
    PORT
      LAYER Metal3 ;
        RECT  0 594.94 0.4 595.34 ;
    END
  END window_i[201]
  PIN window_i[202]
    DIRECTION INPUT ;
    USE SIGNAL ;
    PORT
      LAYER Metal3 ;
        RECT  0 597.46 0.4 597.86 ;
    END
  END window_i[202]
  PIN window_i[203]
    DIRECTION INPUT ;
    USE SIGNAL ;
    PORT
      LAYER Metal3 ;
        RECT  0 599.98 0.4 600.38 ;
    END
  END window_i[203]
  PIN window_i[204]
    DIRECTION INPUT ;
    USE SIGNAL ;
    PORT
      LAYER Metal3 ;
        RECT  0 602.5 0.4 602.9 ;
    END
  END window_i[204]
  PIN window_i[205]
    DIRECTION INPUT ;
    USE SIGNAL ;
    PORT
      LAYER Metal3 ;
        RECT  0 605.02 0.4 605.42 ;
    END
  END window_i[205]
  PIN window_i[206]
    DIRECTION INPUT ;
    USE SIGNAL ;
    PORT
      LAYER Metal3 ;
        RECT  0 607.54 0.4 607.94 ;
    END
  END window_i[206]
  PIN window_i[207]
    DIRECTION INPUT ;
    USE SIGNAL ;
    PORT
      LAYER Metal3 ;
        RECT  0 610.06 0.4 610.46 ;
    END
  END window_i[207]
  PIN window_i[208]
    DIRECTION INPUT ;
    USE SIGNAL ;
    PORT
      LAYER Metal3 ;
        RECT  0 612.58 0.4 612.98 ;
    END
  END window_i[208]
  PIN window_i[209]
    DIRECTION INPUT ;
    USE SIGNAL ;
    PORT
      LAYER Metal3 ;
        RECT  0 615.1 0.4 615.5 ;
    END
  END window_i[209]
  PIN window_i[20]
    DIRECTION INPUT ;
    USE SIGNAL ;
    PORT
      LAYER Metal3 ;
        RECT  0 138.82 0.4 139.22 ;
    END
  END window_i[20]
  PIN window_i[210]
    DIRECTION INPUT ;
    USE SIGNAL ;
    PORT
      LAYER Metal3 ;
        RECT  0 617.62 0.4 618.02 ;
    END
  END window_i[210]
  PIN window_i[211]
    DIRECTION INPUT ;
    USE SIGNAL ;
    PORT
      LAYER Metal3 ;
        RECT  0 620.14 0.4 620.54 ;
    END
  END window_i[211]
  PIN window_i[212]
    DIRECTION INPUT ;
    USE SIGNAL ;
    PORT
      LAYER Metal3 ;
        RECT  0 622.66 0.4 623.06 ;
    END
  END window_i[212]
  PIN window_i[213]
    DIRECTION INPUT ;
    USE SIGNAL ;
    PORT
      LAYER Metal3 ;
        RECT  0 625.18 0.4 625.58 ;
    END
  END window_i[213]
  PIN window_i[214]
    DIRECTION INPUT ;
    USE SIGNAL ;
    PORT
      LAYER Metal3 ;
        RECT  0 627.7 0.4 628.1 ;
    END
  END window_i[214]
  PIN window_i[215]
    DIRECTION INPUT ;
    USE SIGNAL ;
    PORT
      LAYER Metal3 ;
        RECT  0 630.22 0.4 630.62 ;
    END
  END window_i[215]
  PIN window_i[216]
    DIRECTION INPUT ;
    USE SIGNAL ;
    PORT
      LAYER Metal3 ;
        RECT  0 632.74 0.4 633.14 ;
    END
  END window_i[216]
  PIN window_i[217]
    DIRECTION INPUT ;
    USE SIGNAL ;
    PORT
      LAYER Metal3 ;
        RECT  0 635.26 0.4 635.66 ;
    END
  END window_i[217]
  PIN window_i[218]
    DIRECTION INPUT ;
    USE SIGNAL ;
    PORT
      LAYER Metal3 ;
        RECT  0 637.78 0.4 638.18 ;
    END
  END window_i[218]
  PIN window_i[219]
    DIRECTION INPUT ;
    USE SIGNAL ;
    PORT
      LAYER Metal3 ;
        RECT  0 640.3 0.4 640.7 ;
    END
  END window_i[219]
  PIN window_i[21]
    DIRECTION INPUT ;
    USE SIGNAL ;
    PORT
      LAYER Metal3 ;
        RECT  0 141.34 0.4 141.74 ;
    END
  END window_i[21]
  PIN window_i[220]
    DIRECTION INPUT ;
    USE SIGNAL ;
    PORT
      LAYER Metal3 ;
        RECT  0 642.82 0.4 643.22 ;
    END
  END window_i[220]
  PIN window_i[221]
    DIRECTION INPUT ;
    USE SIGNAL ;
    PORT
      LAYER Metal3 ;
        RECT  0 645.34 0.4 645.74 ;
    END
  END window_i[221]
  PIN window_i[222]
    DIRECTION INPUT ;
    USE SIGNAL ;
    PORT
      LAYER Metal3 ;
        RECT  0 647.86 0.4 648.26 ;
    END
  END window_i[222]
  PIN window_i[223]
    DIRECTION INPUT ;
    USE SIGNAL ;
    PORT
      LAYER Metal3 ;
        RECT  0 650.38 0.4 650.78 ;
    END
  END window_i[223]
  PIN window_i[224]
    DIRECTION INPUT ;
    USE SIGNAL ;
    PORT
      LAYER Metal3 ;
        RECT  0 652.9 0.4 653.3 ;
    END
  END window_i[224]
  PIN window_i[225]
    DIRECTION INPUT ;
    USE SIGNAL ;
    PORT
      LAYER Metal3 ;
        RECT  0 655.42 0.4 655.82 ;
    END
  END window_i[225]
  PIN window_i[226]
    DIRECTION INPUT ;
    USE SIGNAL ;
    PORT
      LAYER Metal3 ;
        RECT  0 657.94 0.4 658.34 ;
    END
  END window_i[226]
  PIN window_i[227]
    DIRECTION INPUT ;
    USE SIGNAL ;
    PORT
      LAYER Metal3 ;
        RECT  0 660.46 0.4 660.86 ;
    END
  END window_i[227]
  PIN window_i[228]
    DIRECTION INPUT ;
    USE SIGNAL ;
    PORT
      LAYER Metal3 ;
        RECT  0 662.98 0.4 663.38 ;
    END
  END window_i[228]
  PIN window_i[229]
    DIRECTION INPUT ;
    USE SIGNAL ;
    PORT
      LAYER Metal3 ;
        RECT  0 665.5 0.4 665.9 ;
    END
  END window_i[229]
  PIN window_i[22]
    DIRECTION INPUT ;
    USE SIGNAL ;
    PORT
      LAYER Metal3 ;
        RECT  0 143.86 0.4 144.26 ;
    END
  END window_i[22]
  PIN window_i[230]
    DIRECTION INPUT ;
    USE SIGNAL ;
    PORT
      LAYER Metal3 ;
        RECT  0 668.02 0.4 668.42 ;
    END
  END window_i[230]
  PIN window_i[231]
    DIRECTION INPUT ;
    USE SIGNAL ;
    PORT
      LAYER Metal3 ;
        RECT  0 670.54 0.4 670.94 ;
    END
  END window_i[231]
  PIN window_i[232]
    DIRECTION INPUT ;
    USE SIGNAL ;
    PORT
      LAYER Metal3 ;
        RECT  0 673.06 0.4 673.46 ;
    END
  END window_i[232]
  PIN window_i[233]
    DIRECTION INPUT ;
    USE SIGNAL ;
    PORT
      LAYER Metal3 ;
        RECT  0 675.58 0.4 675.98 ;
    END
  END window_i[233]
  PIN window_i[234]
    DIRECTION INPUT ;
    USE SIGNAL ;
    PORT
      LAYER Metal3 ;
        RECT  0 678.1 0.4 678.5 ;
    END
  END window_i[234]
  PIN window_i[235]
    DIRECTION INPUT ;
    USE SIGNAL ;
    PORT
      LAYER Metal3 ;
        RECT  0 680.62 0.4 681.02 ;
    END
  END window_i[235]
  PIN window_i[236]
    DIRECTION INPUT ;
    USE SIGNAL ;
    PORT
      LAYER Metal3 ;
        RECT  0 683.14 0.4 683.54 ;
    END
  END window_i[236]
  PIN window_i[237]
    DIRECTION INPUT ;
    USE SIGNAL ;
    PORT
      LAYER Metal3 ;
        RECT  0 685.66 0.4 686.06 ;
    END
  END window_i[237]
  PIN window_i[238]
    DIRECTION INPUT ;
    USE SIGNAL ;
    PORT
      LAYER Metal3 ;
        RECT  0 688.18 0.4 688.58 ;
    END
  END window_i[238]
  PIN window_i[239]
    DIRECTION INPUT ;
    USE SIGNAL ;
    PORT
      LAYER Metal3 ;
        RECT  0 690.7 0.4 691.1 ;
    END
  END window_i[239]
  PIN window_i[23]
    DIRECTION INPUT ;
    USE SIGNAL ;
    PORT
      LAYER Metal3 ;
        RECT  0 146.38 0.4 146.78 ;
    END
  END window_i[23]
  PIN window_i[240]
    DIRECTION INPUT ;
    USE SIGNAL ;
    PORT
      LAYER Metal3 ;
        RECT  0 693.22 0.4 693.62 ;
    END
  END window_i[240]
  PIN window_i[241]
    DIRECTION INPUT ;
    USE SIGNAL ;
    PORT
      LAYER Metal3 ;
        RECT  0 695.74 0.4 696.14 ;
    END
  END window_i[241]
  PIN window_i[242]
    DIRECTION INPUT ;
    USE SIGNAL ;
    PORT
      LAYER Metal3 ;
        RECT  0 698.26 0.4 698.66 ;
    END
  END window_i[242]
  PIN window_i[243]
    DIRECTION INPUT ;
    USE SIGNAL ;
    PORT
      LAYER Metal3 ;
        RECT  0 700.78 0.4 701.18 ;
    END
  END window_i[243]
  PIN window_i[244]
    DIRECTION INPUT ;
    USE SIGNAL ;
    PORT
      LAYER Metal3 ;
        RECT  0 703.3 0.4 703.7 ;
    END
  END window_i[244]
  PIN window_i[245]
    DIRECTION INPUT ;
    USE SIGNAL ;
    PORT
      LAYER Metal3 ;
        RECT  0 705.82 0.4 706.22 ;
    END
  END window_i[245]
  PIN window_i[246]
    DIRECTION INPUT ;
    USE SIGNAL ;
    PORT
      LAYER Metal3 ;
        RECT  0 708.34 0.4 708.74 ;
    END
  END window_i[246]
  PIN window_i[247]
    DIRECTION INPUT ;
    USE SIGNAL ;
    PORT
      LAYER Metal3 ;
        RECT  0 710.86 0.4 711.26 ;
    END
  END window_i[247]
  PIN window_i[248]
    DIRECTION INPUT ;
    USE SIGNAL ;
    PORT
      LAYER Metal3 ;
        RECT  0 713.38 0.4 713.78 ;
    END
  END window_i[248]
  PIN window_i[249]
    DIRECTION INPUT ;
    USE SIGNAL ;
    PORT
      LAYER Metal3 ;
        RECT  0 715.9 0.4 716.3 ;
    END
  END window_i[249]
  PIN window_i[24]
    DIRECTION INPUT ;
    USE SIGNAL ;
    PORT
      LAYER Metal3 ;
        RECT  0 148.9 0.4 149.3 ;
    END
  END window_i[24]
  PIN window_i[250]
    DIRECTION INPUT ;
    USE SIGNAL ;
    PORT
      LAYER Metal3 ;
        RECT  0 718.42 0.4 718.82 ;
    END
  END window_i[250]
  PIN window_i[251]
    DIRECTION INPUT ;
    USE SIGNAL ;
    PORT
      LAYER Metal3 ;
        RECT  0 720.94 0.4 721.34 ;
    END
  END window_i[251]
  PIN window_i[252]
    DIRECTION INPUT ;
    USE SIGNAL ;
    PORT
      LAYER Metal3 ;
        RECT  0 723.46 0.4 723.86 ;
    END
  END window_i[252]
  PIN window_i[253]
    DIRECTION INPUT ;
    USE SIGNAL ;
    PORT
      LAYER Metal3 ;
        RECT  0 725.98 0.4 726.38 ;
    END
  END window_i[253]
  PIN window_i[254]
    DIRECTION INPUT ;
    USE SIGNAL ;
    PORT
      LAYER Metal3 ;
        RECT  0 728.5 0.4 728.9 ;
    END
  END window_i[254]
  PIN window_i[255]
    DIRECTION INPUT ;
    USE SIGNAL ;
    PORT
      LAYER Metal3 ;
        RECT  0 731.02 0.4 731.42 ;
    END
  END window_i[255]
  PIN window_i[25]
    DIRECTION INPUT ;
    USE SIGNAL ;
    PORT
      LAYER Metal3 ;
        RECT  0 151.42 0.4 151.82 ;
    END
  END window_i[25]
  PIN window_i[26]
    DIRECTION INPUT ;
    USE SIGNAL ;
    PORT
      LAYER Metal3 ;
        RECT  0 153.94 0.4 154.34 ;
    END
  END window_i[26]
  PIN window_i[27]
    DIRECTION INPUT ;
    USE SIGNAL ;
    PORT
      LAYER Metal3 ;
        RECT  0 156.46 0.4 156.86 ;
    END
  END window_i[27]
  PIN window_i[28]
    DIRECTION INPUT ;
    USE SIGNAL ;
    PORT
      LAYER Metal3 ;
        RECT  0 158.98 0.4 159.38 ;
    END
  END window_i[28]
  PIN window_i[29]
    DIRECTION INPUT ;
    USE SIGNAL ;
    PORT
      LAYER Metal3 ;
        RECT  0 161.5 0.4 161.9 ;
    END
  END window_i[29]
  PIN window_i[2]
    DIRECTION INPUT ;
    USE SIGNAL ;
    PORT
      LAYER Metal3 ;
        RECT  0 93.46 0.4 93.86 ;
    END
  END window_i[2]
  PIN window_i[30]
    DIRECTION INPUT ;
    USE SIGNAL ;
    PORT
      LAYER Metal3 ;
        RECT  0 164.02 0.4 164.42 ;
    END
  END window_i[30]
  PIN window_i[31]
    DIRECTION INPUT ;
    USE SIGNAL ;
    PORT
      LAYER Metal3 ;
        RECT  0 166.54 0.4 166.94 ;
    END
  END window_i[31]
  PIN window_i[32]
    DIRECTION INPUT ;
    USE SIGNAL ;
    PORT
      LAYER Metal3 ;
        RECT  0 169.06 0.4 169.46 ;
    END
  END window_i[32]
  PIN window_i[33]
    DIRECTION INPUT ;
    USE SIGNAL ;
    PORT
      LAYER Metal3 ;
        RECT  0 171.58 0.4 171.98 ;
    END
  END window_i[33]
  PIN window_i[34]
    DIRECTION INPUT ;
    USE SIGNAL ;
    PORT
      LAYER Metal3 ;
        RECT  0 174.1 0.4 174.5 ;
    END
  END window_i[34]
  PIN window_i[35]
    DIRECTION INPUT ;
    USE SIGNAL ;
    PORT
      LAYER Metal3 ;
        RECT  0 176.62 0.4 177.02 ;
    END
  END window_i[35]
  PIN window_i[36]
    DIRECTION INPUT ;
    USE SIGNAL ;
    PORT
      LAYER Metal3 ;
        RECT  0 179.14 0.4 179.54 ;
    END
  END window_i[36]
  PIN window_i[37]
    DIRECTION INPUT ;
    USE SIGNAL ;
    PORT
      LAYER Metal3 ;
        RECT  0 181.66 0.4 182.06 ;
    END
  END window_i[37]
  PIN window_i[38]
    DIRECTION INPUT ;
    USE SIGNAL ;
    PORT
      LAYER Metal3 ;
        RECT  0 184.18 0.4 184.58 ;
    END
  END window_i[38]
  PIN window_i[39]
    DIRECTION INPUT ;
    USE SIGNAL ;
    PORT
      LAYER Metal3 ;
        RECT  0 186.7 0.4 187.1 ;
    END
  END window_i[39]
  PIN window_i[3]
    DIRECTION INPUT ;
    USE SIGNAL ;
    PORT
      LAYER Metal3 ;
        RECT  0 95.98 0.4 96.38 ;
    END
  END window_i[3]
  PIN window_i[40]
    DIRECTION INPUT ;
    USE SIGNAL ;
    PORT
      LAYER Metal3 ;
        RECT  0 189.22 0.4 189.62 ;
    END
  END window_i[40]
  PIN window_i[41]
    DIRECTION INPUT ;
    USE SIGNAL ;
    PORT
      LAYER Metal3 ;
        RECT  0 191.74 0.4 192.14 ;
    END
  END window_i[41]
  PIN window_i[42]
    DIRECTION INPUT ;
    USE SIGNAL ;
    PORT
      LAYER Metal3 ;
        RECT  0 194.26 0.4 194.66 ;
    END
  END window_i[42]
  PIN window_i[43]
    DIRECTION INPUT ;
    USE SIGNAL ;
    PORT
      LAYER Metal3 ;
        RECT  0 196.78 0.4 197.18 ;
    END
  END window_i[43]
  PIN window_i[44]
    DIRECTION INPUT ;
    USE SIGNAL ;
    PORT
      LAYER Metal3 ;
        RECT  0 199.3 0.4 199.7 ;
    END
  END window_i[44]
  PIN window_i[45]
    DIRECTION INPUT ;
    USE SIGNAL ;
    PORT
      LAYER Metal3 ;
        RECT  0 201.82 0.4 202.22 ;
    END
  END window_i[45]
  PIN window_i[46]
    DIRECTION INPUT ;
    USE SIGNAL ;
    PORT
      LAYER Metal3 ;
        RECT  0 204.34 0.4 204.74 ;
    END
  END window_i[46]
  PIN window_i[47]
    DIRECTION INPUT ;
    USE SIGNAL ;
    PORT
      LAYER Metal3 ;
        RECT  0 206.86 0.4 207.26 ;
    END
  END window_i[47]
  PIN window_i[48]
    DIRECTION INPUT ;
    USE SIGNAL ;
    PORT
      LAYER Metal3 ;
        RECT  0 209.38 0.4 209.78 ;
    END
  END window_i[48]
  PIN window_i[49]
    DIRECTION INPUT ;
    USE SIGNAL ;
    PORT
      LAYER Metal3 ;
        RECT  0 211.9 0.4 212.3 ;
    END
  END window_i[49]
  PIN window_i[4]
    DIRECTION INPUT ;
    USE SIGNAL ;
    PORT
      LAYER Metal3 ;
        RECT  0 98.5 0.4 98.9 ;
    END
  END window_i[4]
  PIN window_i[50]
    DIRECTION INPUT ;
    USE SIGNAL ;
    PORT
      LAYER Metal3 ;
        RECT  0 214.42 0.4 214.82 ;
    END
  END window_i[50]
  PIN window_i[51]
    DIRECTION INPUT ;
    USE SIGNAL ;
    PORT
      LAYER Metal3 ;
        RECT  0 216.94 0.4 217.34 ;
    END
  END window_i[51]
  PIN window_i[52]
    DIRECTION INPUT ;
    USE SIGNAL ;
    PORT
      LAYER Metal3 ;
        RECT  0 219.46 0.4 219.86 ;
    END
  END window_i[52]
  PIN window_i[53]
    DIRECTION INPUT ;
    USE SIGNAL ;
    PORT
      LAYER Metal3 ;
        RECT  0 221.98 0.4 222.38 ;
    END
  END window_i[53]
  PIN window_i[54]
    DIRECTION INPUT ;
    USE SIGNAL ;
    PORT
      LAYER Metal3 ;
        RECT  0 224.5 0.4 224.9 ;
    END
  END window_i[54]
  PIN window_i[55]
    DIRECTION INPUT ;
    USE SIGNAL ;
    PORT
      LAYER Metal3 ;
        RECT  0 227.02 0.4 227.42 ;
    END
  END window_i[55]
  PIN window_i[56]
    DIRECTION INPUT ;
    USE SIGNAL ;
    PORT
      LAYER Metal3 ;
        RECT  0 229.54 0.4 229.94 ;
    END
  END window_i[56]
  PIN window_i[57]
    DIRECTION INPUT ;
    USE SIGNAL ;
    PORT
      LAYER Metal3 ;
        RECT  0 232.06 0.4 232.46 ;
    END
  END window_i[57]
  PIN window_i[58]
    DIRECTION INPUT ;
    USE SIGNAL ;
    PORT
      LAYER Metal3 ;
        RECT  0 234.58 0.4 234.98 ;
    END
  END window_i[58]
  PIN window_i[59]
    DIRECTION INPUT ;
    USE SIGNAL ;
    PORT
      LAYER Metal3 ;
        RECT  0 237.1 0.4 237.5 ;
    END
  END window_i[59]
  PIN window_i[5]
    DIRECTION INPUT ;
    USE SIGNAL ;
    PORT
      LAYER Metal3 ;
        RECT  0 101.02 0.4 101.42 ;
    END
  END window_i[5]
  PIN window_i[60]
    DIRECTION INPUT ;
    USE SIGNAL ;
    PORT
      LAYER Metal3 ;
        RECT  0 239.62 0.4 240.02 ;
    END
  END window_i[60]
  PIN window_i[61]
    DIRECTION INPUT ;
    USE SIGNAL ;
    PORT
      LAYER Metal3 ;
        RECT  0 242.14 0.4 242.54 ;
    END
  END window_i[61]
  PIN window_i[62]
    DIRECTION INPUT ;
    USE SIGNAL ;
    PORT
      LAYER Metal3 ;
        RECT  0 244.66 0.4 245.06 ;
    END
  END window_i[62]
  PIN window_i[63]
    DIRECTION INPUT ;
    USE SIGNAL ;
    PORT
      LAYER Metal3 ;
        RECT  0 247.18 0.4 247.58 ;
    END
  END window_i[63]
  PIN window_i[64]
    DIRECTION INPUT ;
    USE SIGNAL ;
    PORT
      LAYER Metal3 ;
        RECT  0 249.7 0.4 250.1 ;
    END
  END window_i[64]
  PIN window_i[65]
    DIRECTION INPUT ;
    USE SIGNAL ;
    PORT
      LAYER Metal3 ;
        RECT  0 252.22 0.4 252.62 ;
    END
  END window_i[65]
  PIN window_i[66]
    DIRECTION INPUT ;
    USE SIGNAL ;
    PORT
      LAYER Metal3 ;
        RECT  0 254.74 0.4 255.14 ;
    END
  END window_i[66]
  PIN window_i[67]
    DIRECTION INPUT ;
    USE SIGNAL ;
    PORT
      LAYER Metal3 ;
        RECT  0 257.26 0.4 257.66 ;
    END
  END window_i[67]
  PIN window_i[68]
    DIRECTION INPUT ;
    USE SIGNAL ;
    PORT
      LAYER Metal3 ;
        RECT  0 259.78 0.4 260.18 ;
    END
  END window_i[68]
  PIN window_i[69]
    DIRECTION INPUT ;
    USE SIGNAL ;
    PORT
      LAYER Metal3 ;
        RECT  0 262.3 0.4 262.7 ;
    END
  END window_i[69]
  PIN window_i[6]
    DIRECTION INPUT ;
    USE SIGNAL ;
    PORT
      LAYER Metal3 ;
        RECT  0 103.54 0.4 103.94 ;
    END
  END window_i[6]
  PIN window_i[70]
    DIRECTION INPUT ;
    USE SIGNAL ;
    PORT
      LAYER Metal3 ;
        RECT  0 264.82 0.4 265.22 ;
    END
  END window_i[70]
  PIN window_i[71]
    DIRECTION INPUT ;
    USE SIGNAL ;
    PORT
      LAYER Metal3 ;
        RECT  0 267.34 0.4 267.74 ;
    END
  END window_i[71]
  PIN window_i[72]
    DIRECTION INPUT ;
    USE SIGNAL ;
    PORT
      LAYER Metal3 ;
        RECT  0 269.86 0.4 270.26 ;
    END
  END window_i[72]
  PIN window_i[73]
    DIRECTION INPUT ;
    USE SIGNAL ;
    PORT
      LAYER Metal3 ;
        RECT  0 272.38 0.4 272.78 ;
    END
  END window_i[73]
  PIN window_i[74]
    DIRECTION INPUT ;
    USE SIGNAL ;
    PORT
      LAYER Metal3 ;
        RECT  0 274.9 0.4 275.3 ;
    END
  END window_i[74]
  PIN window_i[75]
    DIRECTION INPUT ;
    USE SIGNAL ;
    PORT
      LAYER Metal3 ;
        RECT  0 277.42 0.4 277.82 ;
    END
  END window_i[75]
  PIN window_i[76]
    DIRECTION INPUT ;
    USE SIGNAL ;
    PORT
      LAYER Metal3 ;
        RECT  0 279.94 0.4 280.34 ;
    END
  END window_i[76]
  PIN window_i[77]
    DIRECTION INPUT ;
    USE SIGNAL ;
    PORT
      LAYER Metal3 ;
        RECT  0 282.46 0.4 282.86 ;
    END
  END window_i[77]
  PIN window_i[78]
    DIRECTION INPUT ;
    USE SIGNAL ;
    PORT
      LAYER Metal3 ;
        RECT  0 284.98 0.4 285.38 ;
    END
  END window_i[78]
  PIN window_i[79]
    DIRECTION INPUT ;
    USE SIGNAL ;
    PORT
      LAYER Metal3 ;
        RECT  0 287.5 0.4 287.9 ;
    END
  END window_i[79]
  PIN window_i[7]
    DIRECTION INPUT ;
    USE SIGNAL ;
    PORT
      LAYER Metal3 ;
        RECT  0 106.06 0.4 106.46 ;
    END
  END window_i[7]
  PIN window_i[80]
    DIRECTION INPUT ;
    USE SIGNAL ;
    PORT
      LAYER Metal3 ;
        RECT  0 290.02 0.4 290.42 ;
    END
  END window_i[80]
  PIN window_i[81]
    DIRECTION INPUT ;
    USE SIGNAL ;
    PORT
      LAYER Metal3 ;
        RECT  0 292.54 0.4 292.94 ;
    END
  END window_i[81]
  PIN window_i[82]
    DIRECTION INPUT ;
    USE SIGNAL ;
    PORT
      LAYER Metal3 ;
        RECT  0 295.06 0.4 295.46 ;
    END
  END window_i[82]
  PIN window_i[83]
    DIRECTION INPUT ;
    USE SIGNAL ;
    PORT
      LAYER Metal3 ;
        RECT  0 297.58 0.4 297.98 ;
    END
  END window_i[83]
  PIN window_i[84]
    DIRECTION INPUT ;
    USE SIGNAL ;
    PORT
      LAYER Metal3 ;
        RECT  0 300.1 0.4 300.5 ;
    END
  END window_i[84]
  PIN window_i[85]
    DIRECTION INPUT ;
    USE SIGNAL ;
    PORT
      LAYER Metal3 ;
        RECT  0 302.62 0.4 303.02 ;
    END
  END window_i[85]
  PIN window_i[86]
    DIRECTION INPUT ;
    USE SIGNAL ;
    PORT
      LAYER Metal3 ;
        RECT  0 305.14 0.4 305.54 ;
    END
  END window_i[86]
  PIN window_i[87]
    DIRECTION INPUT ;
    USE SIGNAL ;
    PORT
      LAYER Metal3 ;
        RECT  0 307.66 0.4 308.06 ;
    END
  END window_i[87]
  PIN window_i[88]
    DIRECTION INPUT ;
    USE SIGNAL ;
    PORT
      LAYER Metal3 ;
        RECT  0 310.18 0.4 310.58 ;
    END
  END window_i[88]
  PIN window_i[89]
    DIRECTION INPUT ;
    USE SIGNAL ;
    PORT
      LAYER Metal3 ;
        RECT  0 312.7 0.4 313.1 ;
    END
  END window_i[89]
  PIN window_i[8]
    DIRECTION INPUT ;
    USE SIGNAL ;
    PORT
      LAYER Metal3 ;
        RECT  0 108.58 0.4 108.98 ;
    END
  END window_i[8]
  PIN window_i[90]
    DIRECTION INPUT ;
    USE SIGNAL ;
    PORT
      LAYER Metal3 ;
        RECT  0 315.22 0.4 315.62 ;
    END
  END window_i[90]
  PIN window_i[91]
    DIRECTION INPUT ;
    USE SIGNAL ;
    PORT
      LAYER Metal3 ;
        RECT  0 317.74 0.4 318.14 ;
    END
  END window_i[91]
  PIN window_i[92]
    DIRECTION INPUT ;
    USE SIGNAL ;
    PORT
      LAYER Metal3 ;
        RECT  0 320.26 0.4 320.66 ;
    END
  END window_i[92]
  PIN window_i[93]
    DIRECTION INPUT ;
    USE SIGNAL ;
    PORT
      LAYER Metal3 ;
        RECT  0 322.78 0.4 323.18 ;
    END
  END window_i[93]
  PIN window_i[94]
    DIRECTION INPUT ;
    USE SIGNAL ;
    PORT
      LAYER Metal3 ;
        RECT  0 325.3 0.4 325.7 ;
    END
  END window_i[94]
  PIN window_i[95]
    DIRECTION INPUT ;
    USE SIGNAL ;
    PORT
      LAYER Metal3 ;
        RECT  0 327.82 0.4 328.22 ;
    END
  END window_i[95]
  PIN window_i[96]
    DIRECTION INPUT ;
    USE SIGNAL ;
    PORT
      LAYER Metal3 ;
        RECT  0 330.34 0.4 330.74 ;
    END
  END window_i[96]
  PIN window_i[97]
    DIRECTION INPUT ;
    USE SIGNAL ;
    PORT
      LAYER Metal3 ;
        RECT  0 332.86 0.4 333.26 ;
    END
  END window_i[97]
  PIN window_i[98]
    DIRECTION INPUT ;
    USE SIGNAL ;
    PORT
      LAYER Metal3 ;
        RECT  0 335.38 0.4 335.78 ;
    END
  END window_i[98]
  PIN window_i[99]
    DIRECTION INPUT ;
    USE SIGNAL ;
    PORT
      LAYER Metal3 ;
        RECT  0 337.9 0.4 338.3 ;
    END
  END window_i[99]
  PIN window_i[9]
    DIRECTION INPUT ;
    USE SIGNAL ;
    PORT
      LAYER Metal3 ;
        RECT  0 111.1 0.4 111.5 ;
    END
  END window_i[9]
  PIN window_pc_i[0]
    DIRECTION INPUT ;
    USE SIGNAL ;
    PORT
      LAYER Metal3 ;
        RECT  0 829.3 0.4 829.7 ;
    END
  END window_pc_i[0]
  PIN window_pc_i[10]
    DIRECTION INPUT ;
    USE SIGNAL ;
    PORT
      LAYER Metal3 ;
        RECT  0 854.5 0.4 854.9 ;
    END
  END window_pc_i[10]
  PIN window_pc_i[11]
    DIRECTION INPUT ;
    USE SIGNAL ;
    PORT
      LAYER Metal3 ;
        RECT  0 857.02 0.4 857.42 ;
    END
  END window_pc_i[11]
  PIN window_pc_i[12]
    DIRECTION INPUT ;
    USE SIGNAL ;
    PORT
      LAYER Metal3 ;
        RECT  0 859.54 0.4 859.94 ;
    END
  END window_pc_i[12]
  PIN window_pc_i[13]
    DIRECTION INPUT ;
    USE SIGNAL ;
    PORT
      LAYER Metal3 ;
        RECT  0 862.06 0.4 862.46 ;
    END
  END window_pc_i[13]
  PIN window_pc_i[14]
    DIRECTION INPUT ;
    USE SIGNAL ;
    PORT
      LAYER Metal3 ;
        RECT  0 864.58 0.4 864.98 ;
    END
  END window_pc_i[14]
  PIN window_pc_i[15]
    DIRECTION INPUT ;
    USE SIGNAL ;
    PORT
      LAYER Metal3 ;
        RECT  0 867.1 0.4 867.5 ;
    END
  END window_pc_i[15]
  PIN window_pc_i[16]
    DIRECTION INPUT ;
    USE SIGNAL ;
    PORT
      LAYER Metal3 ;
        RECT  0 869.62 0.4 870.02 ;
    END
  END window_pc_i[16]
  PIN window_pc_i[17]
    DIRECTION INPUT ;
    USE SIGNAL ;
    PORT
      LAYER Metal3 ;
        RECT  0 872.14 0.4 872.54 ;
    END
  END window_pc_i[17]
  PIN window_pc_i[18]
    DIRECTION INPUT ;
    USE SIGNAL ;
    PORT
      LAYER Metal3 ;
        RECT  0 874.66 0.4 875.06 ;
    END
  END window_pc_i[18]
  PIN window_pc_i[19]
    DIRECTION INPUT ;
    USE SIGNAL ;
    PORT
      LAYER Metal3 ;
        RECT  0 877.18 0.4 877.58 ;
    END
  END window_pc_i[19]
  PIN window_pc_i[1]
    DIRECTION INPUT ;
    USE SIGNAL ;
    PORT
      LAYER Metal3 ;
        RECT  0 831.82 0.4 832.22 ;
    END
  END window_pc_i[1]
  PIN window_pc_i[20]
    DIRECTION INPUT ;
    USE SIGNAL ;
    PORT
      LAYER Metal3 ;
        RECT  0 879.7 0.4 880.1 ;
    END
  END window_pc_i[20]
  PIN window_pc_i[21]
    DIRECTION INPUT ;
    USE SIGNAL ;
    PORT
      LAYER Metal3 ;
        RECT  0 882.22 0.4 882.62 ;
    END
  END window_pc_i[21]
  PIN window_pc_i[22]
    DIRECTION INPUT ;
    USE SIGNAL ;
    PORT
      LAYER Metal3 ;
        RECT  0 884.74 0.4 885.14 ;
    END
  END window_pc_i[22]
  PIN window_pc_i[23]
    DIRECTION INPUT ;
    USE SIGNAL ;
    PORT
      LAYER Metal3 ;
        RECT  0 887.26 0.4 887.66 ;
    END
  END window_pc_i[23]
  PIN window_pc_i[24]
    DIRECTION INPUT ;
    USE SIGNAL ;
    PORT
      LAYER Metal3 ;
        RECT  0 889.78 0.4 890.18 ;
    END
  END window_pc_i[24]
  PIN window_pc_i[25]
    DIRECTION INPUT ;
    USE SIGNAL ;
    PORT
      LAYER Metal3 ;
        RECT  0 892.3 0.4 892.7 ;
    END
  END window_pc_i[25]
  PIN window_pc_i[26]
    DIRECTION INPUT ;
    USE SIGNAL ;
    PORT
      LAYER Metal3 ;
        RECT  0 894.82 0.4 895.22 ;
    END
  END window_pc_i[26]
  PIN window_pc_i[27]
    DIRECTION INPUT ;
    USE SIGNAL ;
    PORT
      LAYER Metal3 ;
        RECT  0 897.34 0.4 897.74 ;
    END
  END window_pc_i[27]
  PIN window_pc_i[28]
    DIRECTION INPUT ;
    USE SIGNAL ;
    PORT
      LAYER Metal3 ;
        RECT  0 899.86 0.4 900.26 ;
    END
  END window_pc_i[28]
  PIN window_pc_i[29]
    DIRECTION INPUT ;
    USE SIGNAL ;
    PORT
      LAYER Metal3 ;
        RECT  0 902.38 0.4 902.78 ;
    END
  END window_pc_i[29]
  PIN window_pc_i[2]
    DIRECTION INPUT ;
    USE SIGNAL ;
    PORT
      LAYER Metal3 ;
        RECT  0 834.34 0.4 834.74 ;
    END
  END window_pc_i[2]
  PIN window_pc_i[30]
    DIRECTION INPUT ;
    USE SIGNAL ;
    PORT
      LAYER Metal3 ;
        RECT  0 904.9 0.4 905.3 ;
    END
  END window_pc_i[30]
  PIN window_pc_i[31]
    DIRECTION INPUT ;
    USE SIGNAL ;
    PORT
      LAYER Metal3 ;
        RECT  0 907.42 0.4 907.82 ;
    END
  END window_pc_i[31]
  PIN window_pc_i[3]
    DIRECTION INPUT ;
    USE SIGNAL ;
    PORT
      LAYER Metal3 ;
        RECT  0 836.86 0.4 837.26 ;
    END
  END window_pc_i[3]
  PIN window_pc_i[4]
    DIRECTION INPUT ;
    USE SIGNAL ;
    PORT
      LAYER Metal3 ;
        RECT  0 839.38 0.4 839.78 ;
    END
  END window_pc_i[4]
  PIN window_pc_i[5]
    DIRECTION INPUT ;
    USE SIGNAL ;
    PORT
      LAYER Metal3 ;
        RECT  0 841.9 0.4 842.3 ;
    END
  END window_pc_i[5]
  PIN window_pc_i[6]
    DIRECTION INPUT ;
    USE SIGNAL ;
    PORT
      LAYER Metal3 ;
        RECT  0 844.42 0.4 844.82 ;
    END
  END window_pc_i[6]
  PIN window_pc_i[7]
    DIRECTION INPUT ;
    USE SIGNAL ;
    PORT
      LAYER Metal3 ;
        RECT  0 846.94 0.4 847.34 ;
    END
  END window_pc_i[7]
  PIN window_pc_i[8]
    DIRECTION INPUT ;
    USE SIGNAL ;
    PORT
      LAYER Metal3 ;
        RECT  0 849.46 0.4 849.86 ;
    END
  END window_pc_i[8]
  PIN window_pc_i[9]
    DIRECTION INPUT ;
    USE SIGNAL ;
    PORT
      LAYER Metal3 ;
        RECT  0 851.98 0.4 852.38 ;
    END
  END window_pc_i[9]
  PIN VPWR
    DIRECTION INOUT ;
    USE POWER ;
    PORT
      LAYER TopMetal1 ;
        RECT  5.76 1074.12 894.24 1076.12 ;
        RECT  5.76 1024.12 894.24 1026.12 ;
        RECT  5.76 974.12 894.24 976.12 ;
        RECT  5.76 924.12 894.24 926.12 ;
        RECT  5.76 874.12 894.24 876.12 ;
        RECT  5.76 824.12 894.24 826.12 ;
        RECT  5.76 774.12 894.24 776.12 ;
        RECT  5.76 724.12 894.24 726.12 ;
        RECT  5.76 674.12 894.24 676.12 ;
        RECT  5.76 624.12 894.24 626.12 ;
        RECT  5.76 574.12 894.24 576.12 ;
        RECT  5.76 524.12 894.24 526.12 ;
        RECT  5.76 474.12 894.24 476.12 ;
        RECT  5.76 424.12 894.24 426.12 ;
        RECT  5.76 374.12 894.24 376.12 ;
        RECT  5.76 324.12 894.24 326.12 ;
        RECT  5.76 274.12 894.24 276.12 ;
        RECT  5.76 224.12 894.24 226.12 ;
        RECT  5.76 174.12 894.24 176.12 ;
        RECT  5.76 124.12 894.24 126.12 ;
        RECT  5.76 74.12 894.24 76.12 ;
        RECT  5.76 24.12 894.24 26.12 ;
      LAYER Metal4 ;
        RECT  865.26 14.9 866.26 1085.08 ;
        RECT  815.26 14.9 816.26 1085.08 ;
        RECT  765.26 14.9 766.26 1085.08 ;
        RECT  715.26 14.9 716.26 1085.08 ;
        RECT  665.26 14.9 666.26 1085.08 ;
        RECT  615.26 14.9 616.26 1085.08 ;
        RECT  565.26 14.9 566.26 1085.08 ;
        RECT  515.26 14.9 516.26 1085.08 ;
        RECT  465.26 14.9 466.26 1085.08 ;
        RECT  415.26 14.9 416.26 1085.08 ;
        RECT  365.26 14.9 366.26 1085.08 ;
        RECT  315.26 14.9 316.26 1085.08 ;
        RECT  265.26 14.9 266.26 1085.08 ;
        RECT  215.26 14.9 216.26 1085.08 ;
        RECT  165.26 14.9 166.26 1085.08 ;
        RECT  115.26 14.9 116.26 1085.08 ;
        RECT  65.26 14.9 66.26 1085.08 ;
        RECT  15.26 14.9 16.26 1085.08 ;
    END
  END VPWR
  PIN VGND
    DIRECTION INOUT ;
    USE GROUND ;
    PORT
      LAYER TopMetal1 ;
        RECT  5.76 1080.12 894.24 1082.12 ;
        RECT  5.76 1030.12 894.24 1032.12 ;
        RECT  5.76 980.12 894.24 982.12 ;
        RECT  5.76 930.12 894.24 932.12 ;
        RECT  5.76 880.12 894.24 882.12 ;
        RECT  5.76 830.12 894.24 832.12 ;
        RECT  5.76 780.12 894.24 782.12 ;
        RECT  5.76 730.12 894.24 732.12 ;
        RECT  5.76 680.12 894.24 682.12 ;
        RECT  5.76 630.12 894.24 632.12 ;
        RECT  5.76 580.12 894.24 582.12 ;
        RECT  5.76 530.12 894.24 532.12 ;
        RECT  5.76 480.12 894.24 482.12 ;
        RECT  5.76 430.12 894.24 432.12 ;
        RECT  5.76 380.12 894.24 382.12 ;
        RECT  5.76 330.12 894.24 332.12 ;
        RECT  5.76 280.12 894.24 282.12 ;
        RECT  5.76 230.12 894.24 232.12 ;
        RECT  5.76 180.12 894.24 182.12 ;
        RECT  5.76 130.12 894.24 132.12 ;
        RECT  5.76 80.12 894.24 82.12 ;
        RECT  5.76 30.12 894.24 32.12 ;
      LAYER Metal4 ;
        RECT  868.26 14.9 869.26 1085.08 ;
        RECT  818.26 14.9 819.26 1085.08 ;
        RECT  768.26 14.9 769.26 1085.08 ;
        RECT  718.26 14.9 719.26 1085.08 ;
        RECT  668.26 14.9 669.26 1085.08 ;
        RECT  618.26 14.9 619.26 1085.08 ;
        RECT  568.26 14.9 569.26 1085.08 ;
        RECT  518.26 14.9 519.26 1085.08 ;
        RECT  468.26 14.9 469.26 1085.08 ;
        RECT  418.26 14.9 419.26 1085.08 ;
        RECT  368.26 14.9 369.26 1085.08 ;
        RECT  318.26 14.9 319.26 1085.08 ;
        RECT  268.26 14.9 269.26 1085.08 ;
        RECT  218.26 14.9 219.26 1085.08 ;
        RECT  168.26 14.9 169.26 1085.08 ;
        RECT  118.26 14.9 119.26 1085.08 ;
        RECT  68.26 14.9 69.26 1085.08 ;
        RECT  18.26 14.9 19.26 1085.08 ;
    END
  END VGND
  OBS
    LAYER Metal1 ;
     RECT  0 2.795 900 1100 ;
    LAYER Metal2 ;
     RECT  0 2.795 900 1100 ;
    LAYER Metal3 ;
     RECT  0 2.795 900 1100 ;
    LAYER Metal4 ;
     RECT  0 2.795 900 1100 ;
    LAYER TopMetal1 ;
     RECT  0 2.795 900 1100 ;
  END
END ino_decode_predict
END LIBRARY
